VERSION 5.8 ;
BUSBITCHARS "[]" ;
DIVIDERCHAR "/" ;
UNITS
    DATABASE MICRONS 1000 ;
END UNITS

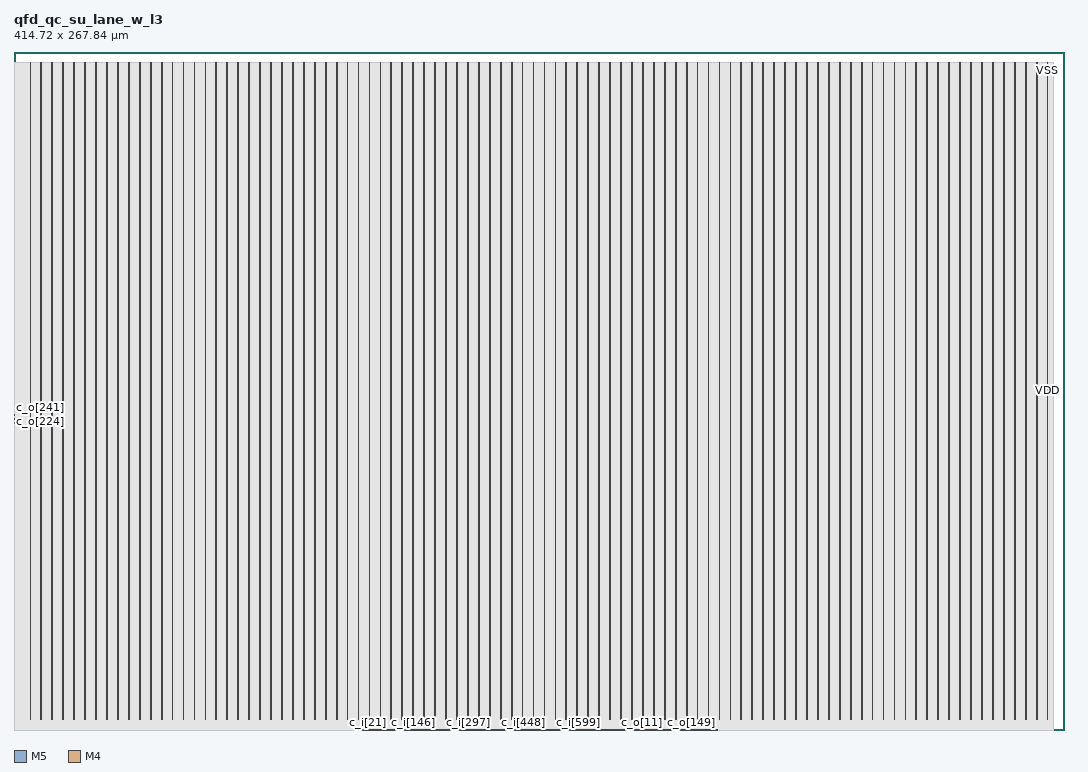
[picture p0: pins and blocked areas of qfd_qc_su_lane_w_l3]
MACRO qfd_qc_su_lane_w_l3
  FOREIGN qfd_qc_su_lane_w_l3 0 0 ;
  CLASS BLOCK ;
  SIZE 414.72 BY 267.84 ;
  PIN c_i[0]
    DIRECTION INPUT ;
    USE SIGNAL ;
    PORT
      LAYER M5 ;
        RECT  136.848 0 136.872 0.084 ;
    END
  END c_i[0]
  PIN c_i[100]
    DIRECTION INPUT ;
    USE SIGNAL ;
    PORT
      LAYER M5 ;
        RECT  151.248 0 151.272 0.084 ;
    END
  END c_i[100]
  PIN c_i[101]
    DIRECTION INPUT ;
    USE SIGNAL ;
    PORT
      LAYER M5 ;
        RECT  151.392 0 151.416 0.084 ;
    END
  END c_i[101]
  PIN c_i[102]
    DIRECTION INPUT ;
    USE SIGNAL ;
    PORT
      LAYER M5 ;
        RECT  151.536 0 151.56 0.084 ;
    END
  END c_i[102]
  PIN c_i[103]
    DIRECTION INPUT ;
    USE SIGNAL ;
    PORT
      LAYER M5 ;
        RECT  151.68 0 151.704 0.084 ;
    END
  END c_i[103]
  PIN c_i[104]
    DIRECTION INPUT ;
    USE SIGNAL ;
    PORT
      LAYER M5 ;
        RECT  151.824 0 151.848 0.084 ;
    END
  END c_i[104]
  PIN c_i[105]
    DIRECTION INPUT ;
    USE SIGNAL ;
    PORT
      LAYER M5 ;
        RECT  151.968 0 151.992 0.084 ;
    END
  END c_i[105]
  PIN c_i[106]
    DIRECTION INPUT ;
    USE SIGNAL ;
    PORT
      LAYER M5 ;
        RECT  152.112 0 152.136 0.084 ;
    END
  END c_i[106]
  PIN c_i[107]
    DIRECTION INPUT ;
    USE SIGNAL ;
    PORT
      LAYER M5 ;
        RECT  152.256 0 152.28 0.084 ;
    END
  END c_i[107]
  PIN c_i[108]
    DIRECTION INPUT ;
    USE SIGNAL ;
    PORT
      LAYER M5 ;
        RECT  152.4 0 152.424 0.084 ;
    END
  END c_i[108]
  PIN c_i[109]
    DIRECTION INPUT ;
    USE SIGNAL ;
    PORT
      LAYER M5 ;
        RECT  152.544 0 152.568 0.084 ;
    END
  END c_i[109]
  PIN c_i[10]
    DIRECTION INPUT ;
    USE SIGNAL ;
    PORT
      LAYER M5 ;
        RECT  138.288 0 138.312 0.084 ;
    END
  END c_i[10]
  PIN c_i[110]
    DIRECTION INPUT ;
    USE SIGNAL ;
    PORT
      LAYER M5 ;
        RECT  152.688 0 152.712 0.084 ;
    END
  END c_i[110]
  PIN c_i[111]
    DIRECTION INPUT ;
    USE SIGNAL ;
    PORT
      LAYER M5 ;
        RECT  152.832 0 152.856 0.084 ;
    END
  END c_i[111]
  PIN c_i[112]
    DIRECTION INPUT ;
    USE SIGNAL ;
    PORT
      LAYER M5 ;
        RECT  152.976 0 153 0.084 ;
    END
  END c_i[112]
  PIN c_i[113]
    DIRECTION INPUT ;
    USE SIGNAL ;
    PORT
      LAYER M5 ;
        RECT  153.12 0 153.144 0.084 ;
    END
  END c_i[113]
  PIN c_i[114]
    DIRECTION INPUT ;
    USE SIGNAL ;
    PORT
      LAYER M5 ;
        RECT  153.264 0 153.288 0.084 ;
    END
  END c_i[114]
  PIN c_i[115]
    DIRECTION INPUT ;
    USE SIGNAL ;
    PORT
      LAYER M5 ;
        RECT  153.408 0 153.432 0.084 ;
    END
  END c_i[115]
  PIN c_i[116]
    DIRECTION INPUT ;
    USE SIGNAL ;
    PORT
      LAYER M5 ;
        RECT  153.552 0 153.576 0.084 ;
    END
  END c_i[116]
  PIN c_i[117]
    DIRECTION INPUT ;
    USE SIGNAL ;
    PORT
      LAYER M5 ;
        RECT  153.696 0 153.72 0.084 ;
    END
  END c_i[117]
  PIN c_i[118]
    DIRECTION INPUT ;
    USE SIGNAL ;
    PORT
      LAYER M5 ;
        RECT  153.84 0 153.864 0.084 ;
    END
  END c_i[118]
  PIN c_i[119]
    DIRECTION INPUT ;
    USE SIGNAL ;
    PORT
      LAYER M5 ;
        RECT  153.984 0 154.008 0.084 ;
    END
  END c_i[119]
  PIN c_i[11]
    DIRECTION INPUT ;
    USE SIGNAL ;
    PORT
      LAYER M5 ;
        RECT  138.432 0 138.456 0.084 ;
    END
  END c_i[11]
  PIN c_i[120]
    DIRECTION INPUT ;
    USE SIGNAL ;
    PORT
      LAYER M5 ;
        RECT  154.128 0 154.152 0.084 ;
    END
  END c_i[120]
  PIN c_i[121]
    DIRECTION INPUT ;
    USE SIGNAL ;
    PORT
      LAYER M5 ;
        RECT  154.272 0 154.296 0.084 ;
    END
  END c_i[121]
  PIN c_i[122]
    DIRECTION INPUT ;
    USE SIGNAL ;
    PORT
      LAYER M5 ;
        RECT  154.416 0 154.44 0.084 ;
    END
  END c_i[122]
  PIN c_i[123]
    DIRECTION INPUT ;
    USE SIGNAL ;
    PORT
      LAYER M5 ;
        RECT  154.56 0 154.584 0.084 ;
    END
  END c_i[123]
  PIN c_i[124]
    DIRECTION INPUT ;
    USE SIGNAL ;
    PORT
      LAYER M5 ;
        RECT  154.704 0 154.728 0.084 ;
    END
  END c_i[124]
  PIN c_i[125]
    DIRECTION INPUT ;
    USE SIGNAL ;
    PORT
      LAYER M5 ;
        RECT  154.848 0 154.872 0.084 ;
    END
  END c_i[125]
  PIN c_i[126]
    DIRECTION INPUT ;
    USE SIGNAL ;
    PORT
      LAYER M5 ;
        RECT  154.992 0 155.016 0.084 ;
    END
  END c_i[126]
  PIN c_i[127]
    DIRECTION INPUT ;
    USE SIGNAL ;
    PORT
      LAYER M5 ;
        RECT  155.136 0 155.16 0.084 ;
    END
  END c_i[127]
  PIN c_i[128]
    DIRECTION INPUT ;
    USE SIGNAL ;
    PORT
      LAYER M5 ;
        RECT  155.28 0 155.304 0.084 ;
    END
  END c_i[128]
  PIN c_i[129]
    DIRECTION INPUT ;
    USE SIGNAL ;
    PORT
      LAYER M5 ;
        RECT  155.424 0 155.448 0.084 ;
    END
  END c_i[129]
  PIN c_i[12]
    DIRECTION INPUT ;
    USE SIGNAL ;
    PORT
      LAYER M5 ;
        RECT  138.576 0 138.6 0.084 ;
    END
  END c_i[12]
  PIN c_i[130]
    DIRECTION INPUT ;
    USE SIGNAL ;
    PORT
      LAYER M5 ;
        RECT  155.568 0 155.592 0.084 ;
    END
  END c_i[130]
  PIN c_i[131]
    DIRECTION INPUT ;
    USE SIGNAL ;
    PORT
      LAYER M5 ;
        RECT  155.712 0 155.736 0.084 ;
    END
  END c_i[131]
  PIN c_i[132]
    DIRECTION INPUT ;
    USE SIGNAL ;
    PORT
      LAYER M5 ;
        RECT  155.856 0 155.88 0.084 ;
    END
  END c_i[132]
  PIN c_i[133]
    DIRECTION INPUT ;
    USE SIGNAL ;
    PORT
      LAYER M5 ;
        RECT  156 0 156.024 0.084 ;
    END
  END c_i[133]
  PIN c_i[134]
    DIRECTION INPUT ;
    USE SIGNAL ;
    PORT
      LAYER M5 ;
        RECT  156.144 0 156.168 0.084 ;
    END
  END c_i[134]
  PIN c_i[135]
    DIRECTION INPUT ;
    USE SIGNAL ;
    PORT
      LAYER M5 ;
        RECT  156.288 0 156.312 0.084 ;
    END
  END c_i[135]
  PIN c_i[136]
    DIRECTION INPUT ;
    USE SIGNAL ;
    PORT
      LAYER M5 ;
        RECT  156.432 0 156.456 0.084 ;
    END
  END c_i[136]
  PIN c_i[137]
    DIRECTION INPUT ;
    USE SIGNAL ;
    PORT
      LAYER M5 ;
        RECT  156.576 0 156.6 0.084 ;
    END
  END c_i[137]
  PIN c_i[138]
    DIRECTION INPUT ;
    USE SIGNAL ;
    PORT
      LAYER M5 ;
        RECT  156.72 0 156.744 0.084 ;
    END
  END c_i[138]
  PIN c_i[139]
    DIRECTION INPUT ;
    USE SIGNAL ;
    PORT
      LAYER M5 ;
        RECT  156.864 0 156.888 0.084 ;
    END
  END c_i[139]
  PIN c_i[13]
    DIRECTION INPUT ;
    USE SIGNAL ;
    PORT
      LAYER M5 ;
        RECT  138.72 0 138.744 0.084 ;
    END
  END c_i[13]
  PIN c_i[140]
    DIRECTION INPUT ;
    USE SIGNAL ;
    PORT
      LAYER M5 ;
        RECT  157.008 0 157.032 0.084 ;
    END
  END c_i[140]
  PIN c_i[141]
    DIRECTION INPUT ;
    USE SIGNAL ;
    PORT
      LAYER M5 ;
        RECT  157.152 0 157.176 0.084 ;
    END
  END c_i[141]
  PIN c_i[142]
    DIRECTION INPUT ;
    USE SIGNAL ;
    PORT
      LAYER M5 ;
        RECT  157.296 0 157.32 0.084 ;
    END
  END c_i[142]
  PIN c_i[143]
    DIRECTION INPUT ;
    USE SIGNAL ;
    PORT
      LAYER M5 ;
        RECT  157.44 0 157.464 0.084 ;
    END
  END c_i[143]
  PIN c_i[144]
    DIRECTION INPUT ;
    USE SIGNAL ;
    PORT
      LAYER M5 ;
        RECT  157.584 0 157.608 0.084 ;
    END
  END c_i[144]
  PIN c_i[145]
    DIRECTION INPUT ;
    USE SIGNAL ;
    PORT
      LAYER M5 ;
        RECT  157.728 0 157.752 0.084 ;
    END
  END c_i[145]
  PIN c_i[146]
    DIRECTION INPUT ;
    USE SIGNAL ;
    PORT
      LAYER M5 ;
        RECT  157.872 0 157.896 0.084 ;
    END
  END c_i[146]
  PIN c_i[147]
    DIRECTION INPUT ;
    USE SIGNAL ;
    PORT
      LAYER M5 ;
        RECT  158.016 0 158.04 0.084 ;
    END
  END c_i[147]
  PIN c_i[148]
    DIRECTION INPUT ;
    USE SIGNAL ;
    PORT
      LAYER M5 ;
        RECT  158.16 0 158.184 0.084 ;
    END
  END c_i[148]
  PIN c_i[149]
    DIRECTION INPUT ;
    USE SIGNAL ;
    PORT
      LAYER M5 ;
        RECT  158.304 0 158.328 0.084 ;
    END
  END c_i[149]
  PIN c_i[14]
    DIRECTION INPUT ;
    USE SIGNAL ;
    PORT
      LAYER M5 ;
        RECT  138.864 0 138.888 0.084 ;
    END
  END c_i[14]
  PIN c_i[150]
    DIRECTION INPUT ;
    USE SIGNAL ;
    PORT
      LAYER M5 ;
        RECT  158.448 0 158.472 0.084 ;
    END
  END c_i[150]
  PIN c_i[151]
    DIRECTION INPUT ;
    USE SIGNAL ;
    PORT
      LAYER M5 ;
        RECT  158.592 0 158.616 0.084 ;
    END
  END c_i[151]
  PIN c_i[152]
    DIRECTION INPUT ;
    USE SIGNAL ;
    PORT
      LAYER M5 ;
        RECT  158.736 0 158.76 0.084 ;
    END
  END c_i[152]
  PIN c_i[153]
    DIRECTION INPUT ;
    USE SIGNAL ;
    PORT
      LAYER M5 ;
        RECT  158.88 0 158.904 0.084 ;
    END
  END c_i[153]
  PIN c_i[154]
    DIRECTION INPUT ;
    USE SIGNAL ;
    PORT
      LAYER M5 ;
        RECT  159.024 0 159.048 0.084 ;
    END
  END c_i[154]
  PIN c_i[155]
    DIRECTION INPUT ;
    USE SIGNAL ;
    PORT
      LAYER M5 ;
        RECT  159.168 0 159.192 0.084 ;
    END
  END c_i[155]
  PIN c_i[156]
    DIRECTION INPUT ;
    USE SIGNAL ;
    PORT
      LAYER M5 ;
        RECT  159.312 0 159.336 0.084 ;
    END
  END c_i[156]
  PIN c_i[157]
    DIRECTION INPUT ;
    USE SIGNAL ;
    PORT
      LAYER M5 ;
        RECT  159.456 0 159.48 0.084 ;
    END
  END c_i[157]
  PIN c_i[158]
    DIRECTION INPUT ;
    USE SIGNAL ;
    PORT
      LAYER M5 ;
        RECT  159.6 0 159.624 0.084 ;
    END
  END c_i[158]
  PIN c_i[159]
    DIRECTION INPUT ;
    USE SIGNAL ;
    PORT
      LAYER M5 ;
        RECT  159.744 0 159.768 0.084 ;
    END
  END c_i[159]
  PIN c_i[15]
    DIRECTION INPUT ;
    USE SIGNAL ;
    PORT
      LAYER M5 ;
        RECT  139.008 0 139.032 0.084 ;
    END
  END c_i[15]
  PIN c_i[160]
    DIRECTION INPUT ;
    USE SIGNAL ;
    PORT
      LAYER M5 ;
        RECT  159.888 0 159.912 0.084 ;
    END
  END c_i[160]
  PIN c_i[161]
    DIRECTION INPUT ;
    USE SIGNAL ;
    PORT
      LAYER M5 ;
        RECT  160.032 0 160.056 0.084 ;
    END
  END c_i[161]
  PIN c_i[162]
    DIRECTION INPUT ;
    USE SIGNAL ;
    PORT
      LAYER M5 ;
        RECT  160.176 0 160.2 0.084 ;
    END
  END c_i[162]
  PIN c_i[163]
    DIRECTION INPUT ;
    USE SIGNAL ;
    PORT
      LAYER M5 ;
        RECT  160.32 0 160.344 0.084 ;
    END
  END c_i[163]
  PIN c_i[164]
    DIRECTION INPUT ;
    USE SIGNAL ;
    PORT
      LAYER M5 ;
        RECT  160.464 0 160.488 0.084 ;
    END
  END c_i[164]
  PIN c_i[165]
    DIRECTION INPUT ;
    USE SIGNAL ;
    PORT
      LAYER M5 ;
        RECT  160.608 0 160.632 0.084 ;
    END
  END c_i[165]
  PIN c_i[166]
    DIRECTION INPUT ;
    USE SIGNAL ;
    PORT
      LAYER M5 ;
        RECT  160.752 0 160.776 0.084 ;
    END
  END c_i[166]
  PIN c_i[167]
    DIRECTION INPUT ;
    USE SIGNAL ;
    PORT
      LAYER M5 ;
        RECT  160.896 0 160.92 0.084 ;
    END
  END c_i[167]
  PIN c_i[168]
    DIRECTION INPUT ;
    USE SIGNAL ;
    PORT
      LAYER M5 ;
        RECT  161.04 0 161.064 0.084 ;
    END
  END c_i[168]
  PIN c_i[169]
    DIRECTION INPUT ;
    USE SIGNAL ;
    PORT
      LAYER M5 ;
        RECT  161.184 0 161.208 0.084 ;
    END
  END c_i[169]
  PIN c_i[16]
    DIRECTION INPUT ;
    USE SIGNAL ;
    PORT
      LAYER M5 ;
        RECT  139.152 0 139.176 0.084 ;
    END
  END c_i[16]
  PIN c_i[170]
    DIRECTION INPUT ;
    USE SIGNAL ;
    PORT
      LAYER M5 ;
        RECT  161.328 0 161.352 0.084 ;
    END
  END c_i[170]
  PIN c_i[171]
    DIRECTION INPUT ;
    USE SIGNAL ;
    PORT
      LAYER M5 ;
        RECT  161.472 0 161.496 0.084 ;
    END
  END c_i[171]
  PIN c_i[172]
    DIRECTION INPUT ;
    USE SIGNAL ;
    PORT
      LAYER M5 ;
        RECT  161.616 0 161.64 0.084 ;
    END
  END c_i[172]
  PIN c_i[173]
    DIRECTION INPUT ;
    USE SIGNAL ;
    PORT
      LAYER M5 ;
        RECT  161.76 0 161.784 0.084 ;
    END
  END c_i[173]
  PIN c_i[174]
    DIRECTION INPUT ;
    USE SIGNAL ;
    PORT
      LAYER M5 ;
        RECT  161.904 0 161.928 0.084 ;
    END
  END c_i[174]
  PIN c_i[175]
    DIRECTION INPUT ;
    USE SIGNAL ;
    PORT
      LAYER M5 ;
        RECT  162.048 0 162.072 0.084 ;
    END
  END c_i[175]
  PIN c_i[176]
    DIRECTION INPUT ;
    USE SIGNAL ;
    PORT
      LAYER M5 ;
        RECT  162.192 0 162.216 0.084 ;
    END
  END c_i[176]
  PIN c_i[177]
    DIRECTION INPUT ;
    USE SIGNAL ;
    PORT
      LAYER M5 ;
        RECT  162.336 0 162.36 0.084 ;
    END
  END c_i[177]
  PIN c_i[178]
    DIRECTION INPUT ;
    USE SIGNAL ;
    PORT
      LAYER M5 ;
        RECT  162.48 0 162.504 0.084 ;
    END
  END c_i[178]
  PIN c_i[179]
    DIRECTION INPUT ;
    USE SIGNAL ;
    PORT
      LAYER M5 ;
        RECT  162.624 0 162.648 0.084 ;
    END
  END c_i[179]
  PIN c_i[17]
    DIRECTION INPUT ;
    USE SIGNAL ;
    PORT
      LAYER M5 ;
        RECT  139.296 0 139.32 0.084 ;
    END
  END c_i[17]
  PIN c_i[180]
    DIRECTION INPUT ;
    USE SIGNAL ;
    PORT
      LAYER M5 ;
        RECT  162.768 0 162.792 0.084 ;
    END
  END c_i[180]
  PIN c_i[181]
    DIRECTION INPUT ;
    USE SIGNAL ;
    PORT
      LAYER M5 ;
        RECT  162.912 0 162.936 0.084 ;
    END
  END c_i[181]
  PIN c_i[182]
    DIRECTION INPUT ;
    USE SIGNAL ;
    PORT
      LAYER M5 ;
        RECT  163.056 0 163.08 0.084 ;
    END
  END c_i[182]
  PIN c_i[183]
    DIRECTION INPUT ;
    USE SIGNAL ;
    PORT
      LAYER M5 ;
        RECT  163.2 0 163.224 0.084 ;
    END
  END c_i[183]
  PIN c_i[184]
    DIRECTION INPUT ;
    USE SIGNAL ;
    PORT
      LAYER M5 ;
        RECT  163.344 0 163.368 0.084 ;
    END
  END c_i[184]
  PIN c_i[185]
    DIRECTION INPUT ;
    USE SIGNAL ;
    PORT
      LAYER M5 ;
        RECT  163.488 0 163.512 0.084 ;
    END
  END c_i[185]
  PIN c_i[186]
    DIRECTION INPUT ;
    USE SIGNAL ;
    PORT
      LAYER M5 ;
        RECT  163.632 0 163.656 0.084 ;
    END
  END c_i[186]
  PIN c_i[187]
    DIRECTION INPUT ;
    USE SIGNAL ;
    PORT
      LAYER M5 ;
        RECT  163.776 0 163.8 0.084 ;
    END
  END c_i[187]
  PIN c_i[188]
    DIRECTION INPUT ;
    USE SIGNAL ;
    PORT
      LAYER M5 ;
        RECT  163.92 0 163.944 0.084 ;
    END
  END c_i[188]
  PIN c_i[189]
    DIRECTION INPUT ;
    USE SIGNAL ;
    PORT
      LAYER M5 ;
        RECT  164.064 0 164.088 0.084 ;
    END
  END c_i[189]
  PIN c_i[18]
    DIRECTION INPUT ;
    USE SIGNAL ;
    PORT
      LAYER M5 ;
        RECT  139.44 0 139.464 0.084 ;
    END
  END c_i[18]
  PIN c_i[190]
    DIRECTION INPUT ;
    USE SIGNAL ;
    PORT
      LAYER M5 ;
        RECT  164.208 0 164.232 0.084 ;
    END
  END c_i[190]
  PIN c_i[191]
    DIRECTION INPUT ;
    USE SIGNAL ;
    PORT
      LAYER M5 ;
        RECT  164.352 0 164.376 0.084 ;
    END
  END c_i[191]
  PIN c_i[192]
    DIRECTION INPUT ;
    USE SIGNAL ;
    PORT
      LAYER M5 ;
        RECT  164.496 0 164.52 0.084 ;
    END
  END c_i[192]
  PIN c_i[193]
    DIRECTION INPUT ;
    USE SIGNAL ;
    PORT
      LAYER M5 ;
        RECT  164.64 0 164.664 0.084 ;
    END
  END c_i[193]
  PIN c_i[194]
    DIRECTION INPUT ;
    USE SIGNAL ;
    PORT
      LAYER M5 ;
        RECT  164.784 0 164.808 0.084 ;
    END
  END c_i[194]
  PIN c_i[195]
    DIRECTION INPUT ;
    USE SIGNAL ;
    PORT
      LAYER M5 ;
        RECT  164.928 0 164.952 0.084 ;
    END
  END c_i[195]
  PIN c_i[196]
    DIRECTION INPUT ;
    USE SIGNAL ;
    PORT
      LAYER M5 ;
        RECT  165.072 0 165.096 0.084 ;
    END
  END c_i[196]
  PIN c_i[197]
    DIRECTION INPUT ;
    USE SIGNAL ;
    PORT
      LAYER M5 ;
        RECT  165.216 0 165.24 0.084 ;
    END
  END c_i[197]
  PIN c_i[198]
    DIRECTION INPUT ;
    USE SIGNAL ;
    PORT
      LAYER M5 ;
        RECT  165.36 0 165.384 0.084 ;
    END
  END c_i[198]
  PIN c_i[199]
    DIRECTION INPUT ;
    USE SIGNAL ;
    PORT
      LAYER M5 ;
        RECT  165.504 0 165.528 0.084 ;
    END
  END c_i[199]
  PIN c_i[19]
    DIRECTION INPUT ;
    USE SIGNAL ;
    PORT
      LAYER M5 ;
        RECT  139.584 0 139.608 0.084 ;
    END
  END c_i[19]
  PIN c_i[1]
    DIRECTION INPUT ;
    USE SIGNAL ;
    PORT
      LAYER M5 ;
        RECT  136.992 0 137.016 0.084 ;
    END
  END c_i[1]
  PIN c_i[200]
    DIRECTION INPUT ;
    USE SIGNAL ;
    PORT
      LAYER M5 ;
        RECT  165.648 0 165.672 0.084 ;
    END
  END c_i[200]
  PIN c_i[201]
    DIRECTION INPUT ;
    USE SIGNAL ;
    PORT
      LAYER M5 ;
        RECT  165.792 0 165.816 0.084 ;
    END
  END c_i[201]
  PIN c_i[202]
    DIRECTION INPUT ;
    USE SIGNAL ;
    PORT
      LAYER M5 ;
        RECT  165.936 0 165.96 0.084 ;
    END
  END c_i[202]
  PIN c_i[203]
    DIRECTION INPUT ;
    USE SIGNAL ;
    PORT
      LAYER M5 ;
        RECT  166.08 0 166.104 0.084 ;
    END
  END c_i[203]
  PIN c_i[204]
    DIRECTION INPUT ;
    USE SIGNAL ;
    PORT
      LAYER M5 ;
        RECT  166.224 0 166.248 0.084 ;
    END
  END c_i[204]
  PIN c_i[205]
    DIRECTION INPUT ;
    USE SIGNAL ;
    PORT
      LAYER M5 ;
        RECT  166.368 0 166.392 0.084 ;
    END
  END c_i[205]
  PIN c_i[206]
    DIRECTION INPUT ;
    USE SIGNAL ;
    PORT
      LAYER M5 ;
        RECT  166.512 0 166.536 0.084 ;
    END
  END c_i[206]
  PIN c_i[207]
    DIRECTION INPUT ;
    USE SIGNAL ;
    PORT
      LAYER M5 ;
        RECT  166.656 0 166.68 0.084 ;
    END
  END c_i[207]
  PIN c_i[208]
    DIRECTION INPUT ;
    USE SIGNAL ;
    PORT
      LAYER M5 ;
        RECT  166.8 0 166.824 0.084 ;
    END
  END c_i[208]
  PIN c_i[209]
    DIRECTION INPUT ;
    USE SIGNAL ;
    PORT
      LAYER M5 ;
        RECT  166.944 0 166.968 0.084 ;
    END
  END c_i[209]
  PIN c_i[20]
    DIRECTION INPUT ;
    USE SIGNAL ;
    PORT
      LAYER M5 ;
        RECT  139.728 0 139.752 0.084 ;
    END
  END c_i[20]
  PIN c_i[210]
    DIRECTION INPUT ;
    USE SIGNAL ;
    PORT
      LAYER M5 ;
        RECT  167.088 0 167.112 0.084 ;
    END
  END c_i[210]
  PIN c_i[211]
    DIRECTION INPUT ;
    USE SIGNAL ;
    PORT
      LAYER M5 ;
        RECT  167.232 0 167.256 0.084 ;
    END
  END c_i[211]
  PIN c_i[212]
    DIRECTION INPUT ;
    USE SIGNAL ;
    PORT
      LAYER M5 ;
        RECT  167.376 0 167.4 0.084 ;
    END
  END c_i[212]
  PIN c_i[213]
    DIRECTION INPUT ;
    USE SIGNAL ;
    PORT
      LAYER M5 ;
        RECT  167.52 0 167.544 0.084 ;
    END
  END c_i[213]
  PIN c_i[214]
    DIRECTION INPUT ;
    USE SIGNAL ;
    PORT
      LAYER M5 ;
        RECT  167.664 0 167.688 0.084 ;
    END
  END c_i[214]
  PIN c_i[215]
    DIRECTION INPUT ;
    USE SIGNAL ;
    PORT
      LAYER M5 ;
        RECT  167.808 0 167.832 0.084 ;
    END
  END c_i[215]
  PIN c_i[216]
    DIRECTION INPUT ;
    USE SIGNAL ;
    PORT
      LAYER M5 ;
        RECT  167.952 0 167.976 0.084 ;
    END
  END c_i[216]
  PIN c_i[217]
    DIRECTION INPUT ;
    USE SIGNAL ;
    PORT
      LAYER M5 ;
        RECT  168.096 0 168.12 0.084 ;
    END
  END c_i[217]
  PIN c_i[218]
    DIRECTION INPUT ;
    USE SIGNAL ;
    PORT
      LAYER M5 ;
        RECT  168.24 0 168.264 0.084 ;
    END
  END c_i[218]
  PIN c_i[219]
    DIRECTION INPUT ;
    USE SIGNAL ;
    PORT
      LAYER M5 ;
        RECT  168.384 0 168.408 0.084 ;
    END
  END c_i[219]
  PIN c_i[21]
    DIRECTION INPUT ;
    USE SIGNAL ;
    PORT
      LAYER M5 ;
        RECT  139.872 0 139.896 0.084 ;
    END
  END c_i[21]
  PIN c_i[220]
    DIRECTION INPUT ;
    USE SIGNAL ;
    PORT
      LAYER M5 ;
        RECT  168.528 0 168.552 0.084 ;
    END
  END c_i[220]
  PIN c_i[221]
    DIRECTION INPUT ;
    USE SIGNAL ;
    PORT
      LAYER M5 ;
        RECT  168.672 0 168.696 0.084 ;
    END
  END c_i[221]
  PIN c_i[222]
    DIRECTION INPUT ;
    USE SIGNAL ;
    PORT
      LAYER M5 ;
        RECT  168.816 0 168.84 0.084 ;
    END
  END c_i[222]
  PIN c_i[223]
    DIRECTION INPUT ;
    USE SIGNAL ;
    PORT
      LAYER M5 ;
        RECT  168.96 0 168.984 0.084 ;
    END
  END c_i[223]
  PIN c_i[224]
    DIRECTION INPUT ;
    USE SIGNAL ;
    PORT
      LAYER M5 ;
        RECT  169.104 0 169.128 0.084 ;
    END
  END c_i[224]
  PIN c_i[225]
    DIRECTION INPUT ;
    USE SIGNAL ;
    PORT
      LAYER M5 ;
        RECT  169.248 0 169.272 0.084 ;
    END
  END c_i[225]
  PIN c_i[226]
    DIRECTION INPUT ;
    USE SIGNAL ;
    PORT
      LAYER M5 ;
        RECT  169.392 0 169.416 0.084 ;
    END
  END c_i[226]
  PIN c_i[227]
    DIRECTION INPUT ;
    USE SIGNAL ;
    PORT
      LAYER M5 ;
        RECT  169.536 0 169.56 0.084 ;
    END
  END c_i[227]
  PIN c_i[228]
    DIRECTION INPUT ;
    USE SIGNAL ;
    PORT
      LAYER M5 ;
        RECT  169.68 0 169.704 0.084 ;
    END
  END c_i[228]
  PIN c_i[229]
    DIRECTION INPUT ;
    USE SIGNAL ;
    PORT
      LAYER M5 ;
        RECT  169.824 0 169.848 0.084 ;
    END
  END c_i[229]
  PIN c_i[22]
    DIRECTION INPUT ;
    USE SIGNAL ;
    PORT
      LAYER M5 ;
        RECT  140.016 0 140.04 0.084 ;
    END
  END c_i[22]
  PIN c_i[230]
    DIRECTION INPUT ;
    USE SIGNAL ;
    PORT
      LAYER M5 ;
        RECT  169.968 0 169.992 0.084 ;
    END
  END c_i[230]
  PIN c_i[231]
    DIRECTION INPUT ;
    USE SIGNAL ;
    PORT
      LAYER M5 ;
        RECT  170.112 0 170.136 0.084 ;
    END
  END c_i[231]
  PIN c_i[232]
    DIRECTION INPUT ;
    USE SIGNAL ;
    PORT
      LAYER M5 ;
        RECT  170.256 0 170.28 0.084 ;
    END
  END c_i[232]
  PIN c_i[233]
    DIRECTION INPUT ;
    USE SIGNAL ;
    PORT
      LAYER M5 ;
        RECT  170.4 0 170.424 0.084 ;
    END
  END c_i[233]
  PIN c_i[234]
    DIRECTION INPUT ;
    USE SIGNAL ;
    PORT
      LAYER M5 ;
        RECT  170.544 0 170.568 0.084 ;
    END
  END c_i[234]
  PIN c_i[235]
    DIRECTION INPUT ;
    USE SIGNAL ;
    PORT
      LAYER M5 ;
        RECT  170.688 0 170.712 0.084 ;
    END
  END c_i[235]
  PIN c_i[236]
    DIRECTION INPUT ;
    USE SIGNAL ;
    PORT
      LAYER M5 ;
        RECT  170.832 0 170.856 0.084 ;
    END
  END c_i[236]
  PIN c_i[237]
    DIRECTION INPUT ;
    USE SIGNAL ;
    PORT
      LAYER M5 ;
        RECT  170.976 0 171 0.084 ;
    END
  END c_i[237]
  PIN c_i[238]
    DIRECTION INPUT ;
    USE SIGNAL ;
    PORT
      LAYER M5 ;
        RECT  171.12 0 171.144 0.084 ;
    END
  END c_i[238]
  PIN c_i[239]
    DIRECTION INPUT ;
    USE SIGNAL ;
    PORT
      LAYER M5 ;
        RECT  171.264 0 171.288 0.084 ;
    END
  END c_i[239]
  PIN c_i[23]
    DIRECTION INPUT ;
    USE SIGNAL ;
    PORT
      LAYER M5 ;
        RECT  140.16 0 140.184 0.084 ;
    END
  END c_i[23]
  PIN c_i[240]
    DIRECTION INPUT ;
    USE SIGNAL ;
    PORT
      LAYER M5 ;
        RECT  171.408 0 171.432 0.084 ;
    END
  END c_i[240]
  PIN c_i[241]
    DIRECTION INPUT ;
    USE SIGNAL ;
    PORT
      LAYER M5 ;
        RECT  171.552 0 171.576 0.084 ;
    END
  END c_i[241]
  PIN c_i[242]
    DIRECTION INPUT ;
    USE SIGNAL ;
    PORT
      LAYER M5 ;
        RECT  171.696 0 171.72 0.084 ;
    END
  END c_i[242]
  PIN c_i[243]
    DIRECTION INPUT ;
    USE SIGNAL ;
    PORT
      LAYER M5 ;
        RECT  171.84 0 171.864 0.084 ;
    END
  END c_i[243]
  PIN c_i[244]
    DIRECTION INPUT ;
    USE SIGNAL ;
    PORT
      LAYER M5 ;
        RECT  171.984 0 172.008 0.084 ;
    END
  END c_i[244]
  PIN c_i[245]
    DIRECTION INPUT ;
    USE SIGNAL ;
    PORT
      LAYER M5 ;
        RECT  172.128 0 172.152 0.084 ;
    END
  END c_i[245]
  PIN c_i[246]
    DIRECTION INPUT ;
    USE SIGNAL ;
    PORT
      LAYER M5 ;
        RECT  172.272 0 172.296 0.084 ;
    END
  END c_i[246]
  PIN c_i[247]
    DIRECTION INPUT ;
    USE SIGNAL ;
    PORT
      LAYER M5 ;
        RECT  172.416 0 172.44 0.084 ;
    END
  END c_i[247]
  PIN c_i[248]
    DIRECTION INPUT ;
    USE SIGNAL ;
    PORT
      LAYER M5 ;
        RECT  172.56 0 172.584 0.084 ;
    END
  END c_i[248]
  PIN c_i[249]
    DIRECTION INPUT ;
    USE SIGNAL ;
    PORT
      LAYER M5 ;
        RECT  172.704 0 172.728 0.084 ;
    END
  END c_i[249]
  PIN c_i[24]
    DIRECTION INPUT ;
    USE SIGNAL ;
    PORT
      LAYER M5 ;
        RECT  140.304 0 140.328 0.084 ;
    END
  END c_i[24]
  PIN c_i[250]
    DIRECTION INPUT ;
    USE SIGNAL ;
    PORT
      LAYER M5 ;
        RECT  172.848 0 172.872 0.084 ;
    END
  END c_i[250]
  PIN c_i[251]
    DIRECTION INPUT ;
    USE SIGNAL ;
    PORT
      LAYER M5 ;
        RECT  172.992 0 173.016 0.084 ;
    END
  END c_i[251]
  PIN c_i[252]
    DIRECTION INPUT ;
    USE SIGNAL ;
    PORT
      LAYER M5 ;
        RECT  173.136 0 173.16 0.084 ;
    END
  END c_i[252]
  PIN c_i[253]
    DIRECTION INPUT ;
    USE SIGNAL ;
    PORT
      LAYER M5 ;
        RECT  173.28 0 173.304 0.084 ;
    END
  END c_i[253]
  PIN c_i[254]
    DIRECTION INPUT ;
    USE SIGNAL ;
    PORT
      LAYER M5 ;
        RECT  173.424 0 173.448 0.084 ;
    END
  END c_i[254]
  PIN c_i[255]
    DIRECTION INPUT ;
    USE SIGNAL ;
    PORT
      LAYER M5 ;
        RECT  173.568 0 173.592 0.084 ;
    END
  END c_i[255]
  PIN c_i[256]
    DIRECTION INPUT ;
    USE SIGNAL ;
    PORT
      LAYER M5 ;
        RECT  173.712 0 173.736 0.084 ;
    END
  END c_i[256]
  PIN c_i[257]
    DIRECTION INPUT ;
    USE SIGNAL ;
    PORT
      LAYER M5 ;
        RECT  173.856 0 173.88 0.084 ;
    END
  END c_i[257]
  PIN c_i[258]
    DIRECTION INPUT ;
    USE SIGNAL ;
    PORT
      LAYER M5 ;
        RECT  174 0 174.024 0.084 ;
    END
  END c_i[258]
  PIN c_i[259]
    DIRECTION INPUT ;
    USE SIGNAL ;
    PORT
      LAYER M5 ;
        RECT  174.144 0 174.168 0.084 ;
    END
  END c_i[259]
  PIN c_i[25]
    DIRECTION INPUT ;
    USE SIGNAL ;
    PORT
      LAYER M5 ;
        RECT  140.448 0 140.472 0.084 ;
    END
  END c_i[25]
  PIN c_i[260]
    DIRECTION INPUT ;
    USE SIGNAL ;
    PORT
      LAYER M5 ;
        RECT  174.288 0 174.312 0.084 ;
    END
  END c_i[260]
  PIN c_i[261]
    DIRECTION INPUT ;
    USE SIGNAL ;
    PORT
      LAYER M5 ;
        RECT  174.432 0 174.456 0.084 ;
    END
  END c_i[261]
  PIN c_i[262]
    DIRECTION INPUT ;
    USE SIGNAL ;
    PORT
      LAYER M5 ;
        RECT  174.576 0 174.6 0.084 ;
    END
  END c_i[262]
  PIN c_i[263]
    DIRECTION INPUT ;
    USE SIGNAL ;
    PORT
      LAYER M5 ;
        RECT  174.72 0 174.744 0.084 ;
    END
  END c_i[263]
  PIN c_i[264]
    DIRECTION INPUT ;
    USE SIGNAL ;
    PORT
      LAYER M5 ;
        RECT  174.864 0 174.888 0.084 ;
    END
  END c_i[264]
  PIN c_i[265]
    DIRECTION INPUT ;
    USE SIGNAL ;
    PORT
      LAYER M5 ;
        RECT  175.008 0 175.032 0.084 ;
    END
  END c_i[265]
  PIN c_i[266]
    DIRECTION INPUT ;
    USE SIGNAL ;
    PORT
      LAYER M5 ;
        RECT  175.152 0 175.176 0.084 ;
    END
  END c_i[266]
  PIN c_i[267]
    DIRECTION INPUT ;
    USE SIGNAL ;
    PORT
      LAYER M5 ;
        RECT  175.296 0 175.32 0.084 ;
    END
  END c_i[267]
  PIN c_i[268]
    DIRECTION INPUT ;
    USE SIGNAL ;
    PORT
      LAYER M5 ;
        RECT  175.44 0 175.464 0.084 ;
    END
  END c_i[268]
  PIN c_i[269]
    DIRECTION INPUT ;
    USE SIGNAL ;
    PORT
      LAYER M5 ;
        RECT  175.584 0 175.608 0.084 ;
    END
  END c_i[269]
  PIN c_i[26]
    DIRECTION INPUT ;
    USE SIGNAL ;
    PORT
      LAYER M5 ;
        RECT  140.592 0 140.616 0.084 ;
    END
  END c_i[26]
  PIN c_i[270]
    DIRECTION INPUT ;
    USE SIGNAL ;
    PORT
      LAYER M5 ;
        RECT  175.728 0 175.752 0.084 ;
    END
  END c_i[270]
  PIN c_i[271]
    DIRECTION INPUT ;
    USE SIGNAL ;
    PORT
      LAYER M5 ;
        RECT  175.872 0 175.896 0.084 ;
    END
  END c_i[271]
  PIN c_i[272]
    DIRECTION INPUT ;
    USE SIGNAL ;
    PORT
      LAYER M5 ;
        RECT  176.016 0 176.04 0.084 ;
    END
  END c_i[272]
  PIN c_i[273]
    DIRECTION INPUT ;
    USE SIGNAL ;
    PORT
      LAYER M5 ;
        RECT  176.16 0 176.184 0.084 ;
    END
  END c_i[273]
  PIN c_i[274]
    DIRECTION INPUT ;
    USE SIGNAL ;
    PORT
      LAYER M5 ;
        RECT  176.304 0 176.328 0.084 ;
    END
  END c_i[274]
  PIN c_i[275]
    DIRECTION INPUT ;
    USE SIGNAL ;
    PORT
      LAYER M5 ;
        RECT  176.448 0 176.472 0.084 ;
    END
  END c_i[275]
  PIN c_i[276]
    DIRECTION INPUT ;
    USE SIGNAL ;
    PORT
      LAYER M5 ;
        RECT  176.592 0 176.616 0.084 ;
    END
  END c_i[276]
  PIN c_i[277]
    DIRECTION INPUT ;
    USE SIGNAL ;
    PORT
      LAYER M5 ;
        RECT  176.736 0 176.76 0.084 ;
    END
  END c_i[277]
  PIN c_i[278]
    DIRECTION INPUT ;
    USE SIGNAL ;
    PORT
      LAYER M5 ;
        RECT  176.88 0 176.904 0.084 ;
    END
  END c_i[278]
  PIN c_i[279]
    DIRECTION INPUT ;
    USE SIGNAL ;
    PORT
      LAYER M5 ;
        RECT  177.024 0 177.048 0.084 ;
    END
  END c_i[279]
  PIN c_i[27]
    DIRECTION INPUT ;
    USE SIGNAL ;
    PORT
      LAYER M5 ;
        RECT  140.736 0 140.76 0.084 ;
    END
  END c_i[27]
  PIN c_i[280]
    DIRECTION INPUT ;
    USE SIGNAL ;
    PORT
      LAYER M5 ;
        RECT  177.168 0 177.192 0.084 ;
    END
  END c_i[280]
  PIN c_i[281]
    DIRECTION INPUT ;
    USE SIGNAL ;
    PORT
      LAYER M5 ;
        RECT  177.312 0 177.336 0.084 ;
    END
  END c_i[281]
  PIN c_i[282]
    DIRECTION INPUT ;
    USE SIGNAL ;
    PORT
      LAYER M5 ;
        RECT  177.456 0 177.48 0.084 ;
    END
  END c_i[282]
  PIN c_i[283]
    DIRECTION INPUT ;
    USE SIGNAL ;
    PORT
      LAYER M5 ;
        RECT  177.6 0 177.624 0.084 ;
    END
  END c_i[283]
  PIN c_i[284]
    DIRECTION INPUT ;
    USE SIGNAL ;
    PORT
      LAYER M5 ;
        RECT  177.744 0 177.768 0.084 ;
    END
  END c_i[284]
  PIN c_i[285]
    DIRECTION INPUT ;
    USE SIGNAL ;
    PORT
      LAYER M5 ;
        RECT  177.888 0 177.912 0.084 ;
    END
  END c_i[285]
  PIN c_i[286]
    DIRECTION INPUT ;
    USE SIGNAL ;
    PORT
      LAYER M5 ;
        RECT  178.032 0 178.056 0.084 ;
    END
  END c_i[286]
  PIN c_i[287]
    DIRECTION INPUT ;
    USE SIGNAL ;
    PORT
      LAYER M5 ;
        RECT  178.176 0 178.2 0.084 ;
    END
  END c_i[287]
  PIN c_i[288]
    DIRECTION INPUT ;
    USE SIGNAL ;
    PORT
      LAYER M5 ;
        RECT  178.32 0 178.344 0.084 ;
    END
  END c_i[288]
  PIN c_i[289]
    DIRECTION INPUT ;
    USE SIGNAL ;
    PORT
      LAYER M5 ;
        RECT  178.464 0 178.488 0.084 ;
    END
  END c_i[289]
  PIN c_i[28]
    DIRECTION INPUT ;
    USE SIGNAL ;
    PORT
      LAYER M5 ;
        RECT  140.88 0 140.904 0.084 ;
    END
  END c_i[28]
  PIN c_i[290]
    DIRECTION INPUT ;
    USE SIGNAL ;
    PORT
      LAYER M5 ;
        RECT  178.608 0 178.632 0.084 ;
    END
  END c_i[290]
  PIN c_i[291]
    DIRECTION INPUT ;
    USE SIGNAL ;
    PORT
      LAYER M5 ;
        RECT  178.752 0 178.776 0.084 ;
    END
  END c_i[291]
  PIN c_i[292]
    DIRECTION INPUT ;
    USE SIGNAL ;
    PORT
      LAYER M5 ;
        RECT  178.896 0 178.92 0.084 ;
    END
  END c_i[292]
  PIN c_i[293]
    DIRECTION INPUT ;
    USE SIGNAL ;
    PORT
      LAYER M5 ;
        RECT  179.04 0 179.064 0.084 ;
    END
  END c_i[293]
  PIN c_i[294]
    DIRECTION INPUT ;
    USE SIGNAL ;
    PORT
      LAYER M5 ;
        RECT  179.184 0 179.208 0.084 ;
    END
  END c_i[294]
  PIN c_i[295]
    DIRECTION INPUT ;
    USE SIGNAL ;
    PORT
      LAYER M5 ;
        RECT  179.328 0 179.352 0.084 ;
    END
  END c_i[295]
  PIN c_i[296]
    DIRECTION INPUT ;
    USE SIGNAL ;
    PORT
      LAYER M5 ;
        RECT  179.472 0 179.496 0.084 ;
    END
  END c_i[296]
  PIN c_i[297]
    DIRECTION INPUT ;
    USE SIGNAL ;
    PORT
      LAYER M5 ;
        RECT  179.616 0 179.64 0.084 ;
    END
  END c_i[297]
  PIN c_i[298]
    DIRECTION INPUT ;
    USE SIGNAL ;
    PORT
      LAYER M5 ;
        RECT  179.76 0 179.784 0.084 ;
    END
  END c_i[298]
  PIN c_i[299]
    DIRECTION INPUT ;
    USE SIGNAL ;
    PORT
      LAYER M5 ;
        RECT  179.904 0 179.928 0.084 ;
    END
  END c_i[299]
  PIN c_i[29]
    DIRECTION INPUT ;
    USE SIGNAL ;
    PORT
      LAYER M5 ;
        RECT  141.024 0 141.048 0.084 ;
    END
  END c_i[29]
  PIN c_i[2]
    DIRECTION INPUT ;
    USE SIGNAL ;
    PORT
      LAYER M5 ;
        RECT  137.136 0 137.16 0.084 ;
    END
  END c_i[2]
  PIN c_i[300]
    DIRECTION INPUT ;
    USE SIGNAL ;
    PORT
      LAYER M5 ;
        RECT  180.048 0 180.072 0.084 ;
    END
  END c_i[300]
  PIN c_i[301]
    DIRECTION INPUT ;
    USE SIGNAL ;
    PORT
      LAYER M5 ;
        RECT  180.192 0 180.216 0.084 ;
    END
  END c_i[301]
  PIN c_i[302]
    DIRECTION INPUT ;
    USE SIGNAL ;
    PORT
      LAYER M5 ;
        RECT  180.336 0 180.36 0.084 ;
    END
  END c_i[302]
  PIN c_i[303]
    DIRECTION INPUT ;
    USE SIGNAL ;
    PORT
      LAYER M5 ;
        RECT  180.48 0 180.504 0.084 ;
    END
  END c_i[303]
  PIN c_i[304]
    DIRECTION INPUT ;
    USE SIGNAL ;
    PORT
      LAYER M5 ;
        RECT  180.624 0 180.648 0.084 ;
    END
  END c_i[304]
  PIN c_i[305]
    DIRECTION INPUT ;
    USE SIGNAL ;
    PORT
      LAYER M5 ;
        RECT  180.768 0 180.792 0.084 ;
    END
  END c_i[305]
  PIN c_i[306]
    DIRECTION INPUT ;
    USE SIGNAL ;
    PORT
      LAYER M5 ;
        RECT  180.912 0 180.936 0.084 ;
    END
  END c_i[306]
  PIN c_i[307]
    DIRECTION INPUT ;
    USE SIGNAL ;
    PORT
      LAYER M5 ;
        RECT  181.056 0 181.08 0.084 ;
    END
  END c_i[307]
  PIN c_i[308]
    DIRECTION INPUT ;
    USE SIGNAL ;
    PORT
      LAYER M5 ;
        RECT  181.2 0 181.224 0.084 ;
    END
  END c_i[308]
  PIN c_i[309]
    DIRECTION INPUT ;
    USE SIGNAL ;
    PORT
      LAYER M5 ;
        RECT  181.344 0 181.368 0.084 ;
    END
  END c_i[309]
  PIN c_i[30]
    DIRECTION INPUT ;
    USE SIGNAL ;
    PORT
      LAYER M5 ;
        RECT  141.168 0 141.192 0.084 ;
    END
  END c_i[30]
  PIN c_i[310]
    DIRECTION INPUT ;
    USE SIGNAL ;
    PORT
      LAYER M5 ;
        RECT  181.488 0 181.512 0.084 ;
    END
  END c_i[310]
  PIN c_i[311]
    DIRECTION INPUT ;
    USE SIGNAL ;
    PORT
      LAYER M5 ;
        RECT  181.632 0 181.656 0.084 ;
    END
  END c_i[311]
  PIN c_i[312]
    DIRECTION INPUT ;
    USE SIGNAL ;
    PORT
      LAYER M5 ;
        RECT  181.776 0 181.8 0.084 ;
    END
  END c_i[312]
  PIN c_i[313]
    DIRECTION INPUT ;
    USE SIGNAL ;
    PORT
      LAYER M5 ;
        RECT  181.92 0 181.944 0.084 ;
    END
  END c_i[313]
  PIN c_i[314]
    DIRECTION INPUT ;
    USE SIGNAL ;
    PORT
      LAYER M5 ;
        RECT  182.064 0 182.088 0.084 ;
    END
  END c_i[314]
  PIN c_i[315]
    DIRECTION INPUT ;
    USE SIGNAL ;
    PORT
      LAYER M5 ;
        RECT  182.208 0 182.232 0.084 ;
    END
  END c_i[315]
  PIN c_i[316]
    DIRECTION INPUT ;
    USE SIGNAL ;
    PORT
      LAYER M5 ;
        RECT  182.352 0 182.376 0.084 ;
    END
  END c_i[316]
  PIN c_i[317]
    DIRECTION INPUT ;
    USE SIGNAL ;
    PORT
      LAYER M5 ;
        RECT  182.496 0 182.52 0.084 ;
    END
  END c_i[317]
  PIN c_i[318]
    DIRECTION INPUT ;
    USE SIGNAL ;
    PORT
      LAYER M5 ;
        RECT  182.64 0 182.664 0.084 ;
    END
  END c_i[318]
  PIN c_i[319]
    DIRECTION INPUT ;
    USE SIGNAL ;
    PORT
      LAYER M5 ;
        RECT  182.784 0 182.808 0.084 ;
    END
  END c_i[319]
  PIN c_i[31]
    DIRECTION INPUT ;
    USE SIGNAL ;
    PORT
      LAYER M5 ;
        RECT  141.312 0 141.336 0.084 ;
    END
  END c_i[31]
  PIN c_i[320]
    DIRECTION INPUT ;
    USE SIGNAL ;
    PORT
      LAYER M5 ;
        RECT  182.928 0 182.952 0.084 ;
    END
  END c_i[320]
  PIN c_i[321]
    DIRECTION INPUT ;
    USE SIGNAL ;
    PORT
      LAYER M5 ;
        RECT  183.072 0 183.096 0.084 ;
    END
  END c_i[321]
  PIN c_i[322]
    DIRECTION INPUT ;
    USE SIGNAL ;
    PORT
      LAYER M5 ;
        RECT  183.216 0 183.24 0.084 ;
    END
  END c_i[322]
  PIN c_i[323]
    DIRECTION INPUT ;
    USE SIGNAL ;
    PORT
      LAYER M5 ;
        RECT  183.36 0 183.384 0.084 ;
    END
  END c_i[323]
  PIN c_i[324]
    DIRECTION INPUT ;
    USE SIGNAL ;
    PORT
      LAYER M5 ;
        RECT  183.504 0 183.528 0.084 ;
    END
  END c_i[324]
  PIN c_i[325]
    DIRECTION INPUT ;
    USE SIGNAL ;
    PORT
      LAYER M5 ;
        RECT  183.648 0 183.672 0.084 ;
    END
  END c_i[325]
  PIN c_i[326]
    DIRECTION INPUT ;
    USE SIGNAL ;
    PORT
      LAYER M5 ;
        RECT  183.792 0 183.816 0.084 ;
    END
  END c_i[326]
  PIN c_i[327]
    DIRECTION INPUT ;
    USE SIGNAL ;
    PORT
      LAYER M5 ;
        RECT  183.936 0 183.96 0.084 ;
    END
  END c_i[327]
  PIN c_i[328]
    DIRECTION INPUT ;
    USE SIGNAL ;
    PORT
      LAYER M5 ;
        RECT  184.08 0 184.104 0.084 ;
    END
  END c_i[328]
  PIN c_i[329]
    DIRECTION INPUT ;
    USE SIGNAL ;
    PORT
      LAYER M5 ;
        RECT  184.224 0 184.248 0.084 ;
    END
  END c_i[329]
  PIN c_i[32]
    DIRECTION INPUT ;
    USE SIGNAL ;
    PORT
      LAYER M5 ;
        RECT  141.456 0 141.48 0.084 ;
    END
  END c_i[32]
  PIN c_i[330]
    DIRECTION INPUT ;
    USE SIGNAL ;
    PORT
      LAYER M5 ;
        RECT  184.368 0 184.392 0.084 ;
    END
  END c_i[330]
  PIN c_i[331]
    DIRECTION INPUT ;
    USE SIGNAL ;
    PORT
      LAYER M5 ;
        RECT  184.512 0 184.536 0.084 ;
    END
  END c_i[331]
  PIN c_i[332]
    DIRECTION INPUT ;
    USE SIGNAL ;
    PORT
      LAYER M5 ;
        RECT  184.656 0 184.68 0.084 ;
    END
  END c_i[332]
  PIN c_i[333]
    DIRECTION INPUT ;
    USE SIGNAL ;
    PORT
      LAYER M5 ;
        RECT  184.8 0 184.824 0.084 ;
    END
  END c_i[333]
  PIN c_i[334]
    DIRECTION INPUT ;
    USE SIGNAL ;
    PORT
      LAYER M5 ;
        RECT  184.944 0 184.968 0.084 ;
    END
  END c_i[334]
  PIN c_i[335]
    DIRECTION INPUT ;
    USE SIGNAL ;
    PORT
      LAYER M5 ;
        RECT  185.088 0 185.112 0.084 ;
    END
  END c_i[335]
  PIN c_i[336]
    DIRECTION INPUT ;
    USE SIGNAL ;
    PORT
      LAYER M5 ;
        RECT  185.232 0 185.256 0.084 ;
    END
  END c_i[336]
  PIN c_i[337]
    DIRECTION INPUT ;
    USE SIGNAL ;
    PORT
      LAYER M5 ;
        RECT  185.376 0 185.4 0.084 ;
    END
  END c_i[337]
  PIN c_i[338]
    DIRECTION INPUT ;
    USE SIGNAL ;
    PORT
      LAYER M5 ;
        RECT  185.52 0 185.544 0.084 ;
    END
  END c_i[338]
  PIN c_i[339]
    DIRECTION INPUT ;
    USE SIGNAL ;
    PORT
      LAYER M5 ;
        RECT  185.664 0 185.688 0.084 ;
    END
  END c_i[339]
  PIN c_i[33]
    DIRECTION INPUT ;
    USE SIGNAL ;
    PORT
      LAYER M5 ;
        RECT  141.6 0 141.624 0.084 ;
    END
  END c_i[33]
  PIN c_i[340]
    DIRECTION INPUT ;
    USE SIGNAL ;
    PORT
      LAYER M5 ;
        RECT  185.808 0 185.832 0.084 ;
    END
  END c_i[340]
  PIN c_i[341]
    DIRECTION INPUT ;
    USE SIGNAL ;
    PORT
      LAYER M5 ;
        RECT  185.952 0 185.976 0.084 ;
    END
  END c_i[341]
  PIN c_i[342]
    DIRECTION INPUT ;
    USE SIGNAL ;
    PORT
      LAYER M5 ;
        RECT  186.096 0 186.12 0.084 ;
    END
  END c_i[342]
  PIN c_i[343]
    DIRECTION INPUT ;
    USE SIGNAL ;
    PORT
      LAYER M5 ;
        RECT  186.24 0 186.264 0.084 ;
    END
  END c_i[343]
  PIN c_i[344]
    DIRECTION INPUT ;
    USE SIGNAL ;
    PORT
      LAYER M5 ;
        RECT  186.384 0 186.408 0.084 ;
    END
  END c_i[344]
  PIN c_i[345]
    DIRECTION INPUT ;
    USE SIGNAL ;
    PORT
      LAYER M5 ;
        RECT  186.528 0 186.552 0.084 ;
    END
  END c_i[345]
  PIN c_i[346]
    DIRECTION INPUT ;
    USE SIGNAL ;
    PORT
      LAYER M5 ;
        RECT  186.672 0 186.696 0.084 ;
    END
  END c_i[346]
  PIN c_i[347]
    DIRECTION INPUT ;
    USE SIGNAL ;
    PORT
      LAYER M5 ;
        RECT  186.816 0 186.84 0.084 ;
    END
  END c_i[347]
  PIN c_i[348]
    DIRECTION INPUT ;
    USE SIGNAL ;
    PORT
      LAYER M5 ;
        RECT  186.96 0 186.984 0.084 ;
    END
  END c_i[348]
  PIN c_i[349]
    DIRECTION INPUT ;
    USE SIGNAL ;
    PORT
      LAYER M5 ;
        RECT  187.104 0 187.128 0.084 ;
    END
  END c_i[349]
  PIN c_i[34]
    DIRECTION INPUT ;
    USE SIGNAL ;
    PORT
      LAYER M5 ;
        RECT  141.744 0 141.768 0.084 ;
    END
  END c_i[34]
  PIN c_i[350]
    DIRECTION INPUT ;
    USE SIGNAL ;
    PORT
      LAYER M5 ;
        RECT  187.248 0 187.272 0.084 ;
    END
  END c_i[350]
  PIN c_i[351]
    DIRECTION INPUT ;
    USE SIGNAL ;
    PORT
      LAYER M5 ;
        RECT  187.392 0 187.416 0.084 ;
    END
  END c_i[351]
  PIN c_i[352]
    DIRECTION INPUT ;
    USE SIGNAL ;
    PORT
      LAYER M5 ;
        RECT  187.536 0 187.56 0.084 ;
    END
  END c_i[352]
  PIN c_i[353]
    DIRECTION INPUT ;
    USE SIGNAL ;
    PORT
      LAYER M5 ;
        RECT  187.68 0 187.704 0.084 ;
    END
  END c_i[353]
  PIN c_i[354]
    DIRECTION INPUT ;
    USE SIGNAL ;
    PORT
      LAYER M5 ;
        RECT  187.824 0 187.848 0.084 ;
    END
  END c_i[354]
  PIN c_i[355]
    DIRECTION INPUT ;
    USE SIGNAL ;
    PORT
      LAYER M5 ;
        RECT  187.968 0 187.992 0.084 ;
    END
  END c_i[355]
  PIN c_i[356]
    DIRECTION INPUT ;
    USE SIGNAL ;
    PORT
      LAYER M5 ;
        RECT  188.112 0 188.136 0.084 ;
    END
  END c_i[356]
  PIN c_i[357]
    DIRECTION INPUT ;
    USE SIGNAL ;
    PORT
      LAYER M5 ;
        RECT  188.256 0 188.28 0.084 ;
    END
  END c_i[357]
  PIN c_i[358]
    DIRECTION INPUT ;
    USE SIGNAL ;
    PORT
      LAYER M5 ;
        RECT  188.4 0 188.424 0.084 ;
    END
  END c_i[358]
  PIN c_i[359]
    DIRECTION INPUT ;
    USE SIGNAL ;
    PORT
      LAYER M5 ;
        RECT  188.544 0 188.568 0.084 ;
    END
  END c_i[359]
  PIN c_i[35]
    DIRECTION INPUT ;
    USE SIGNAL ;
    PORT
      LAYER M5 ;
        RECT  141.888 0 141.912 0.084 ;
    END
  END c_i[35]
  PIN c_i[360]
    DIRECTION INPUT ;
    USE SIGNAL ;
    PORT
      LAYER M5 ;
        RECT  188.688 0 188.712 0.084 ;
    END
  END c_i[360]
  PIN c_i[361]
    DIRECTION INPUT ;
    USE SIGNAL ;
    PORT
      LAYER M5 ;
        RECT  188.832 0 188.856 0.084 ;
    END
  END c_i[361]
  PIN c_i[362]
    DIRECTION INPUT ;
    USE SIGNAL ;
    PORT
      LAYER M5 ;
        RECT  188.976 0 189 0.084 ;
    END
  END c_i[362]
  PIN c_i[363]
    DIRECTION INPUT ;
    USE SIGNAL ;
    PORT
      LAYER M5 ;
        RECT  189.12 0 189.144 0.084 ;
    END
  END c_i[363]
  PIN c_i[364]
    DIRECTION INPUT ;
    USE SIGNAL ;
    PORT
      LAYER M5 ;
        RECT  189.264 0 189.288 0.084 ;
    END
  END c_i[364]
  PIN c_i[365]
    DIRECTION INPUT ;
    USE SIGNAL ;
    PORT
      LAYER M5 ;
        RECT  189.408 0 189.432 0.084 ;
    END
  END c_i[365]
  PIN c_i[366]
    DIRECTION INPUT ;
    USE SIGNAL ;
    PORT
      LAYER M5 ;
        RECT  189.552 0 189.576 0.084 ;
    END
  END c_i[366]
  PIN c_i[367]
    DIRECTION INPUT ;
    USE SIGNAL ;
    PORT
      LAYER M5 ;
        RECT  189.696 0 189.72 0.084 ;
    END
  END c_i[367]
  PIN c_i[368]
    DIRECTION INPUT ;
    USE SIGNAL ;
    PORT
      LAYER M5 ;
        RECT  189.84 0 189.864 0.084 ;
    END
  END c_i[368]
  PIN c_i[369]
    DIRECTION INPUT ;
    USE SIGNAL ;
    PORT
      LAYER M5 ;
        RECT  189.984 0 190.008 0.084 ;
    END
  END c_i[369]
  PIN c_i[36]
    DIRECTION INPUT ;
    USE SIGNAL ;
    PORT
      LAYER M5 ;
        RECT  142.032 0 142.056 0.084 ;
    END
  END c_i[36]
  PIN c_i[370]
    DIRECTION INPUT ;
    USE SIGNAL ;
    PORT
      LAYER M5 ;
        RECT  190.128 0 190.152 0.084 ;
    END
  END c_i[370]
  PIN c_i[371]
    DIRECTION INPUT ;
    USE SIGNAL ;
    PORT
      LAYER M5 ;
        RECT  190.272 0 190.296 0.084 ;
    END
  END c_i[371]
  PIN c_i[372]
    DIRECTION INPUT ;
    USE SIGNAL ;
    PORT
      LAYER M5 ;
        RECT  190.416 0 190.44 0.084 ;
    END
  END c_i[372]
  PIN c_i[373]
    DIRECTION INPUT ;
    USE SIGNAL ;
    PORT
      LAYER M5 ;
        RECT  190.56 0 190.584 0.084 ;
    END
  END c_i[373]
  PIN c_i[374]
    DIRECTION INPUT ;
    USE SIGNAL ;
    PORT
      LAYER M5 ;
        RECT  190.704 0 190.728 0.084 ;
    END
  END c_i[374]
  PIN c_i[375]
    DIRECTION INPUT ;
    USE SIGNAL ;
    PORT
      LAYER M5 ;
        RECT  190.848 0 190.872 0.084 ;
    END
  END c_i[375]
  PIN c_i[376]
    DIRECTION INPUT ;
    USE SIGNAL ;
    PORT
      LAYER M5 ;
        RECT  190.992 0 191.016 0.084 ;
    END
  END c_i[376]
  PIN c_i[377]
    DIRECTION INPUT ;
    USE SIGNAL ;
    PORT
      LAYER M5 ;
        RECT  191.136 0 191.16 0.084 ;
    END
  END c_i[377]
  PIN c_i[378]
    DIRECTION INPUT ;
    USE SIGNAL ;
    PORT
      LAYER M5 ;
        RECT  191.28 0 191.304 0.084 ;
    END
  END c_i[378]
  PIN c_i[379]
    DIRECTION INPUT ;
    USE SIGNAL ;
    PORT
      LAYER M5 ;
        RECT  191.424 0 191.448 0.084 ;
    END
  END c_i[379]
  PIN c_i[37]
    DIRECTION INPUT ;
    USE SIGNAL ;
    PORT
      LAYER M5 ;
        RECT  142.176 0 142.2 0.084 ;
    END
  END c_i[37]
  PIN c_i[380]
    DIRECTION INPUT ;
    USE SIGNAL ;
    PORT
      LAYER M5 ;
        RECT  191.568 0 191.592 0.084 ;
    END
  END c_i[380]
  PIN c_i[381]
    DIRECTION INPUT ;
    USE SIGNAL ;
    PORT
      LAYER M5 ;
        RECT  191.712 0 191.736 0.084 ;
    END
  END c_i[381]
  PIN c_i[382]
    DIRECTION INPUT ;
    USE SIGNAL ;
    PORT
      LAYER M5 ;
        RECT  191.856 0 191.88 0.084 ;
    END
  END c_i[382]
  PIN c_i[383]
    DIRECTION INPUT ;
    USE SIGNAL ;
    PORT
      LAYER M5 ;
        RECT  192 0 192.024 0.084 ;
    END
  END c_i[383]
  PIN c_i[384]
    DIRECTION INPUT ;
    USE SIGNAL ;
    PORT
      LAYER M5 ;
        RECT  192.144 0 192.168 0.084 ;
    END
  END c_i[384]
  PIN c_i[385]
    DIRECTION INPUT ;
    USE SIGNAL ;
    PORT
      LAYER M5 ;
        RECT  192.288 0 192.312 0.084 ;
    END
  END c_i[385]
  PIN c_i[386]
    DIRECTION INPUT ;
    USE SIGNAL ;
    PORT
      LAYER M5 ;
        RECT  192.432 0 192.456 0.084 ;
    END
  END c_i[386]
  PIN c_i[387]
    DIRECTION INPUT ;
    USE SIGNAL ;
    PORT
      LAYER M5 ;
        RECT  192.576 0 192.6 0.084 ;
    END
  END c_i[387]
  PIN c_i[388]
    DIRECTION INPUT ;
    USE SIGNAL ;
    PORT
      LAYER M5 ;
        RECT  192.72 0 192.744 0.084 ;
    END
  END c_i[388]
  PIN c_i[389]
    DIRECTION INPUT ;
    USE SIGNAL ;
    PORT
      LAYER M5 ;
        RECT  192.864 0 192.888 0.084 ;
    END
  END c_i[389]
  PIN c_i[38]
    DIRECTION INPUT ;
    USE SIGNAL ;
    PORT
      LAYER M5 ;
        RECT  142.32 0 142.344 0.084 ;
    END
  END c_i[38]
  PIN c_i[390]
    DIRECTION INPUT ;
    USE SIGNAL ;
    PORT
      LAYER M5 ;
        RECT  193.008 0 193.032 0.084 ;
    END
  END c_i[390]
  PIN c_i[391]
    DIRECTION INPUT ;
    USE SIGNAL ;
    PORT
      LAYER M5 ;
        RECT  193.152 0 193.176 0.084 ;
    END
  END c_i[391]
  PIN c_i[392]
    DIRECTION INPUT ;
    USE SIGNAL ;
    PORT
      LAYER M5 ;
        RECT  193.296 0 193.32 0.084 ;
    END
  END c_i[392]
  PIN c_i[393]
    DIRECTION INPUT ;
    USE SIGNAL ;
    PORT
      LAYER M5 ;
        RECT  193.44 0 193.464 0.084 ;
    END
  END c_i[393]
  PIN c_i[394]
    DIRECTION INPUT ;
    USE SIGNAL ;
    PORT
      LAYER M5 ;
        RECT  193.584 0 193.608 0.084 ;
    END
  END c_i[394]
  PIN c_i[395]
    DIRECTION INPUT ;
    USE SIGNAL ;
    PORT
      LAYER M5 ;
        RECT  193.728 0 193.752 0.084 ;
    END
  END c_i[395]
  PIN c_i[396]
    DIRECTION INPUT ;
    USE SIGNAL ;
    PORT
      LAYER M5 ;
        RECT  193.872 0 193.896 0.084 ;
    END
  END c_i[396]
  PIN c_i[397]
    DIRECTION INPUT ;
    USE SIGNAL ;
    PORT
      LAYER M5 ;
        RECT  194.016 0 194.04 0.084 ;
    END
  END c_i[397]
  PIN c_i[398]
    DIRECTION INPUT ;
    USE SIGNAL ;
    PORT
      LAYER M5 ;
        RECT  194.16 0 194.184 0.084 ;
    END
  END c_i[398]
  PIN c_i[399]
    DIRECTION INPUT ;
    USE SIGNAL ;
    PORT
      LAYER M5 ;
        RECT  194.304 0 194.328 0.084 ;
    END
  END c_i[399]
  PIN c_i[39]
    DIRECTION INPUT ;
    USE SIGNAL ;
    PORT
      LAYER M5 ;
        RECT  142.464 0 142.488 0.084 ;
    END
  END c_i[39]
  PIN c_i[3]
    DIRECTION INPUT ;
    USE SIGNAL ;
    PORT
      LAYER M5 ;
        RECT  137.28 0 137.304 0.084 ;
    END
  END c_i[3]
  PIN c_i[400]
    DIRECTION INPUT ;
    USE SIGNAL ;
    PORT
      LAYER M5 ;
        RECT  194.448 0 194.472 0.084 ;
    END
  END c_i[400]
  PIN c_i[401]
    DIRECTION INPUT ;
    USE SIGNAL ;
    PORT
      LAYER M5 ;
        RECT  194.592 0 194.616 0.084 ;
    END
  END c_i[401]
  PIN c_i[402]
    DIRECTION INPUT ;
    USE SIGNAL ;
    PORT
      LAYER M5 ;
        RECT  194.736 0 194.76 0.084 ;
    END
  END c_i[402]
  PIN c_i[403]
    DIRECTION INPUT ;
    USE SIGNAL ;
    PORT
      LAYER M5 ;
        RECT  194.88 0 194.904 0.084 ;
    END
  END c_i[403]
  PIN c_i[404]
    DIRECTION INPUT ;
    USE SIGNAL ;
    PORT
      LAYER M5 ;
        RECT  195.024 0 195.048 0.084 ;
    END
  END c_i[404]
  PIN c_i[405]
    DIRECTION INPUT ;
    USE SIGNAL ;
    PORT
      LAYER M5 ;
        RECT  195.168 0 195.192 0.084 ;
    END
  END c_i[405]
  PIN c_i[406]
    DIRECTION INPUT ;
    USE SIGNAL ;
    PORT
      LAYER M5 ;
        RECT  195.312 0 195.336 0.084 ;
    END
  END c_i[406]
  PIN c_i[407]
    DIRECTION INPUT ;
    USE SIGNAL ;
    PORT
      LAYER M5 ;
        RECT  195.456 0 195.48 0.084 ;
    END
  END c_i[407]
  PIN c_i[408]
    DIRECTION INPUT ;
    USE SIGNAL ;
    PORT
      LAYER M5 ;
        RECT  195.6 0 195.624 0.084 ;
    END
  END c_i[408]
  PIN c_i[409]
    DIRECTION INPUT ;
    USE SIGNAL ;
    PORT
      LAYER M5 ;
        RECT  195.744 0 195.768 0.084 ;
    END
  END c_i[409]
  PIN c_i[40]
    DIRECTION INPUT ;
    USE SIGNAL ;
    PORT
      LAYER M5 ;
        RECT  142.608 0 142.632 0.084 ;
    END
  END c_i[40]
  PIN c_i[410]
    DIRECTION INPUT ;
    USE SIGNAL ;
    PORT
      LAYER M5 ;
        RECT  195.888 0 195.912 0.084 ;
    END
  END c_i[410]
  PIN c_i[411]
    DIRECTION INPUT ;
    USE SIGNAL ;
    PORT
      LAYER M5 ;
        RECT  196.032 0 196.056 0.084 ;
    END
  END c_i[411]
  PIN c_i[412]
    DIRECTION INPUT ;
    USE SIGNAL ;
    PORT
      LAYER M5 ;
        RECT  196.176 0 196.2 0.084 ;
    END
  END c_i[412]
  PIN c_i[413]
    DIRECTION INPUT ;
    USE SIGNAL ;
    PORT
      LAYER M5 ;
        RECT  196.32 0 196.344 0.084 ;
    END
  END c_i[413]
  PIN c_i[414]
    DIRECTION INPUT ;
    USE SIGNAL ;
    PORT
      LAYER M5 ;
        RECT  196.464 0 196.488 0.084 ;
    END
  END c_i[414]
  PIN c_i[415]
    DIRECTION INPUT ;
    USE SIGNAL ;
    PORT
      LAYER M5 ;
        RECT  196.608 0 196.632 0.084 ;
    END
  END c_i[415]
  PIN c_i[416]
    DIRECTION INPUT ;
    USE SIGNAL ;
    PORT
      LAYER M5 ;
        RECT  196.752 0 196.776 0.084 ;
    END
  END c_i[416]
  PIN c_i[417]
    DIRECTION INPUT ;
    USE SIGNAL ;
    PORT
      LAYER M5 ;
        RECT  196.896 0 196.92 0.084 ;
    END
  END c_i[417]
  PIN c_i[418]
    DIRECTION INPUT ;
    USE SIGNAL ;
    PORT
      LAYER M5 ;
        RECT  197.04 0 197.064 0.084 ;
    END
  END c_i[418]
  PIN c_i[419]
    DIRECTION INPUT ;
    USE SIGNAL ;
    PORT
      LAYER M5 ;
        RECT  197.184 0 197.208 0.084 ;
    END
  END c_i[419]
  PIN c_i[41]
    DIRECTION INPUT ;
    USE SIGNAL ;
    PORT
      LAYER M5 ;
        RECT  142.752 0 142.776 0.084 ;
    END
  END c_i[41]
  PIN c_i[420]
    DIRECTION INPUT ;
    USE SIGNAL ;
    PORT
      LAYER M5 ;
        RECT  197.328 0 197.352 0.084 ;
    END
  END c_i[420]
  PIN c_i[421]
    DIRECTION INPUT ;
    USE SIGNAL ;
    PORT
      LAYER M5 ;
        RECT  197.472 0 197.496 0.084 ;
    END
  END c_i[421]
  PIN c_i[422]
    DIRECTION INPUT ;
    USE SIGNAL ;
    PORT
      LAYER M5 ;
        RECT  197.616 0 197.64 0.084 ;
    END
  END c_i[422]
  PIN c_i[423]
    DIRECTION INPUT ;
    USE SIGNAL ;
    PORT
      LAYER M5 ;
        RECT  197.76 0 197.784 0.084 ;
    END
  END c_i[423]
  PIN c_i[424]
    DIRECTION INPUT ;
    USE SIGNAL ;
    PORT
      LAYER M5 ;
        RECT  197.904 0 197.928 0.084 ;
    END
  END c_i[424]
  PIN c_i[425]
    DIRECTION INPUT ;
    USE SIGNAL ;
    PORT
      LAYER M5 ;
        RECT  198.048 0 198.072 0.084 ;
    END
  END c_i[425]
  PIN c_i[426]
    DIRECTION INPUT ;
    USE SIGNAL ;
    PORT
      LAYER M5 ;
        RECT  198.192 0 198.216 0.084 ;
    END
  END c_i[426]
  PIN c_i[427]
    DIRECTION INPUT ;
    USE SIGNAL ;
    PORT
      LAYER M5 ;
        RECT  198.336 0 198.36 0.084 ;
    END
  END c_i[427]
  PIN c_i[428]
    DIRECTION INPUT ;
    USE SIGNAL ;
    PORT
      LAYER M5 ;
        RECT  198.48 0 198.504 0.084 ;
    END
  END c_i[428]
  PIN c_i[429]
    DIRECTION INPUT ;
    USE SIGNAL ;
    PORT
      LAYER M5 ;
        RECT  198.624 0 198.648 0.084 ;
    END
  END c_i[429]
  PIN c_i[42]
    DIRECTION INPUT ;
    USE SIGNAL ;
    PORT
      LAYER M5 ;
        RECT  142.896 0 142.92 0.084 ;
    END
  END c_i[42]
  PIN c_i[430]
    DIRECTION INPUT ;
    USE SIGNAL ;
    PORT
      LAYER M5 ;
        RECT  198.768 0 198.792 0.084 ;
    END
  END c_i[430]
  PIN c_i[431]
    DIRECTION INPUT ;
    USE SIGNAL ;
    PORT
      LAYER M5 ;
        RECT  198.912 0 198.936 0.084 ;
    END
  END c_i[431]
  PIN c_i[432]
    DIRECTION INPUT ;
    USE SIGNAL ;
    PORT
      LAYER M5 ;
        RECT  199.056 0 199.08 0.084 ;
    END
  END c_i[432]
  PIN c_i[433]
    DIRECTION INPUT ;
    USE SIGNAL ;
    PORT
      LAYER M5 ;
        RECT  199.2 0 199.224 0.084 ;
    END
  END c_i[433]
  PIN c_i[434]
    DIRECTION INPUT ;
    USE SIGNAL ;
    PORT
      LAYER M5 ;
        RECT  199.344 0 199.368 0.084 ;
    END
  END c_i[434]
  PIN c_i[435]
    DIRECTION INPUT ;
    USE SIGNAL ;
    PORT
      LAYER M5 ;
        RECT  199.488 0 199.512 0.084 ;
    END
  END c_i[435]
  PIN c_i[436]
    DIRECTION INPUT ;
    USE SIGNAL ;
    PORT
      LAYER M5 ;
        RECT  199.632 0 199.656 0.084 ;
    END
  END c_i[436]
  PIN c_i[437]
    DIRECTION INPUT ;
    USE SIGNAL ;
    PORT
      LAYER M5 ;
        RECT  199.776 0 199.8 0.084 ;
    END
  END c_i[437]
  PIN c_i[438]
    DIRECTION INPUT ;
    USE SIGNAL ;
    PORT
      LAYER M5 ;
        RECT  199.92 0 199.944 0.084 ;
    END
  END c_i[438]
  PIN c_i[439]
    DIRECTION INPUT ;
    USE SIGNAL ;
    PORT
      LAYER M5 ;
        RECT  200.064 0 200.088 0.084 ;
    END
  END c_i[439]
  PIN c_i[43]
    DIRECTION INPUT ;
    USE SIGNAL ;
    PORT
      LAYER M5 ;
        RECT  143.04 0 143.064 0.084 ;
    END
  END c_i[43]
  PIN c_i[440]
    DIRECTION INPUT ;
    USE SIGNAL ;
    PORT
      LAYER M5 ;
        RECT  200.208 0 200.232 0.084 ;
    END
  END c_i[440]
  PIN c_i[441]
    DIRECTION INPUT ;
    USE SIGNAL ;
    PORT
      LAYER M5 ;
        RECT  200.352 0 200.376 0.084 ;
    END
  END c_i[441]
  PIN c_i[442]
    DIRECTION INPUT ;
    USE SIGNAL ;
    PORT
      LAYER M5 ;
        RECT  200.496 0 200.52 0.084 ;
    END
  END c_i[442]
  PIN c_i[443]
    DIRECTION INPUT ;
    USE SIGNAL ;
    PORT
      LAYER M5 ;
        RECT  200.64 0 200.664 0.084 ;
    END
  END c_i[443]
  PIN c_i[444]
    DIRECTION INPUT ;
    USE SIGNAL ;
    PORT
      LAYER M5 ;
        RECT  200.784 0 200.808 0.084 ;
    END
  END c_i[444]
  PIN c_i[445]
    DIRECTION INPUT ;
    USE SIGNAL ;
    PORT
      LAYER M5 ;
        RECT  200.928 0 200.952 0.084 ;
    END
  END c_i[445]
  PIN c_i[446]
    DIRECTION INPUT ;
    USE SIGNAL ;
    PORT
      LAYER M5 ;
        RECT  201.072 0 201.096 0.084 ;
    END
  END c_i[446]
  PIN c_i[447]
    DIRECTION INPUT ;
    USE SIGNAL ;
    PORT
      LAYER M5 ;
        RECT  201.216 0 201.24 0.084 ;
    END
  END c_i[447]
  PIN c_i[448]
    DIRECTION INPUT ;
    USE SIGNAL ;
    PORT
      LAYER M5 ;
        RECT  201.36 0 201.384 0.084 ;
    END
  END c_i[448]
  PIN c_i[449]
    DIRECTION INPUT ;
    USE SIGNAL ;
    PORT
      LAYER M5 ;
        RECT  201.504 0 201.528 0.084 ;
    END
  END c_i[449]
  PIN c_i[44]
    DIRECTION INPUT ;
    USE SIGNAL ;
    PORT
      LAYER M5 ;
        RECT  143.184 0 143.208 0.084 ;
    END
  END c_i[44]
  PIN c_i[450]
    DIRECTION INPUT ;
    USE SIGNAL ;
    PORT
      LAYER M5 ;
        RECT  201.648 0 201.672 0.084 ;
    END
  END c_i[450]
  PIN c_i[451]
    DIRECTION INPUT ;
    USE SIGNAL ;
    PORT
      LAYER M5 ;
        RECT  201.792 0 201.816 0.084 ;
    END
  END c_i[451]
  PIN c_i[452]
    DIRECTION INPUT ;
    USE SIGNAL ;
    PORT
      LAYER M5 ;
        RECT  201.936 0 201.96 0.084 ;
    END
  END c_i[452]
  PIN c_i[453]
    DIRECTION INPUT ;
    USE SIGNAL ;
    PORT
      LAYER M5 ;
        RECT  202.08 0 202.104 0.084 ;
    END
  END c_i[453]
  PIN c_i[454]
    DIRECTION INPUT ;
    USE SIGNAL ;
    PORT
      LAYER M5 ;
        RECT  202.224 0 202.248 0.084 ;
    END
  END c_i[454]
  PIN c_i[455]
    DIRECTION INPUT ;
    USE SIGNAL ;
    PORT
      LAYER M5 ;
        RECT  202.368 0 202.392 0.084 ;
    END
  END c_i[455]
  PIN c_i[456]
    DIRECTION INPUT ;
    USE SIGNAL ;
    PORT
      LAYER M5 ;
        RECT  202.512 0 202.536 0.084 ;
    END
  END c_i[456]
  PIN c_i[457]
    DIRECTION INPUT ;
    USE SIGNAL ;
    PORT
      LAYER M5 ;
        RECT  202.656 0 202.68 0.084 ;
    END
  END c_i[457]
  PIN c_i[458]
    DIRECTION INPUT ;
    USE SIGNAL ;
    PORT
      LAYER M5 ;
        RECT  202.8 0 202.824 0.084 ;
    END
  END c_i[458]
  PIN c_i[459]
    DIRECTION INPUT ;
    USE SIGNAL ;
    PORT
      LAYER M5 ;
        RECT  202.944 0 202.968 0.084 ;
    END
  END c_i[459]
  PIN c_i[45]
    DIRECTION INPUT ;
    USE SIGNAL ;
    PORT
      LAYER M5 ;
        RECT  143.328 0 143.352 0.084 ;
    END
  END c_i[45]
  PIN c_i[460]
    DIRECTION INPUT ;
    USE SIGNAL ;
    PORT
      LAYER M5 ;
        RECT  203.088 0 203.112 0.084 ;
    END
  END c_i[460]
  PIN c_i[461]
    DIRECTION INPUT ;
    USE SIGNAL ;
    PORT
      LAYER M5 ;
        RECT  203.232 0 203.256 0.084 ;
    END
  END c_i[461]
  PIN c_i[462]
    DIRECTION INPUT ;
    USE SIGNAL ;
    PORT
      LAYER M5 ;
        RECT  203.376 0 203.4 0.084 ;
    END
  END c_i[462]
  PIN c_i[463]
    DIRECTION INPUT ;
    USE SIGNAL ;
    PORT
      LAYER M5 ;
        RECT  203.52 0 203.544 0.084 ;
    END
  END c_i[463]
  PIN c_i[464]
    DIRECTION INPUT ;
    USE SIGNAL ;
    PORT
      LAYER M5 ;
        RECT  203.664 0 203.688 0.084 ;
    END
  END c_i[464]
  PIN c_i[465]
    DIRECTION INPUT ;
    USE SIGNAL ;
    PORT
      LAYER M5 ;
        RECT  203.808 0 203.832 0.084 ;
    END
  END c_i[465]
  PIN c_i[466]
    DIRECTION INPUT ;
    USE SIGNAL ;
    PORT
      LAYER M5 ;
        RECT  203.952 0 203.976 0.084 ;
    END
  END c_i[466]
  PIN c_i[467]
    DIRECTION INPUT ;
    USE SIGNAL ;
    PORT
      LAYER M5 ;
        RECT  204.096 0 204.12 0.084 ;
    END
  END c_i[467]
  PIN c_i[468]
    DIRECTION INPUT ;
    USE SIGNAL ;
    PORT
      LAYER M5 ;
        RECT  204.24 0 204.264 0.084 ;
    END
  END c_i[468]
  PIN c_i[469]
    DIRECTION INPUT ;
    USE SIGNAL ;
    PORT
      LAYER M5 ;
        RECT  204.384 0 204.408 0.084 ;
    END
  END c_i[469]
  PIN c_i[46]
    DIRECTION INPUT ;
    USE SIGNAL ;
    PORT
      LAYER M5 ;
        RECT  143.472 0 143.496 0.084 ;
    END
  END c_i[46]
  PIN c_i[470]
    DIRECTION INPUT ;
    USE SIGNAL ;
    PORT
      LAYER M5 ;
        RECT  204.528 0 204.552 0.084 ;
    END
  END c_i[470]
  PIN c_i[471]
    DIRECTION INPUT ;
    USE SIGNAL ;
    PORT
      LAYER M5 ;
        RECT  204.672 0 204.696 0.084 ;
    END
  END c_i[471]
  PIN c_i[472]
    DIRECTION INPUT ;
    USE SIGNAL ;
    PORT
      LAYER M5 ;
        RECT  204.816 0 204.84 0.084 ;
    END
  END c_i[472]
  PIN c_i[473]
    DIRECTION INPUT ;
    USE SIGNAL ;
    PORT
      LAYER M5 ;
        RECT  204.96 0 204.984 0.084 ;
    END
  END c_i[473]
  PIN c_i[474]
    DIRECTION INPUT ;
    USE SIGNAL ;
    PORT
      LAYER M5 ;
        RECT  205.104 0 205.128 0.084 ;
    END
  END c_i[474]
  PIN c_i[475]
    DIRECTION INPUT ;
    USE SIGNAL ;
    PORT
      LAYER M5 ;
        RECT  205.248 0 205.272 0.084 ;
    END
  END c_i[475]
  PIN c_i[476]
    DIRECTION INPUT ;
    USE SIGNAL ;
    PORT
      LAYER M5 ;
        RECT  205.392 0 205.416 0.084 ;
    END
  END c_i[476]
  PIN c_i[477]
    DIRECTION INPUT ;
    USE SIGNAL ;
    PORT
      LAYER M5 ;
        RECT  205.536 0 205.56 0.084 ;
    END
  END c_i[477]
  PIN c_i[478]
    DIRECTION INPUT ;
    USE SIGNAL ;
    PORT
      LAYER M5 ;
        RECT  205.68 0 205.704 0.084 ;
    END
  END c_i[478]
  PIN c_i[479]
    DIRECTION INPUT ;
    USE SIGNAL ;
    PORT
      LAYER M5 ;
        RECT  205.824 0 205.848 0.084 ;
    END
  END c_i[479]
  PIN c_i[47]
    DIRECTION INPUT ;
    USE SIGNAL ;
    PORT
      LAYER M5 ;
        RECT  143.616 0 143.64 0.084 ;
    END
  END c_i[47]
  PIN c_i[480]
    DIRECTION INPUT ;
    USE SIGNAL ;
    PORT
      LAYER M5 ;
        RECT  205.968 0 205.992 0.084 ;
    END
  END c_i[480]
  PIN c_i[481]
    DIRECTION INPUT ;
    USE SIGNAL ;
    PORT
      LAYER M5 ;
        RECT  206.112 0 206.136 0.084 ;
    END
  END c_i[481]
  PIN c_i[482]
    DIRECTION INPUT ;
    USE SIGNAL ;
    PORT
      LAYER M5 ;
        RECT  206.256 0 206.28 0.084 ;
    END
  END c_i[482]
  PIN c_i[483]
    DIRECTION INPUT ;
    USE SIGNAL ;
    PORT
      LAYER M5 ;
        RECT  206.4 0 206.424 0.084 ;
    END
  END c_i[483]
  PIN c_i[484]
    DIRECTION INPUT ;
    USE SIGNAL ;
    PORT
      LAYER M5 ;
        RECT  206.544 0 206.568 0.084 ;
    END
  END c_i[484]
  PIN c_i[485]
    DIRECTION INPUT ;
    USE SIGNAL ;
    PORT
      LAYER M5 ;
        RECT  206.688 0 206.712 0.084 ;
    END
  END c_i[485]
  PIN c_i[486]
    DIRECTION INPUT ;
    USE SIGNAL ;
    PORT
      LAYER M5 ;
        RECT  206.832 0 206.856 0.084 ;
    END
  END c_i[486]
  PIN c_i[487]
    DIRECTION INPUT ;
    USE SIGNAL ;
    PORT
      LAYER M5 ;
        RECT  206.976 0 207 0.084 ;
    END
  END c_i[487]
  PIN c_i[488]
    DIRECTION INPUT ;
    USE SIGNAL ;
    PORT
      LAYER M5 ;
        RECT  207.12 0 207.144 0.084 ;
    END
  END c_i[488]
  PIN c_i[489]
    DIRECTION INPUT ;
    USE SIGNAL ;
    PORT
      LAYER M5 ;
        RECT  207.264 0 207.288 0.084 ;
    END
  END c_i[489]
  PIN c_i[48]
    DIRECTION INPUT ;
    USE SIGNAL ;
    PORT
      LAYER M5 ;
        RECT  143.76 0 143.784 0.084 ;
    END
  END c_i[48]
  PIN c_i[490]
    DIRECTION INPUT ;
    USE SIGNAL ;
    PORT
      LAYER M5 ;
        RECT  207.408 0 207.432 0.084 ;
    END
  END c_i[490]
  PIN c_i[491]
    DIRECTION INPUT ;
    USE SIGNAL ;
    PORT
      LAYER M5 ;
        RECT  207.552 0 207.576 0.084 ;
    END
  END c_i[491]
  PIN c_i[492]
    DIRECTION INPUT ;
    USE SIGNAL ;
    PORT
      LAYER M5 ;
        RECT  207.696 0 207.72 0.084 ;
    END
  END c_i[492]
  PIN c_i[493]
    DIRECTION INPUT ;
    USE SIGNAL ;
    PORT
      LAYER M5 ;
        RECT  207.84 0 207.864 0.084 ;
    END
  END c_i[493]
  PIN c_i[494]
    DIRECTION INPUT ;
    USE SIGNAL ;
    PORT
      LAYER M5 ;
        RECT  207.984 0 208.008 0.084 ;
    END
  END c_i[494]
  PIN c_i[495]
    DIRECTION INPUT ;
    USE SIGNAL ;
    PORT
      LAYER M5 ;
        RECT  208.128 0 208.152 0.084 ;
    END
  END c_i[495]
  PIN c_i[496]
    DIRECTION INPUT ;
    USE SIGNAL ;
    PORT
      LAYER M5 ;
        RECT  208.272 0 208.296 0.084 ;
    END
  END c_i[496]
  PIN c_i[497]
    DIRECTION INPUT ;
    USE SIGNAL ;
    PORT
      LAYER M5 ;
        RECT  208.416 0 208.44 0.084 ;
    END
  END c_i[497]
  PIN c_i[498]
    DIRECTION INPUT ;
    USE SIGNAL ;
    PORT
      LAYER M5 ;
        RECT  208.56 0 208.584 0.084 ;
    END
  END c_i[498]
  PIN c_i[499]
    DIRECTION INPUT ;
    USE SIGNAL ;
    PORT
      LAYER M5 ;
        RECT  208.704 0 208.728 0.084 ;
    END
  END c_i[499]
  PIN c_i[49]
    DIRECTION INPUT ;
    USE SIGNAL ;
    PORT
      LAYER M5 ;
        RECT  143.904 0 143.928 0.084 ;
    END
  END c_i[49]
  PIN c_i[4]
    DIRECTION INPUT ;
    USE SIGNAL ;
    PORT
      LAYER M5 ;
        RECT  137.424 0 137.448 0.084 ;
    END
  END c_i[4]
  PIN c_i[500]
    DIRECTION INPUT ;
    USE SIGNAL ;
    PORT
      LAYER M5 ;
        RECT  208.848 0 208.872 0.084 ;
    END
  END c_i[500]
  PIN c_i[501]
    DIRECTION INPUT ;
    USE SIGNAL ;
    PORT
      LAYER M5 ;
        RECT  208.992 0 209.016 0.084 ;
    END
  END c_i[501]
  PIN c_i[502]
    DIRECTION INPUT ;
    USE SIGNAL ;
    PORT
      LAYER M5 ;
        RECT  209.136 0 209.16 0.084 ;
    END
  END c_i[502]
  PIN c_i[503]
    DIRECTION INPUT ;
    USE SIGNAL ;
    PORT
      LAYER M5 ;
        RECT  209.28 0 209.304 0.084 ;
    END
  END c_i[503]
  PIN c_i[504]
    DIRECTION INPUT ;
    USE SIGNAL ;
    PORT
      LAYER M5 ;
        RECT  209.424 0 209.448 0.084 ;
    END
  END c_i[504]
  PIN c_i[505]
    DIRECTION INPUT ;
    USE SIGNAL ;
    PORT
      LAYER M5 ;
        RECT  209.568 0 209.592 0.084 ;
    END
  END c_i[505]
  PIN c_i[506]
    DIRECTION INPUT ;
    USE SIGNAL ;
    PORT
      LAYER M5 ;
        RECT  209.712 0 209.736 0.084 ;
    END
  END c_i[506]
  PIN c_i[507]
    DIRECTION INPUT ;
    USE SIGNAL ;
    PORT
      LAYER M5 ;
        RECT  209.856 0 209.88 0.084 ;
    END
  END c_i[507]
  PIN c_i[508]
    DIRECTION INPUT ;
    USE SIGNAL ;
    PORT
      LAYER M5 ;
        RECT  210 0 210.024 0.084 ;
    END
  END c_i[508]
  PIN c_i[509]
    DIRECTION INPUT ;
    USE SIGNAL ;
    PORT
      LAYER M5 ;
        RECT  210.144 0 210.168 0.084 ;
    END
  END c_i[509]
  PIN c_i[50]
    DIRECTION INPUT ;
    USE SIGNAL ;
    PORT
      LAYER M5 ;
        RECT  144.048 0 144.072 0.084 ;
    END
  END c_i[50]
  PIN c_i[510]
    DIRECTION INPUT ;
    USE SIGNAL ;
    PORT
      LAYER M5 ;
        RECT  210.288 0 210.312 0.084 ;
    END
  END c_i[510]
  PIN c_i[511]
    DIRECTION INPUT ;
    USE SIGNAL ;
    PORT
      LAYER M5 ;
        RECT  210.432 0 210.456 0.084 ;
    END
  END c_i[511]
  PIN c_i[512]
    DIRECTION INPUT ;
    USE SIGNAL ;
    PORT
      LAYER M5 ;
        RECT  210.576 0 210.6 0.084 ;
    END
  END c_i[512]
  PIN c_i[513]
    DIRECTION INPUT ;
    USE SIGNAL ;
    PORT
      LAYER M5 ;
        RECT  210.72 0 210.744 0.084 ;
    END
  END c_i[513]
  PIN c_i[514]
    DIRECTION INPUT ;
    USE SIGNAL ;
    PORT
      LAYER M5 ;
        RECT  210.864 0 210.888 0.084 ;
    END
  END c_i[514]
  PIN c_i[515]
    DIRECTION INPUT ;
    USE SIGNAL ;
    PORT
      LAYER M5 ;
        RECT  211.008 0 211.032 0.084 ;
    END
  END c_i[515]
  PIN c_i[516]
    DIRECTION INPUT ;
    USE SIGNAL ;
    PORT
      LAYER M5 ;
        RECT  211.152 0 211.176 0.084 ;
    END
  END c_i[516]
  PIN c_i[517]
    DIRECTION INPUT ;
    USE SIGNAL ;
    PORT
      LAYER M5 ;
        RECT  211.296 0 211.32 0.084 ;
    END
  END c_i[517]
  PIN c_i[518]
    DIRECTION INPUT ;
    USE SIGNAL ;
    PORT
      LAYER M5 ;
        RECT  211.44 0 211.464 0.084 ;
    END
  END c_i[518]
  PIN c_i[519]
    DIRECTION INPUT ;
    USE SIGNAL ;
    PORT
      LAYER M5 ;
        RECT  211.584 0 211.608 0.084 ;
    END
  END c_i[519]
  PIN c_i[51]
    DIRECTION INPUT ;
    USE SIGNAL ;
    PORT
      LAYER M5 ;
        RECT  144.192 0 144.216 0.084 ;
    END
  END c_i[51]
  PIN c_i[520]
    DIRECTION INPUT ;
    USE SIGNAL ;
    PORT
      LAYER M5 ;
        RECT  211.728 0 211.752 0.084 ;
    END
  END c_i[520]
  PIN c_i[521]
    DIRECTION INPUT ;
    USE SIGNAL ;
    PORT
      LAYER M5 ;
        RECT  211.872 0 211.896 0.084 ;
    END
  END c_i[521]
  PIN c_i[522]
    DIRECTION INPUT ;
    USE SIGNAL ;
    PORT
      LAYER M5 ;
        RECT  212.016 0 212.04 0.084 ;
    END
  END c_i[522]
  PIN c_i[523]
    DIRECTION INPUT ;
    USE SIGNAL ;
    PORT
      LAYER M5 ;
        RECT  212.16 0 212.184 0.084 ;
    END
  END c_i[523]
  PIN c_i[524]
    DIRECTION INPUT ;
    USE SIGNAL ;
    PORT
      LAYER M5 ;
        RECT  212.304 0 212.328 0.084 ;
    END
  END c_i[524]
  PIN c_i[525]
    DIRECTION INPUT ;
    USE SIGNAL ;
    PORT
      LAYER M5 ;
        RECT  212.448 0 212.472 0.084 ;
    END
  END c_i[525]
  PIN c_i[526]
    DIRECTION INPUT ;
    USE SIGNAL ;
    PORT
      LAYER M5 ;
        RECT  212.592 0 212.616 0.084 ;
    END
  END c_i[526]
  PIN c_i[527]
    DIRECTION INPUT ;
    USE SIGNAL ;
    PORT
      LAYER M5 ;
        RECT  212.736 0 212.76 0.084 ;
    END
  END c_i[527]
  PIN c_i[528]
    DIRECTION INPUT ;
    USE SIGNAL ;
    PORT
      LAYER M5 ;
        RECT  212.88 0 212.904 0.084 ;
    END
  END c_i[528]
  PIN c_i[529]
    DIRECTION INPUT ;
    USE SIGNAL ;
    PORT
      LAYER M5 ;
        RECT  213.024 0 213.048 0.084 ;
    END
  END c_i[529]
  PIN c_i[52]
    DIRECTION INPUT ;
    USE SIGNAL ;
    PORT
      LAYER M5 ;
        RECT  144.336 0 144.36 0.084 ;
    END
  END c_i[52]
  PIN c_i[530]
    DIRECTION INPUT ;
    USE SIGNAL ;
    PORT
      LAYER M5 ;
        RECT  213.168 0 213.192 0.084 ;
    END
  END c_i[530]
  PIN c_i[531]
    DIRECTION INPUT ;
    USE SIGNAL ;
    PORT
      LAYER M5 ;
        RECT  213.312 0 213.336 0.084 ;
    END
  END c_i[531]
  PIN c_i[532]
    DIRECTION INPUT ;
    USE SIGNAL ;
    PORT
      LAYER M5 ;
        RECT  213.456 0 213.48 0.084 ;
    END
  END c_i[532]
  PIN c_i[533]
    DIRECTION INPUT ;
    USE SIGNAL ;
    PORT
      LAYER M5 ;
        RECT  213.6 0 213.624 0.084 ;
    END
  END c_i[533]
  PIN c_i[534]
    DIRECTION INPUT ;
    USE SIGNAL ;
    PORT
      LAYER M5 ;
        RECT  213.744 0 213.768 0.084 ;
    END
  END c_i[534]
  PIN c_i[535]
    DIRECTION INPUT ;
    USE SIGNAL ;
    PORT
      LAYER M5 ;
        RECT  213.888 0 213.912 0.084 ;
    END
  END c_i[535]
  PIN c_i[536]
    DIRECTION INPUT ;
    USE SIGNAL ;
    PORT
      LAYER M5 ;
        RECT  214.032 0 214.056 0.084 ;
    END
  END c_i[536]
  PIN c_i[537]
    DIRECTION INPUT ;
    USE SIGNAL ;
    PORT
      LAYER M5 ;
        RECT  214.176 0 214.2 0.084 ;
    END
  END c_i[537]
  PIN c_i[538]
    DIRECTION INPUT ;
    USE SIGNAL ;
    PORT
      LAYER M5 ;
        RECT  214.32 0 214.344 0.084 ;
    END
  END c_i[538]
  PIN c_i[539]
    DIRECTION INPUT ;
    USE SIGNAL ;
    PORT
      LAYER M5 ;
        RECT  214.464 0 214.488 0.084 ;
    END
  END c_i[539]
  PIN c_i[53]
    DIRECTION INPUT ;
    USE SIGNAL ;
    PORT
      LAYER M5 ;
        RECT  144.48 0 144.504 0.084 ;
    END
  END c_i[53]
  PIN c_i[540]
    DIRECTION INPUT ;
    USE SIGNAL ;
    PORT
      LAYER M5 ;
        RECT  214.608 0 214.632 0.084 ;
    END
  END c_i[540]
  PIN c_i[541]
    DIRECTION INPUT ;
    USE SIGNAL ;
    PORT
      LAYER M5 ;
        RECT  214.752 0 214.776 0.084 ;
    END
  END c_i[541]
  PIN c_i[542]
    DIRECTION INPUT ;
    USE SIGNAL ;
    PORT
      LAYER M5 ;
        RECT  214.896 0 214.92 0.084 ;
    END
  END c_i[542]
  PIN c_i[543]
    DIRECTION INPUT ;
    USE SIGNAL ;
    PORT
      LAYER M5 ;
        RECT  215.04 0 215.064 0.084 ;
    END
  END c_i[543]
  PIN c_i[544]
    DIRECTION INPUT ;
    USE SIGNAL ;
    PORT
      LAYER M5 ;
        RECT  215.184 0 215.208 0.084 ;
    END
  END c_i[544]
  PIN c_i[545]
    DIRECTION INPUT ;
    USE SIGNAL ;
    PORT
      LAYER M5 ;
        RECT  215.328 0 215.352 0.084 ;
    END
  END c_i[545]
  PIN c_i[546]
    DIRECTION INPUT ;
    USE SIGNAL ;
    PORT
      LAYER M5 ;
        RECT  215.472 0 215.496 0.084 ;
    END
  END c_i[546]
  PIN c_i[547]
    DIRECTION INPUT ;
    USE SIGNAL ;
    PORT
      LAYER M5 ;
        RECT  215.616 0 215.64 0.084 ;
    END
  END c_i[547]
  PIN c_i[548]
    DIRECTION INPUT ;
    USE SIGNAL ;
    PORT
      LAYER M5 ;
        RECT  215.76 0 215.784 0.084 ;
    END
  END c_i[548]
  PIN c_i[549]
    DIRECTION INPUT ;
    USE SIGNAL ;
    PORT
      LAYER M5 ;
        RECT  215.904 0 215.928 0.084 ;
    END
  END c_i[549]
  PIN c_i[54]
    DIRECTION INPUT ;
    USE SIGNAL ;
    PORT
      LAYER M5 ;
        RECT  144.624 0 144.648 0.084 ;
    END
  END c_i[54]
  PIN c_i[550]
    DIRECTION INPUT ;
    USE SIGNAL ;
    PORT
      LAYER M5 ;
        RECT  216.048 0 216.072 0.084 ;
    END
  END c_i[550]
  PIN c_i[551]
    DIRECTION INPUT ;
    USE SIGNAL ;
    PORT
      LAYER M5 ;
        RECT  216.192 0 216.216 0.084 ;
    END
  END c_i[551]
  PIN c_i[552]
    DIRECTION INPUT ;
    USE SIGNAL ;
    PORT
      LAYER M5 ;
        RECT  216.336 0 216.36 0.084 ;
    END
  END c_i[552]
  PIN c_i[553]
    DIRECTION INPUT ;
    USE SIGNAL ;
    PORT
      LAYER M5 ;
        RECT  216.48 0 216.504 0.084 ;
    END
  END c_i[553]
  PIN c_i[554]
    DIRECTION INPUT ;
    USE SIGNAL ;
    PORT
      LAYER M5 ;
        RECT  216.624 0 216.648 0.084 ;
    END
  END c_i[554]
  PIN c_i[555]
    DIRECTION INPUT ;
    USE SIGNAL ;
    PORT
      LAYER M5 ;
        RECT  216.768 0 216.792 0.084 ;
    END
  END c_i[555]
  PIN c_i[556]
    DIRECTION INPUT ;
    USE SIGNAL ;
    PORT
      LAYER M5 ;
        RECT  216.912 0 216.936 0.084 ;
    END
  END c_i[556]
  PIN c_i[557]
    DIRECTION INPUT ;
    USE SIGNAL ;
    PORT
      LAYER M5 ;
        RECT  217.056 0 217.08 0.084 ;
    END
  END c_i[557]
  PIN c_i[558]
    DIRECTION INPUT ;
    USE SIGNAL ;
    PORT
      LAYER M5 ;
        RECT  217.2 0 217.224 0.084 ;
    END
  END c_i[558]
  PIN c_i[559]
    DIRECTION INPUT ;
    USE SIGNAL ;
    PORT
      LAYER M5 ;
        RECT  217.344 0 217.368 0.084 ;
    END
  END c_i[559]
  PIN c_i[55]
    DIRECTION INPUT ;
    USE SIGNAL ;
    PORT
      LAYER M5 ;
        RECT  144.768 0 144.792 0.084 ;
    END
  END c_i[55]
  PIN c_i[560]
    DIRECTION INPUT ;
    USE SIGNAL ;
    PORT
      LAYER M5 ;
        RECT  217.488 0 217.512 0.084 ;
    END
  END c_i[560]
  PIN c_i[561]
    DIRECTION INPUT ;
    USE SIGNAL ;
    PORT
      LAYER M5 ;
        RECT  217.632 0 217.656 0.084 ;
    END
  END c_i[561]
  PIN c_i[562]
    DIRECTION INPUT ;
    USE SIGNAL ;
    PORT
      LAYER M5 ;
        RECT  217.776 0 217.8 0.084 ;
    END
  END c_i[562]
  PIN c_i[563]
    DIRECTION INPUT ;
    USE SIGNAL ;
    PORT
      LAYER M5 ;
        RECT  217.92 0 217.944 0.084 ;
    END
  END c_i[563]
  PIN c_i[564]
    DIRECTION INPUT ;
    USE SIGNAL ;
    PORT
      LAYER M5 ;
        RECT  218.064 0 218.088 0.084 ;
    END
  END c_i[564]
  PIN c_i[565]
    DIRECTION INPUT ;
    USE SIGNAL ;
    PORT
      LAYER M5 ;
        RECT  218.208 0 218.232 0.084 ;
    END
  END c_i[565]
  PIN c_i[566]
    DIRECTION INPUT ;
    USE SIGNAL ;
    PORT
      LAYER M5 ;
        RECT  218.352 0 218.376 0.084 ;
    END
  END c_i[566]
  PIN c_i[567]
    DIRECTION INPUT ;
    USE SIGNAL ;
    PORT
      LAYER M5 ;
        RECT  218.496 0 218.52 0.084 ;
    END
  END c_i[567]
  PIN c_i[568]
    DIRECTION INPUT ;
    USE SIGNAL ;
    PORT
      LAYER M5 ;
        RECT  218.64 0 218.664 0.084 ;
    END
  END c_i[568]
  PIN c_i[569]
    DIRECTION INPUT ;
    USE SIGNAL ;
    PORT
      LAYER M5 ;
        RECT  218.784 0 218.808 0.084 ;
    END
  END c_i[569]
  PIN c_i[56]
    DIRECTION INPUT ;
    USE SIGNAL ;
    PORT
      LAYER M5 ;
        RECT  144.912 0 144.936 0.084 ;
    END
  END c_i[56]
  PIN c_i[570]
    DIRECTION INPUT ;
    USE SIGNAL ;
    PORT
      LAYER M5 ;
        RECT  218.928 0 218.952 0.084 ;
    END
  END c_i[570]
  PIN c_i[571]
    DIRECTION INPUT ;
    USE SIGNAL ;
    PORT
      LAYER M5 ;
        RECT  219.072 0 219.096 0.084 ;
    END
  END c_i[571]
  PIN c_i[572]
    DIRECTION INPUT ;
    USE SIGNAL ;
    PORT
      LAYER M5 ;
        RECT  219.216 0 219.24 0.084 ;
    END
  END c_i[572]
  PIN c_i[573]
    DIRECTION INPUT ;
    USE SIGNAL ;
    PORT
      LAYER M5 ;
        RECT  219.36 0 219.384 0.084 ;
    END
  END c_i[573]
  PIN c_i[574]
    DIRECTION INPUT ;
    USE SIGNAL ;
    PORT
      LAYER M5 ;
        RECT  219.504 0 219.528 0.084 ;
    END
  END c_i[574]
  PIN c_i[575]
    DIRECTION INPUT ;
    USE SIGNAL ;
    PORT
      LAYER M5 ;
        RECT  219.648 0 219.672 0.084 ;
    END
  END c_i[575]
  PIN c_i[576]
    DIRECTION INPUT ;
    USE SIGNAL ;
    PORT
      LAYER M5 ;
        RECT  219.792 0 219.816 0.084 ;
    END
  END c_i[576]
  PIN c_i[577]
    DIRECTION INPUT ;
    USE SIGNAL ;
    PORT
      LAYER M5 ;
        RECT  219.936 0 219.96 0.084 ;
    END
  END c_i[577]
  PIN c_i[578]
    DIRECTION INPUT ;
    USE SIGNAL ;
    PORT
      LAYER M5 ;
        RECT  220.08 0 220.104 0.084 ;
    END
  END c_i[578]
  PIN c_i[579]
    DIRECTION INPUT ;
    USE SIGNAL ;
    PORT
      LAYER M5 ;
        RECT  220.224 0 220.248 0.084 ;
    END
  END c_i[579]
  PIN c_i[57]
    DIRECTION INPUT ;
    USE SIGNAL ;
    PORT
      LAYER M5 ;
        RECT  145.056 0 145.08 0.084 ;
    END
  END c_i[57]
  PIN c_i[580]
    DIRECTION INPUT ;
    USE SIGNAL ;
    PORT
      LAYER M5 ;
        RECT  220.368 0 220.392 0.084 ;
    END
  END c_i[580]
  PIN c_i[581]
    DIRECTION INPUT ;
    USE SIGNAL ;
    PORT
      LAYER M5 ;
        RECT  220.512 0 220.536 0.084 ;
    END
  END c_i[581]
  PIN c_i[582]
    DIRECTION INPUT ;
    USE SIGNAL ;
    PORT
      LAYER M5 ;
        RECT  220.656 0 220.68 0.084 ;
    END
  END c_i[582]
  PIN c_i[583]
    DIRECTION INPUT ;
    USE SIGNAL ;
    PORT
      LAYER M5 ;
        RECT  220.8 0 220.824 0.084 ;
    END
  END c_i[583]
  PIN c_i[584]
    DIRECTION INPUT ;
    USE SIGNAL ;
    PORT
      LAYER M5 ;
        RECT  220.944 0 220.968 0.084 ;
    END
  END c_i[584]
  PIN c_i[585]
    DIRECTION INPUT ;
    USE SIGNAL ;
    PORT
      LAYER M5 ;
        RECT  221.088 0 221.112 0.084 ;
    END
  END c_i[585]
  PIN c_i[586]
    DIRECTION INPUT ;
    USE SIGNAL ;
    PORT
      LAYER M5 ;
        RECT  221.232 0 221.256 0.084 ;
    END
  END c_i[586]
  PIN c_i[587]
    DIRECTION INPUT ;
    USE SIGNAL ;
    PORT
      LAYER M5 ;
        RECT  221.376 0 221.4 0.084 ;
    END
  END c_i[587]
  PIN c_i[588]
    DIRECTION INPUT ;
    USE SIGNAL ;
    PORT
      LAYER M5 ;
        RECT  221.52 0 221.544 0.084 ;
    END
  END c_i[588]
  PIN c_i[589]
    DIRECTION INPUT ;
    USE SIGNAL ;
    PORT
      LAYER M5 ;
        RECT  221.664 0 221.688 0.084 ;
    END
  END c_i[589]
  PIN c_i[58]
    DIRECTION INPUT ;
    USE SIGNAL ;
    PORT
      LAYER M5 ;
        RECT  145.2 0 145.224 0.084 ;
    END
  END c_i[58]
  PIN c_i[590]
    DIRECTION INPUT ;
    USE SIGNAL ;
    PORT
      LAYER M5 ;
        RECT  221.808 0 221.832 0.084 ;
    END
  END c_i[590]
  PIN c_i[591]
    DIRECTION INPUT ;
    USE SIGNAL ;
    PORT
      LAYER M5 ;
        RECT  221.952 0 221.976 0.084 ;
    END
  END c_i[591]
  PIN c_i[592]
    DIRECTION INPUT ;
    USE SIGNAL ;
    PORT
      LAYER M5 ;
        RECT  222.096 0 222.12 0.084 ;
    END
  END c_i[592]
  PIN c_i[593]
    DIRECTION INPUT ;
    USE SIGNAL ;
    PORT
      LAYER M5 ;
        RECT  222.24 0 222.264 0.084 ;
    END
  END c_i[593]
  PIN c_i[594]
    DIRECTION INPUT ;
    USE SIGNAL ;
    PORT
      LAYER M5 ;
        RECT  222.384 0 222.408 0.084 ;
    END
  END c_i[594]
  PIN c_i[595]
    DIRECTION INPUT ;
    USE SIGNAL ;
    PORT
      LAYER M5 ;
        RECT  222.528 0 222.552 0.084 ;
    END
  END c_i[595]
  PIN c_i[596]
    DIRECTION INPUT ;
    USE SIGNAL ;
    PORT
      LAYER M5 ;
        RECT  222.672 0 222.696 0.084 ;
    END
  END c_i[596]
  PIN c_i[597]
    DIRECTION INPUT ;
    USE SIGNAL ;
    PORT
      LAYER M5 ;
        RECT  222.816 0 222.84 0.084 ;
    END
  END c_i[597]
  PIN c_i[598]
    DIRECTION INPUT ;
    USE SIGNAL ;
    PORT
      LAYER M5 ;
        RECT  222.96 0 222.984 0.084 ;
    END
  END c_i[598]
  PIN c_i[599]
    DIRECTION INPUT ;
    USE SIGNAL ;
    PORT
      LAYER M5 ;
        RECT  223.104 0 223.128 0.084 ;
    END
  END c_i[599]
  PIN c_i[59]
    DIRECTION INPUT ;
    USE SIGNAL ;
    PORT
      LAYER M5 ;
        RECT  145.344 0 145.368 0.084 ;
    END
  END c_i[59]
  PIN c_i[5]
    DIRECTION INPUT ;
    USE SIGNAL ;
    PORT
      LAYER M5 ;
        RECT  137.568 0 137.592 0.084 ;
    END
  END c_i[5]
  PIN c_i[600]
    DIRECTION INPUT ;
    USE SIGNAL ;
    PORT
      LAYER M5 ;
        RECT  223.248 0 223.272 0.084 ;
    END
  END c_i[600]
  PIN c_i[601]
    DIRECTION INPUT ;
    USE SIGNAL ;
    PORT
      LAYER M5 ;
        RECT  223.392 0 223.416 0.084 ;
    END
  END c_i[601]
  PIN c_i[602]
    DIRECTION INPUT ;
    USE SIGNAL ;
    PORT
      LAYER M5 ;
        RECT  223.536 0 223.56 0.084 ;
    END
  END c_i[602]
  PIN c_i[603]
    DIRECTION INPUT ;
    USE SIGNAL ;
    PORT
      LAYER M5 ;
        RECT  223.68 0 223.704 0.084 ;
    END
  END c_i[603]
  PIN c_i[604]
    DIRECTION INPUT ;
    USE SIGNAL ;
    PORT
      LAYER M5 ;
        RECT  223.824 0 223.848 0.084 ;
    END
  END c_i[604]
  PIN c_i[605]
    DIRECTION INPUT ;
    USE SIGNAL ;
    PORT
      LAYER M5 ;
        RECT  223.968 0 223.992 0.084 ;
    END
  END c_i[605]
  PIN c_i[606]
    DIRECTION INPUT ;
    USE SIGNAL ;
    PORT
      LAYER M5 ;
        RECT  224.112 0 224.136 0.084 ;
    END
  END c_i[606]
  PIN c_i[607]
    DIRECTION INPUT ;
    USE SIGNAL ;
    PORT
      LAYER M5 ;
        RECT  224.256 0 224.28 0.084 ;
    END
  END c_i[607]
  PIN c_i[608]
    DIRECTION INPUT ;
    USE SIGNAL ;
    PORT
      LAYER M5 ;
        RECT  224.4 0 224.424 0.084 ;
    END
  END c_i[608]
  PIN c_i[609]
    DIRECTION INPUT ;
    USE SIGNAL ;
    PORT
      LAYER M5 ;
        RECT  224.544 0 224.568 0.084 ;
    END
  END c_i[609]
  PIN c_i[60]
    DIRECTION INPUT ;
    USE SIGNAL ;
    PORT
      LAYER M5 ;
        RECT  145.488 0 145.512 0.084 ;
    END
  END c_i[60]
  PIN c_i[610]
    DIRECTION INPUT ;
    USE SIGNAL ;
    PORT
      LAYER M5 ;
        RECT  224.688 0 224.712 0.084 ;
    END
  END c_i[610]
  PIN c_i[611]
    DIRECTION INPUT ;
    USE SIGNAL ;
    PORT
      LAYER M5 ;
        RECT  224.832 0 224.856 0.084 ;
    END
  END c_i[611]
  PIN c_i[612]
    DIRECTION INPUT ;
    USE SIGNAL ;
    PORT
      LAYER M5 ;
        RECT  224.976 0 225 0.084 ;
    END
  END c_i[612]
  PIN c_i[613]
    DIRECTION INPUT ;
    USE SIGNAL ;
    PORT
      LAYER M5 ;
        RECT  225.12 0 225.144 0.084 ;
    END
  END c_i[613]
  PIN c_i[614]
    DIRECTION INPUT ;
    USE SIGNAL ;
    PORT
      LAYER M5 ;
        RECT  225.264 0 225.288 0.084 ;
    END
  END c_i[614]
  PIN c_i[615]
    DIRECTION INPUT ;
    USE SIGNAL ;
    PORT
      LAYER M5 ;
        RECT  225.408 0 225.432 0.084 ;
    END
  END c_i[615]
  PIN c_i[616]
    DIRECTION INPUT ;
    USE SIGNAL ;
    PORT
      LAYER M5 ;
        RECT  225.552 0 225.576 0.084 ;
    END
  END c_i[616]
  PIN c_i[617]
    DIRECTION INPUT ;
    USE SIGNAL ;
    PORT
      LAYER M5 ;
        RECT  225.696 0 225.72 0.084 ;
    END
  END c_i[617]
  PIN c_i[618]
    DIRECTION INPUT ;
    USE SIGNAL ;
    PORT
      LAYER M5 ;
        RECT  225.84 0 225.864 0.084 ;
    END
  END c_i[618]
  PIN c_i[619]
    DIRECTION INPUT ;
    USE SIGNAL ;
    PORT
      LAYER M5 ;
        RECT  225.984 0 226.008 0.084 ;
    END
  END c_i[619]
  PIN c_i[61]
    DIRECTION INPUT ;
    USE SIGNAL ;
    PORT
      LAYER M5 ;
        RECT  145.632 0 145.656 0.084 ;
    END
  END c_i[61]
  PIN c_i[620]
    DIRECTION INPUT ;
    USE SIGNAL ;
    PORT
      LAYER M5 ;
        RECT  226.128 0 226.152 0.084 ;
    END
  END c_i[620]
  PIN c_i[621]
    DIRECTION INPUT ;
    USE SIGNAL ;
    PORT
      LAYER M5 ;
        RECT  226.272 0 226.296 0.084 ;
    END
  END c_i[621]
  PIN c_i[622]
    DIRECTION INPUT ;
    USE SIGNAL ;
    PORT
      LAYER M5 ;
        RECT  226.416 0 226.44 0.084 ;
    END
  END c_i[622]
  PIN c_i[623]
    DIRECTION INPUT ;
    USE SIGNAL ;
    PORT
      LAYER M5 ;
        RECT  226.56 0 226.584 0.084 ;
    END
  END c_i[623]
  PIN c_i[624]
    DIRECTION INPUT ;
    USE SIGNAL ;
    PORT
      LAYER M5 ;
        RECT  226.704 0 226.728 0.084 ;
    END
  END c_i[624]
  PIN c_i[625]
    DIRECTION INPUT ;
    USE SIGNAL ;
    PORT
      LAYER M5 ;
        RECT  226.848 0 226.872 0.084 ;
    END
  END c_i[625]
  PIN c_i[626]
    DIRECTION INPUT ;
    USE SIGNAL ;
    PORT
      LAYER M5 ;
        RECT  226.992 0 227.016 0.084 ;
    END
  END c_i[626]
  PIN c_i[627]
    DIRECTION INPUT ;
    USE SIGNAL ;
    PORT
      LAYER M5 ;
        RECT  227.136 0 227.16 0.084 ;
    END
  END c_i[627]
  PIN c_i[628]
    DIRECTION INPUT ;
    USE SIGNAL ;
    PORT
      LAYER M5 ;
        RECT  227.28 0 227.304 0.084 ;
    END
  END c_i[628]
  PIN c_i[629]
    DIRECTION INPUT ;
    USE SIGNAL ;
    PORT
      LAYER M5 ;
        RECT  227.424 0 227.448 0.084 ;
    END
  END c_i[629]
  PIN c_i[62]
    DIRECTION INPUT ;
    USE SIGNAL ;
    PORT
      LAYER M5 ;
        RECT  145.776 0 145.8 0.084 ;
    END
  END c_i[62]
  PIN c_i[630]
    DIRECTION INPUT ;
    USE SIGNAL ;
    PORT
      LAYER M5 ;
        RECT  227.568 0 227.592 0.084 ;
    END
  END c_i[630]
  PIN c_i[631]
    DIRECTION INPUT ;
    USE SIGNAL ;
    PORT
      LAYER M5 ;
        RECT  227.712 0 227.736 0.084 ;
    END
  END c_i[631]
  PIN c_i[632]
    DIRECTION INPUT ;
    USE SIGNAL ;
    PORT
      LAYER M5 ;
        RECT  227.856 0 227.88 0.084 ;
    END
  END c_i[632]
  PIN c_i[633]
    DIRECTION INPUT ;
    USE SIGNAL ;
    PORT
      LAYER M5 ;
        RECT  228 0 228.024 0.084 ;
    END
  END c_i[633]
  PIN c_i[634]
    DIRECTION INPUT ;
    USE SIGNAL ;
    PORT
      LAYER M5 ;
        RECT  228.144 0 228.168 0.084 ;
    END
  END c_i[634]
  PIN c_i[635]
    DIRECTION INPUT ;
    USE SIGNAL ;
    PORT
      LAYER M5 ;
        RECT  228.288 0 228.312 0.084 ;
    END
  END c_i[635]
  PIN c_i[636]
    DIRECTION INPUT ;
    USE SIGNAL ;
    PORT
      LAYER M5 ;
        RECT  228.432 0 228.456 0.084 ;
    END
  END c_i[636]
  PIN c_i[637]
    DIRECTION INPUT ;
    USE SIGNAL ;
    PORT
      LAYER M5 ;
        RECT  228.576 0 228.6 0.084 ;
    END
  END c_i[637]
  PIN c_i[638]
    DIRECTION INPUT ;
    USE SIGNAL ;
    PORT
      LAYER M5 ;
        RECT  228.72 0 228.744 0.084 ;
    END
  END c_i[638]
  PIN c_i[639]
    DIRECTION INPUT ;
    USE SIGNAL ;
    PORT
      LAYER M5 ;
        RECT  228.864 0 228.888 0.084 ;
    END
  END c_i[639]
  PIN c_i[63]
    DIRECTION INPUT ;
    USE SIGNAL ;
    PORT
      LAYER M5 ;
        RECT  145.92 0 145.944 0.084 ;
    END
  END c_i[63]
  PIN c_i[640]
    DIRECTION INPUT ;
    USE SIGNAL ;
    PORT
      LAYER M5 ;
        RECT  229.008 0 229.032 0.084 ;
    END
  END c_i[640]
  PIN c_i[641]
    DIRECTION INPUT ;
    USE SIGNAL ;
    PORT
      LAYER M5 ;
        RECT  229.152 0 229.176 0.084 ;
    END
  END c_i[641]
  PIN c_i[642]
    DIRECTION INPUT ;
    USE SIGNAL ;
    PORT
      LAYER M5 ;
        RECT  229.296 0 229.32 0.084 ;
    END
  END c_i[642]
  PIN c_i[643]
    DIRECTION INPUT ;
    USE SIGNAL ;
    PORT
      LAYER M5 ;
        RECT  229.44 0 229.464 0.084 ;
    END
  END c_i[643]
  PIN c_i[644]
    DIRECTION INPUT ;
    USE SIGNAL ;
    PORT
      LAYER M5 ;
        RECT  229.584 0 229.608 0.084 ;
    END
  END c_i[644]
  PIN c_i[645]
    DIRECTION INPUT ;
    USE SIGNAL ;
    PORT
      LAYER M5 ;
        RECT  229.728 0 229.752 0.084 ;
    END
  END c_i[645]
  PIN c_i[646]
    DIRECTION INPUT ;
    USE SIGNAL ;
    PORT
      LAYER M5 ;
        RECT  229.872 0 229.896 0.084 ;
    END
  END c_i[646]
  PIN c_i[647]
    DIRECTION INPUT ;
    USE SIGNAL ;
    PORT
      LAYER M5 ;
        RECT  230.016 0 230.04 0.084 ;
    END
  END c_i[647]
  PIN c_i[648]
    DIRECTION INPUT ;
    USE SIGNAL ;
    PORT
      LAYER M5 ;
        RECT  230.16 0 230.184 0.084 ;
    END
  END c_i[648]
  PIN c_i[649]
    DIRECTION INPUT ;
    USE SIGNAL ;
    PORT
      LAYER M5 ;
        RECT  230.304 0 230.328 0.084 ;
    END
  END c_i[649]
  PIN c_i[64]
    DIRECTION INPUT ;
    USE SIGNAL ;
    PORT
      LAYER M5 ;
        RECT  146.064 0 146.088 0.084 ;
    END
  END c_i[64]
  PIN c_i[650]
    DIRECTION INPUT ;
    USE SIGNAL ;
    PORT
      LAYER M5 ;
        RECT  230.448 0 230.472 0.084 ;
    END
  END c_i[650]
  PIN c_i[651]
    DIRECTION INPUT ;
    USE SIGNAL ;
    PORT
      LAYER M5 ;
        RECT  230.592 0 230.616 0.084 ;
    END
  END c_i[651]
  PIN c_i[652]
    DIRECTION INPUT ;
    USE SIGNAL ;
    PORT
      LAYER M5 ;
        RECT  230.736 0 230.76 0.084 ;
    END
  END c_i[652]
  PIN c_i[653]
    DIRECTION INPUT ;
    USE SIGNAL ;
    PORT
      LAYER M5 ;
        RECT  230.88 0 230.904 0.084 ;
    END
  END c_i[653]
  PIN c_i[654]
    DIRECTION INPUT ;
    USE SIGNAL ;
    PORT
      LAYER M5 ;
        RECT  231.024 0 231.048 0.084 ;
    END
  END c_i[654]
  PIN c_i[655]
    DIRECTION INPUT ;
    USE SIGNAL ;
    PORT
      LAYER M5 ;
        RECT  231.168 0 231.192 0.084 ;
    END
  END c_i[655]
  PIN c_i[656]
    DIRECTION INPUT ;
    USE SIGNAL ;
    PORT
      LAYER M5 ;
        RECT  231.312 0 231.336 0.084 ;
    END
  END c_i[656]
  PIN c_i[657]
    DIRECTION INPUT ;
    USE SIGNAL ;
    PORT
      LAYER M5 ;
        RECT  231.456 0 231.48 0.084 ;
    END
  END c_i[657]
  PIN c_i[658]
    DIRECTION INPUT ;
    USE SIGNAL ;
    PORT
      LAYER M5 ;
        RECT  231.6 0 231.624 0.084 ;
    END
  END c_i[658]
  PIN c_i[659]
    DIRECTION INPUT ;
    USE SIGNAL ;
    PORT
      LAYER M5 ;
        RECT  231.744 0 231.768 0.084 ;
    END
  END c_i[659]
  PIN c_i[65]
    DIRECTION INPUT ;
    USE SIGNAL ;
    PORT
      LAYER M5 ;
        RECT  146.208 0 146.232 0.084 ;
    END
  END c_i[65]
  PIN c_i[660]
    DIRECTION INPUT ;
    USE SIGNAL ;
    PORT
      LAYER M5 ;
        RECT  231.888 0 231.912 0.084 ;
    END
  END c_i[660]
  PIN c_i[661]
    DIRECTION INPUT ;
    USE SIGNAL ;
    PORT
      LAYER M5 ;
        RECT  232.032 0 232.056 0.084 ;
    END
  END c_i[661]
  PIN c_i[662]
    DIRECTION INPUT ;
    USE SIGNAL ;
    PORT
      LAYER M5 ;
        RECT  232.176 0 232.2 0.084 ;
    END
  END c_i[662]
  PIN c_i[663]
    DIRECTION INPUT ;
    USE SIGNAL ;
    PORT
      LAYER M5 ;
        RECT  232.32 0 232.344 0.084 ;
    END
  END c_i[663]
  PIN c_i[664]
    DIRECTION INPUT ;
    USE SIGNAL ;
    PORT
      LAYER M5 ;
        RECT  232.464 0 232.488 0.084 ;
    END
  END c_i[664]
  PIN c_i[665]
    DIRECTION INPUT ;
    USE SIGNAL ;
    PORT
      LAYER M5 ;
        RECT  232.608 0 232.632 0.084 ;
    END
  END c_i[665]
  PIN c_i[666]
    DIRECTION INPUT ;
    USE SIGNAL ;
    PORT
      LAYER M5 ;
        RECT  232.752 0 232.776 0.084 ;
    END
  END c_i[666]
  PIN c_i[667]
    DIRECTION INPUT ;
    USE SIGNAL ;
    PORT
      LAYER M5 ;
        RECT  232.896 0 232.92 0.084 ;
    END
  END c_i[667]
  PIN c_i[668]
    DIRECTION INPUT ;
    USE SIGNAL ;
    PORT
      LAYER M5 ;
        RECT  233.04 0 233.064 0.084 ;
    END
  END c_i[668]
  PIN c_i[669]
    DIRECTION INPUT ;
    USE SIGNAL ;
    PORT
      LAYER M5 ;
        RECT  233.184 0 233.208 0.084 ;
    END
  END c_i[669]
  PIN c_i[66]
    DIRECTION INPUT ;
    USE SIGNAL ;
    PORT
      LAYER M5 ;
        RECT  146.352 0 146.376 0.084 ;
    END
  END c_i[66]
  PIN c_i[670]
    DIRECTION INPUT ;
    USE SIGNAL ;
    PORT
      LAYER M5 ;
        RECT  233.328 0 233.352 0.084 ;
    END
  END c_i[670]
  PIN c_i[671]
    DIRECTION INPUT ;
    USE SIGNAL ;
    PORT
      LAYER M5 ;
        RECT  233.472 0 233.496 0.084 ;
    END
  END c_i[671]
  PIN c_i[672]
    DIRECTION INPUT ;
    USE SIGNAL ;
    PORT
      LAYER M5 ;
        RECT  233.616 0 233.64 0.084 ;
    END
  END c_i[672]
  PIN c_i[673]
    DIRECTION INPUT ;
    USE SIGNAL ;
    PORT
      LAYER M5 ;
        RECT  233.76 0 233.784 0.084 ;
    END
  END c_i[673]
  PIN c_i[674]
    DIRECTION INPUT ;
    USE SIGNAL ;
    PORT
      LAYER M5 ;
        RECT  233.904 0 233.928 0.084 ;
    END
  END c_i[674]
  PIN c_i[675]
    DIRECTION INPUT ;
    USE SIGNAL ;
    PORT
      LAYER M5 ;
        RECT  234.048 0 234.072 0.084 ;
    END
  END c_i[675]
  PIN c_i[676]
    DIRECTION INPUT ;
    USE SIGNAL ;
    PORT
      LAYER M5 ;
        RECT  234.192 0 234.216 0.084 ;
    END
  END c_i[676]
  PIN c_i[677]
    DIRECTION INPUT ;
    USE SIGNAL ;
    PORT
      LAYER M5 ;
        RECT  234.336 0 234.36 0.084 ;
    END
  END c_i[677]
  PIN c_i[678]
    DIRECTION INPUT ;
    USE SIGNAL ;
    PORT
      LAYER M5 ;
        RECT  234.48 0 234.504 0.084 ;
    END
  END c_i[678]
  PIN c_i[679]
    DIRECTION INPUT ;
    USE SIGNAL ;
    PORT
      LAYER M5 ;
        RECT  234.624 0 234.648 0.084 ;
    END
  END c_i[679]
  PIN c_i[67]
    DIRECTION INPUT ;
    USE SIGNAL ;
    PORT
      LAYER M5 ;
        RECT  146.496 0 146.52 0.084 ;
    END
  END c_i[67]
  PIN c_i[680]
    DIRECTION INPUT ;
    USE SIGNAL ;
    PORT
      LAYER M5 ;
        RECT  234.768 0 234.792 0.084 ;
    END
  END c_i[680]
  PIN c_i[681]
    DIRECTION INPUT ;
    USE SIGNAL ;
    PORT
      LAYER M5 ;
        RECT  234.912 0 234.936 0.084 ;
    END
  END c_i[681]
  PIN c_i[682]
    DIRECTION INPUT ;
    USE SIGNAL ;
    PORT
      LAYER M5 ;
        RECT  235.056 0 235.08 0.084 ;
    END
  END c_i[682]
  PIN c_i[683]
    DIRECTION INPUT ;
    USE SIGNAL ;
    PORT
      LAYER M5 ;
        RECT  235.2 0 235.224 0.084 ;
    END
  END c_i[683]
  PIN c_i[684]
    DIRECTION INPUT ;
    USE SIGNAL ;
    PORT
      LAYER M5 ;
        RECT  235.344 0 235.368 0.084 ;
    END
  END c_i[684]
  PIN c_i[685]
    DIRECTION INPUT ;
    USE SIGNAL ;
    PORT
      LAYER M5 ;
        RECT  235.488 0 235.512 0.084 ;
    END
  END c_i[685]
  PIN c_i[686]
    DIRECTION INPUT ;
    USE SIGNAL ;
    PORT
      LAYER M5 ;
        RECT  235.632 0 235.656 0.084 ;
    END
  END c_i[686]
  PIN c_i[687]
    DIRECTION INPUT ;
    USE SIGNAL ;
    PORT
      LAYER M5 ;
        RECT  235.776 0 235.8 0.084 ;
    END
  END c_i[687]
  PIN c_i[688]
    DIRECTION INPUT ;
    USE SIGNAL ;
    PORT
      LAYER M5 ;
        RECT  235.92 0 235.944 0.084 ;
    END
  END c_i[688]
  PIN c_i[689]
    DIRECTION INPUT ;
    USE SIGNAL ;
    PORT
      LAYER M5 ;
        RECT  236.064 0 236.088 0.084 ;
    END
  END c_i[689]
  PIN c_i[68]
    DIRECTION INPUT ;
    USE SIGNAL ;
    PORT
      LAYER M5 ;
        RECT  146.64 0 146.664 0.084 ;
    END
  END c_i[68]
  PIN c_i[690]
    DIRECTION INPUT ;
    USE SIGNAL ;
    PORT
      LAYER M5 ;
        RECT  236.208 0 236.232 0.084 ;
    END
  END c_i[690]
  PIN c_i[691]
    DIRECTION INPUT ;
    USE SIGNAL ;
    PORT
      LAYER M5 ;
        RECT  236.352 0 236.376 0.084 ;
    END
  END c_i[691]
  PIN c_i[692]
    DIRECTION INPUT ;
    USE SIGNAL ;
    PORT
      LAYER M5 ;
        RECT  236.496 0 236.52 0.084 ;
    END
  END c_i[692]
  PIN c_i[693]
    DIRECTION INPUT ;
    USE SIGNAL ;
    PORT
      LAYER M5 ;
        RECT  236.64 0 236.664 0.084 ;
    END
  END c_i[693]
  PIN c_i[694]
    DIRECTION INPUT ;
    USE SIGNAL ;
    PORT
      LAYER M5 ;
        RECT  236.784 0 236.808 0.084 ;
    END
  END c_i[694]
  PIN c_i[695]
    DIRECTION INPUT ;
    USE SIGNAL ;
    PORT
      LAYER M5 ;
        RECT  236.928 0 236.952 0.084 ;
    END
  END c_i[695]
  PIN c_i[696]
    DIRECTION INPUT ;
    USE SIGNAL ;
    PORT
      LAYER M5 ;
        RECT  237.072 0 237.096 0.084 ;
    END
  END c_i[696]
  PIN c_i[697]
    DIRECTION INPUT ;
    USE SIGNAL ;
    PORT
      LAYER M5 ;
        RECT  237.216 0 237.24 0.084 ;
    END
  END c_i[697]
  PIN c_i[698]
    DIRECTION INPUT ;
    USE SIGNAL ;
    PORT
      LAYER M5 ;
        RECT  237.36 0 237.384 0.084 ;
    END
  END c_i[698]
  PIN c_i[699]
    DIRECTION INPUT ;
    USE SIGNAL ;
    PORT
      LAYER M5 ;
        RECT  237.504 0 237.528 0.084 ;
    END
  END c_i[699]
  PIN c_i[69]
    DIRECTION INPUT ;
    USE SIGNAL ;
    PORT
      LAYER M5 ;
        RECT  146.784 0 146.808 0.084 ;
    END
  END c_i[69]
  PIN c_i[6]
    DIRECTION INPUT ;
    USE SIGNAL ;
    PORT
      LAYER M5 ;
        RECT  137.712 0 137.736 0.084 ;
    END
  END c_i[6]
  PIN c_i[700]
    DIRECTION INPUT ;
    USE SIGNAL ;
    PORT
      LAYER M5 ;
        RECT  237.648 0 237.672 0.084 ;
    END
  END c_i[700]
  PIN c_i[701]
    DIRECTION INPUT ;
    USE SIGNAL ;
    PORT
      LAYER M5 ;
        RECT  237.792 0 237.816 0.084 ;
    END
  END c_i[701]
  PIN c_i[702]
    DIRECTION INPUT ;
    USE SIGNAL ;
    PORT
      LAYER M5 ;
        RECT  237.936 0 237.96 0.084 ;
    END
  END c_i[702]
  PIN c_i[703]
    DIRECTION INPUT ;
    USE SIGNAL ;
    PORT
      LAYER M5 ;
        RECT  238.08 0 238.104 0.084 ;
    END
  END c_i[703]
  PIN c_i[704]
    DIRECTION INPUT ;
    USE SIGNAL ;
    PORT
      LAYER M5 ;
        RECT  238.224 0 238.248 0.084 ;
    END
  END c_i[704]
  PIN c_i[705]
    DIRECTION INPUT ;
    USE SIGNAL ;
    PORT
      LAYER M5 ;
        RECT  238.368 0 238.392 0.084 ;
    END
  END c_i[705]
  PIN c_i[706]
    DIRECTION INPUT ;
    USE SIGNAL ;
    PORT
      LAYER M5 ;
        RECT  238.512 0 238.536 0.084 ;
    END
  END c_i[706]
  PIN c_i[707]
    DIRECTION INPUT ;
    USE SIGNAL ;
    PORT
      LAYER M5 ;
        RECT  238.656 0 238.68 0.084 ;
    END
  END c_i[707]
  PIN c_i[708]
    DIRECTION INPUT ;
    USE SIGNAL ;
    PORT
      LAYER M5 ;
        RECT  238.8 0 238.824 0.084 ;
    END
  END c_i[708]
  PIN c_i[709]
    DIRECTION INPUT ;
    USE SIGNAL ;
    PORT
      LAYER M5 ;
        RECT  238.944 0 238.968 0.084 ;
    END
  END c_i[709]
  PIN c_i[70]
    DIRECTION INPUT ;
    USE SIGNAL ;
    PORT
      LAYER M5 ;
        RECT  146.928 0 146.952 0.084 ;
    END
  END c_i[70]
  PIN c_i[710]
    DIRECTION INPUT ;
    USE SIGNAL ;
    PORT
      LAYER M5 ;
        RECT  239.088 0 239.112 0.084 ;
    END
  END c_i[710]
  PIN c_i[711]
    DIRECTION INPUT ;
    USE SIGNAL ;
    PORT
      LAYER M5 ;
        RECT  239.232 0 239.256 0.084 ;
    END
  END c_i[711]
  PIN c_i[712]
    DIRECTION INPUT ;
    USE SIGNAL ;
    PORT
      LAYER M5 ;
        RECT  239.376 0 239.4 0.084 ;
    END
  END c_i[712]
  PIN c_i[713]
    DIRECTION INPUT ;
    USE SIGNAL ;
    PORT
      LAYER M5 ;
        RECT  239.52 0 239.544 0.084 ;
    END
  END c_i[713]
  PIN c_i[714]
    DIRECTION INPUT ;
    USE SIGNAL ;
    PORT
      LAYER M5 ;
        RECT  239.664 0 239.688 0.084 ;
    END
  END c_i[714]
  PIN c_i[715]
    DIRECTION INPUT ;
    USE SIGNAL ;
    PORT
      LAYER M5 ;
        RECT  239.808 0 239.832 0.084 ;
    END
  END c_i[715]
  PIN c_i[716]
    DIRECTION INPUT ;
    USE SIGNAL ;
    PORT
      LAYER M5 ;
        RECT  239.952 0 239.976 0.084 ;
    END
  END c_i[716]
  PIN c_i[717]
    DIRECTION INPUT ;
    USE SIGNAL ;
    PORT
      LAYER M5 ;
        RECT  240.096 0 240.12 0.084 ;
    END
  END c_i[717]
  PIN c_i[718]
    DIRECTION INPUT ;
    USE SIGNAL ;
    PORT
      LAYER M5 ;
        RECT  240.24 0 240.264 0.084 ;
    END
  END c_i[718]
  PIN c_i[719]
    DIRECTION INPUT ;
    USE SIGNAL ;
    PORT
      LAYER M5 ;
        RECT  240.384 0 240.408 0.084 ;
    END
  END c_i[719]
  PIN c_i[71]
    DIRECTION INPUT ;
    USE SIGNAL ;
    PORT
      LAYER M5 ;
        RECT  147.072 0 147.096 0.084 ;
    END
  END c_i[71]
  PIN c_i[720]
    DIRECTION INPUT ;
    USE SIGNAL ;
    PORT
      LAYER M5 ;
        RECT  240.528 0 240.552 0.084 ;
    END
  END c_i[720]
  PIN c_i[721]
    DIRECTION INPUT ;
    USE SIGNAL ;
    PORT
      LAYER M5 ;
        RECT  240.672 0 240.696 0.084 ;
    END
  END c_i[721]
  PIN c_i[722]
    DIRECTION INPUT ;
    USE SIGNAL ;
    PORT
      LAYER M5 ;
        RECT  240.816 0 240.84 0.084 ;
    END
  END c_i[722]
  PIN c_i[723]
    DIRECTION INPUT ;
    USE SIGNAL ;
    PORT
      LAYER M5 ;
        RECT  240.96 0 240.984 0.084 ;
    END
  END c_i[723]
  PIN c_i[724]
    DIRECTION INPUT ;
    USE SIGNAL ;
    PORT
      LAYER M5 ;
        RECT  241.104 0 241.128 0.084 ;
    END
  END c_i[724]
  PIN c_i[725]
    DIRECTION INPUT ;
    USE SIGNAL ;
    PORT
      LAYER M5 ;
        RECT  241.248 0 241.272 0.084 ;
    END
  END c_i[725]
  PIN c_i[726]
    DIRECTION INPUT ;
    USE SIGNAL ;
    PORT
      LAYER M5 ;
        RECT  241.392 0 241.416 0.084 ;
    END
  END c_i[726]
  PIN c_i[727]
    DIRECTION INPUT ;
    USE SIGNAL ;
    PORT
      LAYER M5 ;
        RECT  241.536 0 241.56 0.084 ;
    END
  END c_i[727]
  PIN c_i[728]
    DIRECTION INPUT ;
    USE SIGNAL ;
    PORT
      LAYER M5 ;
        RECT  241.68 0 241.704 0.084 ;
    END
  END c_i[728]
  PIN c_i[729]
    DIRECTION INPUT ;
    USE SIGNAL ;
    PORT
      LAYER M5 ;
        RECT  241.824 0 241.848 0.084 ;
    END
  END c_i[729]
  PIN c_i[72]
    DIRECTION INPUT ;
    USE SIGNAL ;
    PORT
      LAYER M5 ;
        RECT  147.216 0 147.24 0.084 ;
    END
  END c_i[72]
  PIN c_i[730]
    DIRECTION INPUT ;
    USE SIGNAL ;
    PORT
      LAYER M5 ;
        RECT  241.968 0 241.992 0.084 ;
    END
  END c_i[730]
  PIN c_i[731]
    DIRECTION INPUT ;
    USE SIGNAL ;
    PORT
      LAYER M5 ;
        RECT  242.112 0 242.136 0.084 ;
    END
  END c_i[731]
  PIN c_i[732]
    DIRECTION INPUT ;
    USE SIGNAL ;
    PORT
      LAYER M5 ;
        RECT  242.256 0 242.28 0.084 ;
    END
  END c_i[732]
  PIN c_i[733]
    DIRECTION INPUT ;
    USE SIGNAL ;
    PORT
      LAYER M5 ;
        RECT  242.4 0 242.424 0.084 ;
    END
  END c_i[733]
  PIN c_i[734]
    DIRECTION INPUT ;
    USE SIGNAL ;
    PORT
      LAYER M5 ;
        RECT  242.544 0 242.568 0.084 ;
    END
  END c_i[734]
  PIN c_i[735]
    DIRECTION INPUT ;
    USE SIGNAL ;
    PORT
      LAYER M5 ;
        RECT  242.688 0 242.712 0.084 ;
    END
  END c_i[735]
  PIN c_i[736]
    DIRECTION INPUT ;
    USE SIGNAL ;
    PORT
      LAYER M5 ;
        RECT  242.832 0 242.856 0.084 ;
    END
  END c_i[736]
  PIN c_i[737]
    DIRECTION INPUT ;
    USE SIGNAL ;
    PORT
      LAYER M5 ;
        RECT  242.976 0 243 0.084 ;
    END
  END c_i[737]
  PIN c_i[738]
    DIRECTION INPUT ;
    USE SIGNAL ;
    PORT
      LAYER M5 ;
        RECT  243.12 0 243.144 0.084 ;
    END
  END c_i[738]
  PIN c_i[739]
    DIRECTION INPUT ;
    USE SIGNAL ;
    PORT
      LAYER M5 ;
        RECT  243.264 0 243.288 0.084 ;
    END
  END c_i[739]
  PIN c_i[73]
    DIRECTION INPUT ;
    USE SIGNAL ;
    PORT
      LAYER M5 ;
        RECT  147.36 0 147.384 0.084 ;
    END
  END c_i[73]
  PIN c_i[740]
    DIRECTION INPUT ;
    USE SIGNAL ;
    PORT
      LAYER M5 ;
        RECT  243.408 0 243.432 0.084 ;
    END
  END c_i[740]
  PIN c_i[741]
    DIRECTION INPUT ;
    USE SIGNAL ;
    PORT
      LAYER M5 ;
        RECT  243.552 0 243.576 0.084 ;
    END
  END c_i[741]
  PIN c_i[742]
    DIRECTION INPUT ;
    USE SIGNAL ;
    PORT
      LAYER M5 ;
        RECT  243.696 0 243.72 0.084 ;
    END
  END c_i[742]
  PIN c_i[743]
    DIRECTION INPUT ;
    USE SIGNAL ;
    PORT
      LAYER M5 ;
        RECT  243.84 0 243.864 0.084 ;
    END
  END c_i[743]
  PIN c_i[744]
    DIRECTION INPUT ;
    USE SIGNAL ;
    PORT
      LAYER M5 ;
        RECT  243.984 0 244.008 0.084 ;
    END
  END c_i[744]
  PIN c_i[745]
    DIRECTION INPUT ;
    USE SIGNAL ;
    PORT
      LAYER M5 ;
        RECT  244.128 0 244.152 0.084 ;
    END
  END c_i[745]
  PIN c_i[746]
    DIRECTION INPUT ;
    USE SIGNAL ;
    PORT
      LAYER M5 ;
        RECT  244.272 0 244.296 0.084 ;
    END
  END c_i[746]
  PIN c_i[747]
    DIRECTION INPUT ;
    USE SIGNAL ;
    PORT
      LAYER M5 ;
        RECT  244.416 0 244.44 0.084 ;
    END
  END c_i[747]
  PIN c_i[748]
    DIRECTION INPUT ;
    USE SIGNAL ;
    PORT
      LAYER M5 ;
        RECT  244.56 0 244.584 0.084 ;
    END
  END c_i[748]
  PIN c_i[749]
    DIRECTION INPUT ;
    USE SIGNAL ;
    PORT
      LAYER M5 ;
        RECT  244.704 0 244.728 0.084 ;
    END
  END c_i[749]
  PIN c_i[74]
    DIRECTION INPUT ;
    USE SIGNAL ;
    PORT
      LAYER M5 ;
        RECT  147.504 0 147.528 0.084 ;
    END
  END c_i[74]
  PIN c_i[750]
    DIRECTION INPUT ;
    USE SIGNAL ;
    PORT
      LAYER M5 ;
        RECT  244.848 0 244.872 0.084 ;
    END
  END c_i[750]
  PIN c_i[751]
    DIRECTION INPUT ;
    USE SIGNAL ;
    PORT
      LAYER M5 ;
        RECT  244.992 0 245.016 0.084 ;
    END
  END c_i[751]
  PIN c_i[752]
    DIRECTION INPUT ;
    USE SIGNAL ;
    PORT
      LAYER M5 ;
        RECT  245.136 0 245.16 0.084 ;
    END
  END c_i[752]
  PIN c_i[753]
    DIRECTION INPUT ;
    USE SIGNAL ;
    PORT
      LAYER M5 ;
        RECT  245.28 0 245.304 0.084 ;
    END
  END c_i[753]
  PIN c_i[754]
    DIRECTION INPUT ;
    USE SIGNAL ;
    PORT
      LAYER M5 ;
        RECT  245.424 0 245.448 0.084 ;
    END
  END c_i[754]
  PIN c_i[755]
    DIRECTION INPUT ;
    USE SIGNAL ;
    PORT
      LAYER M5 ;
        RECT  245.568 0 245.592 0.084 ;
    END
  END c_i[755]
  PIN c_i[756]
    DIRECTION INPUT ;
    USE SIGNAL ;
    PORT
      LAYER M5 ;
        RECT  245.712 0 245.736 0.084 ;
    END
  END c_i[756]
  PIN c_i[757]
    DIRECTION INPUT ;
    USE SIGNAL ;
    PORT
      LAYER M5 ;
        RECT  245.856 0 245.88 0.084 ;
    END
  END c_i[757]
  PIN c_i[758]
    DIRECTION INPUT ;
    USE SIGNAL ;
    PORT
      LAYER M5 ;
        RECT  246 0 246.024 0.084 ;
    END
  END c_i[758]
  PIN c_i[759]
    DIRECTION INPUT ;
    USE SIGNAL ;
    PORT
      LAYER M5 ;
        RECT  246.144 0 246.168 0.084 ;
    END
  END c_i[759]
  PIN c_i[75]
    DIRECTION INPUT ;
    USE SIGNAL ;
    PORT
      LAYER M5 ;
        RECT  147.648 0 147.672 0.084 ;
    END
  END c_i[75]
  PIN c_i[76]
    DIRECTION INPUT ;
    USE SIGNAL ;
    PORT
      LAYER M5 ;
        RECT  147.792 0 147.816 0.084 ;
    END
  END c_i[76]
  PIN c_i[77]
    DIRECTION INPUT ;
    USE SIGNAL ;
    PORT
      LAYER M5 ;
        RECT  147.936 0 147.96 0.084 ;
    END
  END c_i[77]
  PIN c_i[78]
    DIRECTION INPUT ;
    USE SIGNAL ;
    PORT
      LAYER M5 ;
        RECT  148.08 0 148.104 0.084 ;
    END
  END c_i[78]
  PIN c_i[79]
    DIRECTION INPUT ;
    USE SIGNAL ;
    PORT
      LAYER M5 ;
        RECT  148.224 0 148.248 0.084 ;
    END
  END c_i[79]
  PIN c_i[7]
    DIRECTION INPUT ;
    USE SIGNAL ;
    PORT
      LAYER M5 ;
        RECT  137.856 0 137.88 0.084 ;
    END
  END c_i[7]
  PIN c_i[80]
    DIRECTION INPUT ;
    USE SIGNAL ;
    PORT
      LAYER M5 ;
        RECT  148.368 0 148.392 0.084 ;
    END
  END c_i[80]
  PIN c_i[81]
    DIRECTION INPUT ;
    USE SIGNAL ;
    PORT
      LAYER M5 ;
        RECT  148.512 0 148.536 0.084 ;
    END
  END c_i[81]
  PIN c_i[82]
    DIRECTION INPUT ;
    USE SIGNAL ;
    PORT
      LAYER M5 ;
        RECT  148.656 0 148.68 0.084 ;
    END
  END c_i[82]
  PIN c_i[83]
    DIRECTION INPUT ;
    USE SIGNAL ;
    PORT
      LAYER M5 ;
        RECT  148.8 0 148.824 0.084 ;
    END
  END c_i[83]
  PIN c_i[84]
    DIRECTION INPUT ;
    USE SIGNAL ;
    PORT
      LAYER M5 ;
        RECT  148.944 0 148.968 0.084 ;
    END
  END c_i[84]
  PIN c_i[85]
    DIRECTION INPUT ;
    USE SIGNAL ;
    PORT
      LAYER M5 ;
        RECT  149.088 0 149.112 0.084 ;
    END
  END c_i[85]
  PIN c_i[86]
    DIRECTION INPUT ;
    USE SIGNAL ;
    PORT
      LAYER M5 ;
        RECT  149.232 0 149.256 0.084 ;
    END
  END c_i[86]
  PIN c_i[87]
    DIRECTION INPUT ;
    USE SIGNAL ;
    PORT
      LAYER M5 ;
        RECT  149.376 0 149.4 0.084 ;
    END
  END c_i[87]
  PIN c_i[88]
    DIRECTION INPUT ;
    USE SIGNAL ;
    PORT
      LAYER M5 ;
        RECT  149.52 0 149.544 0.084 ;
    END
  END c_i[88]
  PIN c_i[89]
    DIRECTION INPUT ;
    USE SIGNAL ;
    PORT
      LAYER M5 ;
        RECT  149.664 0 149.688 0.084 ;
    END
  END c_i[89]
  PIN c_i[8]
    DIRECTION INPUT ;
    USE SIGNAL ;
    PORT
      LAYER M5 ;
        RECT  138 0 138.024 0.084 ;
    END
  END c_i[8]
  PIN c_i[90]
    DIRECTION INPUT ;
    USE SIGNAL ;
    PORT
      LAYER M5 ;
        RECT  149.808 0 149.832 0.084 ;
    END
  END c_i[90]
  PIN c_i[91]
    DIRECTION INPUT ;
    USE SIGNAL ;
    PORT
      LAYER M5 ;
        RECT  149.952 0 149.976 0.084 ;
    END
  END c_i[91]
  PIN c_i[92]
    DIRECTION INPUT ;
    USE SIGNAL ;
    PORT
      LAYER M5 ;
        RECT  150.096 0 150.12 0.084 ;
    END
  END c_i[92]
  PIN c_i[93]
    DIRECTION INPUT ;
    USE SIGNAL ;
    PORT
      LAYER M5 ;
        RECT  150.24 0 150.264 0.084 ;
    END
  END c_i[93]
  PIN c_i[94]
    DIRECTION INPUT ;
    USE SIGNAL ;
    PORT
      LAYER M5 ;
        RECT  150.384 0 150.408 0.084 ;
    END
  END c_i[94]
  PIN c_i[95]
    DIRECTION INPUT ;
    USE SIGNAL ;
    PORT
      LAYER M5 ;
        RECT  150.528 0 150.552 0.084 ;
    END
  END c_i[95]
  PIN c_i[96]
    DIRECTION INPUT ;
    USE SIGNAL ;
    PORT
      LAYER M5 ;
        RECT  150.672 0 150.696 0.084 ;
    END
  END c_i[96]
  PIN c_i[97]
    DIRECTION INPUT ;
    USE SIGNAL ;
    PORT
      LAYER M5 ;
        RECT  150.816 0 150.84 0.084 ;
    END
  END c_i[97]
  PIN c_i[98]
    DIRECTION INPUT ;
    USE SIGNAL ;
    PORT
      LAYER M5 ;
        RECT  150.96 0 150.984 0.084 ;
    END
  END c_i[98]
  PIN c_i[99]
    DIRECTION INPUT ;
    USE SIGNAL ;
    PORT
      LAYER M5 ;
        RECT  151.104 0 151.128 0.084 ;
    END
  END c_i[99]
  PIN c_i[9]
    DIRECTION INPUT ;
    USE SIGNAL ;
    PORT
      LAYER M5 ;
        RECT  138.144 0 138.168 0.084 ;
    END
  END c_i[9]
  PIN c_o[0]
    DIRECTION OUTPUT ;
    USE SIGNAL ;
    PORT
      LAYER M5 ;
        RECT  246.288 0 246.312 0.084 ;
    END
  END c_o[0]
  PIN c_o[100]
    DIRECTION OUTPUT ;
    USE SIGNAL ;
    PORT
      LAYER M5 ;
        RECT  260.688 0 260.712 0.084 ;
    END
  END c_o[100]
  PIN c_o[101]
    DIRECTION OUTPUT ;
    USE SIGNAL ;
    PORT
      LAYER M5 ;
        RECT  260.832 0 260.856 0.084 ;
    END
  END c_o[101]
  PIN c_o[102]
    DIRECTION OUTPUT ;
    USE SIGNAL ;
    PORT
      LAYER M5 ;
        RECT  260.976 0 261 0.084 ;
    END
  END c_o[102]
  PIN c_o[103]
    DIRECTION OUTPUT ;
    USE SIGNAL ;
    PORT
      LAYER M5 ;
        RECT  261.12 0 261.144 0.084 ;
    END
  END c_o[103]
  PIN c_o[104]
    DIRECTION OUTPUT ;
    USE SIGNAL ;
    PORT
      LAYER M5 ;
        RECT  261.264 0 261.288 0.084 ;
    END
  END c_o[104]
  PIN c_o[105]
    DIRECTION OUTPUT ;
    USE SIGNAL ;
    PORT
      LAYER M5 ;
        RECT  261.408 0 261.432 0.084 ;
    END
  END c_o[105]
  PIN c_o[106]
    DIRECTION OUTPUT ;
    USE SIGNAL ;
    PORT
      LAYER M5 ;
        RECT  261.552 0 261.576 0.084 ;
    END
  END c_o[106]
  PIN c_o[107]
    DIRECTION OUTPUT ;
    USE SIGNAL ;
    PORT
      LAYER M5 ;
        RECT  261.696 0 261.72 0.084 ;
    END
  END c_o[107]
  PIN c_o[108]
    DIRECTION OUTPUT ;
    USE SIGNAL ;
    PORT
      LAYER M5 ;
        RECT  261.84 0 261.864 0.084 ;
    END
  END c_o[108]
  PIN c_o[109]
    DIRECTION OUTPUT ;
    USE SIGNAL ;
    PORT
      LAYER M5 ;
        RECT  261.984 0 262.008 0.084 ;
    END
  END c_o[109]
  PIN c_o[10]
    DIRECTION OUTPUT ;
    USE SIGNAL ;
    PORT
      LAYER M5 ;
        RECT  247.728 0 247.752 0.084 ;
    END
  END c_o[10]
  PIN c_o[110]
    DIRECTION OUTPUT ;
    USE SIGNAL ;
    PORT
      LAYER M5 ;
        RECT  262.128 0 262.152 0.084 ;
    END
  END c_o[110]
  PIN c_o[111]
    DIRECTION OUTPUT ;
    USE SIGNAL ;
    PORT
      LAYER M5 ;
        RECT  262.272 0 262.296 0.084 ;
    END
  END c_o[111]
  PIN c_o[112]
    DIRECTION OUTPUT ;
    USE SIGNAL ;
    PORT
      LAYER M5 ;
        RECT  262.416 0 262.44 0.084 ;
    END
  END c_o[112]
  PIN c_o[113]
    DIRECTION OUTPUT ;
    USE SIGNAL ;
    PORT
      LAYER M5 ;
        RECT  262.56 0 262.584 0.084 ;
    END
  END c_o[113]
  PIN c_o[114]
    DIRECTION OUTPUT ;
    USE SIGNAL ;
    PORT
      LAYER M5 ;
        RECT  262.704 0 262.728 0.084 ;
    END
  END c_o[114]
  PIN c_o[115]
    DIRECTION OUTPUT ;
    USE SIGNAL ;
    PORT
      LAYER M5 ;
        RECT  262.848 0 262.872 0.084 ;
    END
  END c_o[115]
  PIN c_o[116]
    DIRECTION OUTPUT ;
    USE SIGNAL ;
    PORT
      LAYER M5 ;
        RECT  262.992 0 263.016 0.084 ;
    END
  END c_o[116]
  PIN c_o[117]
    DIRECTION OUTPUT ;
    USE SIGNAL ;
    PORT
      LAYER M5 ;
        RECT  263.136 0 263.16 0.084 ;
    END
  END c_o[117]
  PIN c_o[118]
    DIRECTION OUTPUT ;
    USE SIGNAL ;
    PORT
      LAYER M5 ;
        RECT  263.28 0 263.304 0.084 ;
    END
  END c_o[118]
  PIN c_o[119]
    DIRECTION OUTPUT ;
    USE SIGNAL ;
    PORT
      LAYER M5 ;
        RECT  263.424 0 263.448 0.084 ;
    END
  END c_o[119]
  PIN c_o[11]
    DIRECTION OUTPUT ;
    USE SIGNAL ;
    PORT
      LAYER M5 ;
        RECT  247.872 0 247.896 0.084 ;
    END
  END c_o[11]
  PIN c_o[120]
    DIRECTION OUTPUT ;
    USE SIGNAL ;
    PORT
      LAYER M5 ;
        RECT  263.568 0 263.592 0.084 ;
    END
  END c_o[120]
  PIN c_o[121]
    DIRECTION OUTPUT ;
    USE SIGNAL ;
    PORT
      LAYER M5 ;
        RECT  263.712 0 263.736 0.084 ;
    END
  END c_o[121]
  PIN c_o[122]
    DIRECTION OUTPUT ;
    USE SIGNAL ;
    PORT
      LAYER M5 ;
        RECT  263.856 0 263.88 0.084 ;
    END
  END c_o[122]
  PIN c_o[123]
    DIRECTION OUTPUT ;
    USE SIGNAL ;
    PORT
      LAYER M5 ;
        RECT  264 0 264.024 0.084 ;
    END
  END c_o[123]
  PIN c_o[124]
    DIRECTION OUTPUT ;
    USE SIGNAL ;
    PORT
      LAYER M5 ;
        RECT  264.144 0 264.168 0.084 ;
    END
  END c_o[124]
  PIN c_o[125]
    DIRECTION OUTPUT ;
    USE SIGNAL ;
    PORT
      LAYER M5 ;
        RECT  264.288 0 264.312 0.084 ;
    END
  END c_o[125]
  PIN c_o[126]
    DIRECTION OUTPUT ;
    USE SIGNAL ;
    PORT
      LAYER M5 ;
        RECT  264.432 0 264.456 0.084 ;
    END
  END c_o[126]
  PIN c_o[127]
    DIRECTION OUTPUT ;
    USE SIGNAL ;
    PORT
      LAYER M5 ;
        RECT  264.576 0 264.6 0.084 ;
    END
  END c_o[127]
  PIN c_o[128]
    DIRECTION OUTPUT ;
    USE SIGNAL ;
    PORT
      LAYER M5 ;
        RECT  264.72 0 264.744 0.084 ;
    END
  END c_o[128]
  PIN c_o[129]
    DIRECTION OUTPUT ;
    USE SIGNAL ;
    PORT
      LAYER M5 ;
        RECT  264.864 0 264.888 0.084 ;
    END
  END c_o[129]
  PIN c_o[12]
    DIRECTION OUTPUT ;
    USE SIGNAL ;
    PORT
      LAYER M5 ;
        RECT  248.016 0 248.04 0.084 ;
    END
  END c_o[12]
  PIN c_o[130]
    DIRECTION OUTPUT ;
    USE SIGNAL ;
    PORT
      LAYER M5 ;
        RECT  265.008 0 265.032 0.084 ;
    END
  END c_o[130]
  PIN c_o[131]
    DIRECTION OUTPUT ;
    USE SIGNAL ;
    PORT
      LAYER M5 ;
        RECT  265.152 0 265.176 0.084 ;
    END
  END c_o[131]
  PIN c_o[132]
    DIRECTION OUTPUT ;
    USE SIGNAL ;
    PORT
      LAYER M5 ;
        RECT  265.296 0 265.32 0.084 ;
    END
  END c_o[132]
  PIN c_o[133]
    DIRECTION OUTPUT ;
    USE SIGNAL ;
    PORT
      LAYER M5 ;
        RECT  265.44 0 265.464 0.084 ;
    END
  END c_o[133]
  PIN c_o[134]
    DIRECTION OUTPUT ;
    USE SIGNAL ;
    PORT
      LAYER M5 ;
        RECT  265.584 0 265.608 0.084 ;
    END
  END c_o[134]
  PIN c_o[135]
    DIRECTION OUTPUT ;
    USE SIGNAL ;
    PORT
      LAYER M5 ;
        RECT  265.728 0 265.752 0.084 ;
    END
  END c_o[135]
  PIN c_o[136]
    DIRECTION OUTPUT ;
    USE SIGNAL ;
    PORT
      LAYER M5 ;
        RECT  265.872 0 265.896 0.084 ;
    END
  END c_o[136]
  PIN c_o[137]
    DIRECTION OUTPUT ;
    USE SIGNAL ;
    PORT
      LAYER M5 ;
        RECT  266.016 0 266.04 0.084 ;
    END
  END c_o[137]
  PIN c_o[138]
    DIRECTION OUTPUT ;
    USE SIGNAL ;
    PORT
      LAYER M5 ;
        RECT  266.16 0 266.184 0.084 ;
    END
  END c_o[138]
  PIN c_o[139]
    DIRECTION OUTPUT ;
    USE SIGNAL ;
    PORT
      LAYER M5 ;
        RECT  266.304 0 266.328 0.084 ;
    END
  END c_o[139]
  PIN c_o[13]
    DIRECTION OUTPUT ;
    USE SIGNAL ;
    PORT
      LAYER M5 ;
        RECT  248.16 0 248.184 0.084 ;
    END
  END c_o[13]
  PIN c_o[140]
    DIRECTION OUTPUT ;
    USE SIGNAL ;
    PORT
      LAYER M5 ;
        RECT  266.448 0 266.472 0.084 ;
    END
  END c_o[140]
  PIN c_o[141]
    DIRECTION OUTPUT ;
    USE SIGNAL ;
    PORT
      LAYER M5 ;
        RECT  266.592 0 266.616 0.084 ;
    END
  END c_o[141]
  PIN c_o[142]
    DIRECTION OUTPUT ;
    USE SIGNAL ;
    PORT
      LAYER M5 ;
        RECT  266.736 0 266.76 0.084 ;
    END
  END c_o[142]
  PIN c_o[143]
    DIRECTION OUTPUT ;
    USE SIGNAL ;
    PORT
      LAYER M5 ;
        RECT  266.88 0 266.904 0.084 ;
    END
  END c_o[143]
  PIN c_o[144]
    DIRECTION OUTPUT ;
    USE SIGNAL ;
    PORT
      LAYER M5 ;
        RECT  267.024 0 267.048 0.084 ;
    END
  END c_o[144]
  PIN c_o[145]
    DIRECTION OUTPUT ;
    USE SIGNAL ;
    PORT
      LAYER M5 ;
        RECT  267.168 0 267.192 0.084 ;
    END
  END c_o[145]
  PIN c_o[146]
    DIRECTION OUTPUT ;
    USE SIGNAL ;
    PORT
      LAYER M5 ;
        RECT  267.312 0 267.336 0.084 ;
    END
  END c_o[146]
  PIN c_o[147]
    DIRECTION OUTPUT ;
    USE SIGNAL ;
    PORT
      LAYER M5 ;
        RECT  267.456 0 267.48 0.084 ;
    END
  END c_o[147]
  PIN c_o[148]
    DIRECTION OUTPUT ;
    USE SIGNAL ;
    PORT
      LAYER M5 ;
        RECT  267.6 0 267.624 0.084 ;
    END
  END c_o[148]
  PIN c_o[149]
    DIRECTION OUTPUT ;
    USE SIGNAL ;
    PORT
      LAYER M5 ;
        RECT  267.744 0 267.768 0.084 ;
    END
  END c_o[149]
  PIN c_o[14]
    DIRECTION OUTPUT ;
    USE SIGNAL ;
    PORT
      LAYER M5 ;
        RECT  248.304 0 248.328 0.084 ;
    END
  END c_o[14]
  PIN c_o[150]
    DIRECTION OUTPUT ;
    USE SIGNAL ;
    PORT
      LAYER M5 ;
        RECT  267.888 0 267.912 0.084 ;
    END
  END c_o[150]
  PIN c_o[151]
    DIRECTION OUTPUT ;
    USE SIGNAL ;
    PORT
      LAYER M5 ;
        RECT  268.032 0 268.056 0.084 ;
    END
  END c_o[151]
  PIN c_o[152]
    DIRECTION OUTPUT ;
    USE SIGNAL ;
    PORT
      LAYER M5 ;
        RECT  268.176 0 268.2 0.084 ;
    END
  END c_o[152]
  PIN c_o[153]
    DIRECTION OUTPUT ;
    USE SIGNAL ;
    PORT
      LAYER M5 ;
        RECT  268.32 0 268.344 0.084 ;
    END
  END c_o[153]
  PIN c_o[154]
    DIRECTION OUTPUT ;
    USE SIGNAL ;
    PORT
      LAYER M5 ;
        RECT  268.464 0 268.488 0.084 ;
    END
  END c_o[154]
  PIN c_o[155]
    DIRECTION OUTPUT ;
    USE SIGNAL ;
    PORT
      LAYER M5 ;
        RECT  268.608 0 268.632 0.084 ;
    END
  END c_o[155]
  PIN c_o[156]
    DIRECTION OUTPUT ;
    USE SIGNAL ;
    PORT
      LAYER M5 ;
        RECT  268.752 0 268.776 0.084 ;
    END
  END c_o[156]
  PIN c_o[157]
    DIRECTION OUTPUT ;
    USE SIGNAL ;
    PORT
      LAYER M5 ;
        RECT  268.896 0 268.92 0.084 ;
    END
  END c_o[157]
  PIN c_o[158]
    DIRECTION OUTPUT ;
    USE SIGNAL ;
    PORT
      LAYER M5 ;
        RECT  269.04 0 269.064 0.084 ;
    END
  END c_o[158]
  PIN c_o[159]
    DIRECTION OUTPUT ;
    USE SIGNAL ;
    PORT
      LAYER M5 ;
        RECT  269.184 0 269.208 0.084 ;
    END
  END c_o[159]
  PIN c_o[15]
    DIRECTION OUTPUT ;
    USE SIGNAL ;
    PORT
      LAYER M5 ;
        RECT  248.448 0 248.472 0.084 ;
    END
  END c_o[15]
  PIN c_o[160]
    DIRECTION OUTPUT ;
    USE SIGNAL ;
    PORT
      LAYER M5 ;
        RECT  269.328 0 269.352 0.084 ;
    END
  END c_o[160]
  PIN c_o[161]
    DIRECTION OUTPUT ;
    USE SIGNAL ;
    PORT
      LAYER M5 ;
        RECT  269.472 0 269.496 0.084 ;
    END
  END c_o[161]
  PIN c_o[162]
    DIRECTION OUTPUT ;
    USE SIGNAL ;
    PORT
      LAYER M5 ;
        RECT  269.616 0 269.64 0.084 ;
    END
  END c_o[162]
  PIN c_o[163]
    DIRECTION OUTPUT ;
    USE SIGNAL ;
    PORT
      LAYER M5 ;
        RECT  269.76 0 269.784 0.084 ;
    END
  END c_o[163]
  PIN c_o[164]
    DIRECTION OUTPUT ;
    USE SIGNAL ;
    PORT
      LAYER M5 ;
        RECT  269.904 0 269.928 0.084 ;
    END
  END c_o[164]
  PIN c_o[165]
    DIRECTION OUTPUT ;
    USE SIGNAL ;
    PORT
      LAYER M5 ;
        RECT  270.048 0 270.072 0.084 ;
    END
  END c_o[165]
  PIN c_o[166]
    DIRECTION OUTPUT ;
    USE SIGNAL ;
    PORT
      LAYER M5 ;
        RECT  270.192 0 270.216 0.084 ;
    END
  END c_o[166]
  PIN c_o[167]
    DIRECTION OUTPUT ;
    USE SIGNAL ;
    PORT
      LAYER M5 ;
        RECT  270.336 0 270.36 0.084 ;
    END
  END c_o[167]
  PIN c_o[168]
    DIRECTION OUTPUT ;
    USE SIGNAL ;
    PORT
      LAYER M5 ;
        RECT  270.48 0 270.504 0.084 ;
    END
  END c_o[168]
  PIN c_o[169]
    DIRECTION OUTPUT ;
    USE SIGNAL ;
    PORT
      LAYER M5 ;
        RECT  270.624 0 270.648 0.084 ;
    END
  END c_o[169]
  PIN c_o[16]
    DIRECTION OUTPUT ;
    USE SIGNAL ;
    PORT
      LAYER M5 ;
        RECT  248.592 0 248.616 0.084 ;
    END
  END c_o[16]
  PIN c_o[170]
    DIRECTION OUTPUT ;
    USE SIGNAL ;
    PORT
      LAYER M5 ;
        RECT  270.768 0 270.792 0.084 ;
    END
  END c_o[170]
  PIN c_o[171]
    DIRECTION OUTPUT ;
    USE SIGNAL ;
    PORT
      LAYER M5 ;
        RECT  270.912 0 270.936 0.084 ;
    END
  END c_o[171]
  PIN c_o[172]
    DIRECTION OUTPUT ;
    USE SIGNAL ;
    PORT
      LAYER M5 ;
        RECT  271.056 0 271.08 0.084 ;
    END
  END c_o[172]
  PIN c_o[173]
    DIRECTION OUTPUT ;
    USE SIGNAL ;
    PORT
      LAYER M5 ;
        RECT  271.2 0 271.224 0.084 ;
    END
  END c_o[173]
  PIN c_o[174]
    DIRECTION OUTPUT ;
    USE SIGNAL ;
    PORT
      LAYER M5 ;
        RECT  271.344 0 271.368 0.084 ;
    END
  END c_o[174]
  PIN c_o[175]
    DIRECTION OUTPUT ;
    USE SIGNAL ;
    PORT
      LAYER M5 ;
        RECT  271.488 0 271.512 0.084 ;
    END
  END c_o[175]
  PIN c_o[176]
    DIRECTION OUTPUT ;
    USE SIGNAL ;
    PORT
      LAYER M5 ;
        RECT  271.632 0 271.656 0.084 ;
    END
  END c_o[176]
  PIN c_o[177]
    DIRECTION OUTPUT ;
    USE SIGNAL ;
    PORT
      LAYER M5 ;
        RECT  271.776 0 271.8 0.084 ;
    END
  END c_o[177]
  PIN c_o[178]
    DIRECTION OUTPUT ;
    USE SIGNAL ;
    PORT
      LAYER M5 ;
        RECT  271.92 0 271.944 0.084 ;
    END
  END c_o[178]
  PIN c_o[179]
    DIRECTION OUTPUT ;
    USE SIGNAL ;
    PORT
      LAYER M5 ;
        RECT  272.064 0 272.088 0.084 ;
    END
  END c_o[179]
  PIN c_o[17]
    DIRECTION OUTPUT ;
    USE SIGNAL ;
    PORT
      LAYER M5 ;
        RECT  248.736 0 248.76 0.084 ;
    END
  END c_o[17]
  PIN c_o[180]
    DIRECTION OUTPUT ;
    USE SIGNAL ;
    PORT
      LAYER M5 ;
        RECT  272.208 0 272.232 0.084 ;
    END
  END c_o[180]
  PIN c_o[181]
    DIRECTION OUTPUT ;
    USE SIGNAL ;
    PORT
      LAYER M5 ;
        RECT  272.352 0 272.376 0.084 ;
    END
  END c_o[181]
  PIN c_o[182]
    DIRECTION OUTPUT ;
    USE SIGNAL ;
    PORT
      LAYER M5 ;
        RECT  272.496 0 272.52 0.084 ;
    END
  END c_o[182]
  PIN c_o[183]
    DIRECTION OUTPUT ;
    USE SIGNAL ;
    PORT
      LAYER M5 ;
        RECT  272.64 0 272.664 0.084 ;
    END
  END c_o[183]
  PIN c_o[184]
    DIRECTION OUTPUT ;
    USE SIGNAL ;
    PORT
      LAYER M5 ;
        RECT  272.784 0 272.808 0.084 ;
    END
  END c_o[184]
  PIN c_o[185]
    DIRECTION OUTPUT ;
    USE SIGNAL ;
    PORT
      LAYER M5 ;
        RECT  272.928 0 272.952 0.084 ;
    END
  END c_o[185]
  PIN c_o[186]
    DIRECTION OUTPUT ;
    USE SIGNAL ;
    PORT
      LAYER M5 ;
        RECT  273.072 0 273.096 0.084 ;
    END
  END c_o[186]
  PIN c_o[187]
    DIRECTION OUTPUT ;
    USE SIGNAL ;
    PORT
      LAYER M5 ;
        RECT  273.216 0 273.24 0.084 ;
    END
  END c_o[187]
  PIN c_o[188]
    DIRECTION OUTPUT ;
    USE SIGNAL ;
    PORT
      LAYER M5 ;
        RECT  273.36 0 273.384 0.084 ;
    END
  END c_o[188]
  PIN c_o[189]
    DIRECTION OUTPUT ;
    USE SIGNAL ;
    PORT
      LAYER M5 ;
        RECT  273.504 0 273.528 0.084 ;
    END
  END c_o[189]
  PIN c_o[18]
    DIRECTION OUTPUT ;
    USE SIGNAL ;
    PORT
      LAYER M5 ;
        RECT  248.88 0 248.904 0.084 ;
    END
  END c_o[18]
  PIN c_o[190]
    DIRECTION OUTPUT ;
    USE SIGNAL ;
    PORT
      LAYER M5 ;
        RECT  273.648 0 273.672 0.084 ;
    END
  END c_o[190]
  PIN c_o[191]
    DIRECTION OUTPUT ;
    USE SIGNAL ;
    PORT
      LAYER M5 ;
        RECT  273.792 0 273.816 0.084 ;
    END
  END c_o[191]
  PIN c_o[192]
    DIRECTION OUTPUT ;
    USE SIGNAL ;
    PORT
      LAYER M5 ;
        RECT  273.936 0 273.96 0.084 ;
    END
  END c_o[192]
  PIN c_o[193]
    DIRECTION OUTPUT ;
    USE SIGNAL ;
    PORT
      LAYER M5 ;
        RECT  274.08 0 274.104 0.084 ;
    END
  END c_o[193]
  PIN c_o[194]
    DIRECTION OUTPUT ;
    USE SIGNAL ;
    PORT
      LAYER M5 ;
        RECT  274.224 0 274.248 0.084 ;
    END
  END c_o[194]
  PIN c_o[195]
    DIRECTION OUTPUT ;
    USE SIGNAL ;
    PORT
      LAYER M5 ;
        RECT  274.368 0 274.392 0.084 ;
    END
  END c_o[195]
  PIN c_o[196]
    DIRECTION OUTPUT ;
    USE SIGNAL ;
    PORT
      LAYER M5 ;
        RECT  274.512 0 274.536 0.084 ;
    END
  END c_o[196]
  PIN c_o[197]
    DIRECTION OUTPUT ;
    USE SIGNAL ;
    PORT
      LAYER M5 ;
        RECT  274.656 0 274.68 0.084 ;
    END
  END c_o[197]
  PIN c_o[198]
    DIRECTION OUTPUT ;
    USE SIGNAL ;
    PORT
      LAYER M5 ;
        RECT  274.8 0 274.824 0.084 ;
    END
  END c_o[198]
  PIN c_o[199]
    DIRECTION OUTPUT ;
    USE SIGNAL ;
    PORT
      LAYER M5 ;
        RECT  274.944 0 274.968 0.084 ;
    END
  END c_o[199]
  PIN c_o[19]
    DIRECTION OUTPUT ;
    USE SIGNAL ;
    PORT
      LAYER M5 ;
        RECT  249.024 0 249.048 0.084 ;
    END
  END c_o[19]
  PIN c_o[1]
    DIRECTION OUTPUT ;
    USE SIGNAL ;
    PORT
      LAYER M5 ;
        RECT  246.432 0 246.456 0.084 ;
    END
  END c_o[1]
  PIN c_o[200]
    DIRECTION OUTPUT ;
    USE SIGNAL ;
    PORT
      LAYER M5 ;
        RECT  275.088 0 275.112 0.084 ;
    END
  END c_o[200]
  PIN c_o[201]
    DIRECTION OUTPUT ;
    USE SIGNAL ;
    PORT
      LAYER M5 ;
        RECT  275.232 0 275.256 0.084 ;
    END
  END c_o[201]
  PIN c_o[202]
    DIRECTION OUTPUT ;
    USE SIGNAL ;
    PORT
      LAYER M5 ;
        RECT  275.376 0 275.4 0.084 ;
    END
  END c_o[202]
  PIN c_o[203]
    DIRECTION OUTPUT ;
    USE SIGNAL ;
    PORT
      LAYER M5 ;
        RECT  275.52 0 275.544 0.084 ;
    END
  END c_o[203]
  PIN c_o[204]
    DIRECTION OUTPUT ;
    USE SIGNAL ;
    PORT
      LAYER M5 ;
        RECT  275.664 0 275.688 0.084 ;
    END
  END c_o[204]
  PIN c_o[205]
    DIRECTION OUTPUT ;
    USE SIGNAL ;
    PORT
      LAYER M5 ;
        RECT  275.808 0 275.832 0.084 ;
    END
  END c_o[205]
  PIN c_o[206]
    DIRECTION OUTPUT ;
    USE SIGNAL ;
    PORT
      LAYER M5 ;
        RECT  275.952 0 275.976 0.084 ;
    END
  END c_o[206]
  PIN c_o[207]
    DIRECTION OUTPUT ;
    USE SIGNAL ;
    PORT
      LAYER M5 ;
        RECT  276.096 0 276.12 0.084 ;
    END
  END c_o[207]
  PIN c_o[208]
    DIRECTION OUTPUT ;
    USE SIGNAL ;
    PORT
      LAYER M5 ;
        RECT  276.24 0 276.264 0.084 ;
    END
  END c_o[208]
  PIN c_o[209]
    DIRECTION OUTPUT ;
    USE SIGNAL ;
    PORT
      LAYER M5 ;
        RECT  276.384 0 276.408 0.084 ;
    END
  END c_o[209]
  PIN c_o[20]
    DIRECTION OUTPUT ;
    USE SIGNAL ;
    PORT
      LAYER M5 ;
        RECT  249.168 0 249.192 0.084 ;
    END
  END c_o[20]
  PIN c_o[210]
    DIRECTION OUTPUT ;
    USE SIGNAL ;
    PORT
      LAYER M5 ;
        RECT  276.528 0 276.552 0.084 ;
    END
  END c_o[210]
  PIN c_o[211]
    DIRECTION OUTPUT ;
    USE SIGNAL ;
    PORT
      LAYER M5 ;
        RECT  276.672 0 276.696 0.084 ;
    END
  END c_o[211]
  PIN c_o[212]
    DIRECTION OUTPUT ;
    USE SIGNAL ;
    PORT
      LAYER M5 ;
        RECT  276.816 0 276.84 0.084 ;
    END
  END c_o[212]
  PIN c_o[213]
    DIRECTION OUTPUT ;
    USE SIGNAL ;
    PORT
      LAYER M5 ;
        RECT  276.96 0 276.984 0.084 ;
    END
  END c_o[213]
  PIN c_o[214]
    DIRECTION OUTPUT ;
    USE SIGNAL ;
    PORT
      LAYER M5 ;
        RECT  277.104 0 277.128 0.084 ;
    END
  END c_o[214]
  PIN c_o[215]
    DIRECTION OUTPUT ;
    USE SIGNAL ;
    PORT
      LAYER M5 ;
        RECT  277.248 0 277.272 0.084 ;
    END
  END c_o[215]
  PIN c_o[216]
    DIRECTION OUTPUT ;
    USE SIGNAL ;
    PORT
      LAYER M5 ;
        RECT  277.392 0 277.416 0.084 ;
    END
  END c_o[216]
  PIN c_o[217]
    DIRECTION OUTPUT ;
    USE SIGNAL ;
    PORT
      LAYER M5 ;
        RECT  277.536 0 277.56 0.084 ;
    END
  END c_o[217]
  PIN c_o[218]
    DIRECTION OUTPUT ;
    USE SIGNAL ;
    PORT
      LAYER M5 ;
        RECT  277.68 0 277.704 0.084 ;
    END
  END c_o[218]
  PIN c_o[219]
    DIRECTION OUTPUT ;
    USE SIGNAL ;
    PORT
      LAYER M4 ;
        RECT  0 120.96 0.084 120.984 ;
    END
  END c_o[219]
  PIN c_o[21]
    DIRECTION OUTPUT ;
    USE SIGNAL ;
    PORT
      LAYER M5 ;
        RECT  249.312 0 249.336 0.084 ;
    END
  END c_o[21]
  PIN c_o[220]
    DIRECTION OUTPUT ;
    USE SIGNAL ;
    PORT
      LAYER M4 ;
        RECT  0 121.104 0.084 121.128 ;
    END
  END c_o[220]
  PIN c_o[221]
    DIRECTION OUTPUT ;
    USE SIGNAL ;
    PORT
      LAYER M4 ;
        RECT  0 121.248 0.084 121.272 ;
    END
  END c_o[221]
  PIN c_o[222]
    DIRECTION OUTPUT ;
    USE SIGNAL ;
    PORT
      LAYER M4 ;
        RECT  0 121.392 0.084 121.416 ;
    END
  END c_o[222]
  PIN c_o[223]
    DIRECTION OUTPUT ;
    USE SIGNAL ;
    PORT
      LAYER M4 ;
        RECT  0 121.536 0.084 121.56 ;
    END
  END c_o[223]
  PIN c_o[224]
    DIRECTION OUTPUT ;
    USE SIGNAL ;
    PORT
      LAYER M4 ;
        RECT  0 121.68 0.084 121.704 ;
    END
  END c_o[224]
  PIN c_o[225]
    DIRECTION OUTPUT ;
    USE SIGNAL ;
    PORT
      LAYER M4 ;
        RECT  0 121.824 0.084 121.848 ;
    END
  END c_o[225]
  PIN c_o[226]
    DIRECTION OUTPUT ;
    USE SIGNAL ;
    PORT
      LAYER M4 ;
        RECT  0 121.968 0.084 121.992 ;
    END
  END c_o[226]
  PIN c_o[227]
    DIRECTION OUTPUT ;
    USE SIGNAL ;
    PORT
      LAYER M4 ;
        RECT  0 122.112 0.084 122.136 ;
    END
  END c_o[227]
  PIN c_o[228]
    DIRECTION OUTPUT ;
    USE SIGNAL ;
    PORT
      LAYER M4 ;
        RECT  0 122.256 0.084 122.28 ;
    END
  END c_o[228]
  PIN c_o[229]
    DIRECTION OUTPUT ;
    USE SIGNAL ;
    PORT
      LAYER M4 ;
        RECT  0 122.4 0.084 122.424 ;
    END
  END c_o[229]
  PIN c_o[22]
    DIRECTION OUTPUT ;
    USE SIGNAL ;
    PORT
      LAYER M5 ;
        RECT  249.456 0 249.48 0.084 ;
    END
  END c_o[22]
  PIN c_o[230]
    DIRECTION OUTPUT ;
    USE SIGNAL ;
    PORT
      LAYER M4 ;
        RECT  0 122.544 0.084 122.568 ;
    END
  END c_o[230]
  PIN c_o[231]
    DIRECTION OUTPUT ;
    USE SIGNAL ;
    PORT
      LAYER M4 ;
        RECT  0 122.688 0.084 122.712 ;
    END
  END c_o[231]
  PIN c_o[232]
    DIRECTION OUTPUT ;
    USE SIGNAL ;
    PORT
      LAYER M4 ;
        RECT  0 122.832 0.084 122.856 ;
    END
  END c_o[232]
  PIN c_o[233]
    DIRECTION OUTPUT ;
    USE SIGNAL ;
    PORT
      LAYER M4 ;
        RECT  0 122.976 0.084 123 ;
    END
  END c_o[233]
  PIN c_o[234]
    DIRECTION OUTPUT ;
    USE SIGNAL ;
    PORT
      LAYER M4 ;
        RECT  0 123.12 0.084 123.144 ;
    END
  END c_o[234]
  PIN c_o[235]
    DIRECTION OUTPUT ;
    USE SIGNAL ;
    PORT
      LAYER M4 ;
        RECT  0 123.264 0.084 123.288 ;
    END
  END c_o[235]
  PIN c_o[236]
    DIRECTION OUTPUT ;
    USE SIGNAL ;
    PORT
      LAYER M4 ;
        RECT  0 123.408 0.084 123.432 ;
    END
  END c_o[236]
  PIN c_o[237]
    DIRECTION OUTPUT ;
    USE SIGNAL ;
    PORT
      LAYER M4 ;
        RECT  0 123.552 0.084 123.576 ;
    END
  END c_o[237]
  PIN c_o[238]
    DIRECTION OUTPUT ;
    USE SIGNAL ;
    PORT
      LAYER M4 ;
        RECT  0 123.696 0.084 123.72 ;
    END
  END c_o[238]
  PIN c_o[239]
    DIRECTION OUTPUT ;
    USE SIGNAL ;
    PORT
      LAYER M4 ;
        RECT  0 123.84 0.084 123.864 ;
    END
  END c_o[239]
  PIN c_o[23]
    DIRECTION OUTPUT ;
    USE SIGNAL ;
    PORT
      LAYER M5 ;
        RECT  249.6 0 249.624 0.084 ;
    END
  END c_o[23]
  PIN c_o[240]
    DIRECTION OUTPUT ;
    USE SIGNAL ;
    PORT
      LAYER M4 ;
        RECT  0 123.984 0.084 124.008 ;
    END
  END c_o[240]
  PIN c_o[241]
    DIRECTION OUTPUT ;
    USE SIGNAL ;
    PORT
      LAYER M4 ;
        RECT  0 124.128 0.084 124.152 ;
    END
  END c_o[241]
  PIN c_o[242]
    DIRECTION OUTPUT ;
    USE SIGNAL ;
    PORT
      LAYER M4 ;
        RECT  0 124.272 0.084 124.296 ;
    END
  END c_o[242]
  PIN c_o[243]
    DIRECTION OUTPUT ;
    USE SIGNAL ;
    PORT
      LAYER M4 ;
        RECT  0 124.416 0.084 124.44 ;
    END
  END c_o[243]
  PIN c_o[244]
    DIRECTION OUTPUT ;
    USE SIGNAL ;
    PORT
      LAYER M4 ;
        RECT  0 124.56 0.084 124.584 ;
    END
  END c_o[244]
  PIN c_o[245]
    DIRECTION OUTPUT ;
    USE SIGNAL ;
    PORT
      LAYER M4 ;
        RECT  0 124.704 0.084 124.728 ;
    END
  END c_o[245]
  PIN c_o[246]
    DIRECTION OUTPUT ;
    USE SIGNAL ;
    PORT
      LAYER M4 ;
        RECT  0 124.848 0.084 124.872 ;
    END
  END c_o[246]
  PIN c_o[247]
    DIRECTION OUTPUT ;
    USE SIGNAL ;
    PORT
      LAYER M4 ;
        RECT  0 124.992 0.084 125.016 ;
    END
  END c_o[247]
  PIN c_o[24]
    DIRECTION OUTPUT ;
    USE SIGNAL ;
    PORT
      LAYER M5 ;
        RECT  249.744 0 249.768 0.084 ;
    END
  END c_o[24]
  PIN c_o[25]
    DIRECTION OUTPUT ;
    USE SIGNAL ;
    PORT
      LAYER M5 ;
        RECT  249.888 0 249.912 0.084 ;
    END
  END c_o[25]
  PIN c_o[26]
    DIRECTION OUTPUT ;
    USE SIGNAL ;
    PORT
      LAYER M5 ;
        RECT  250.032 0 250.056 0.084 ;
    END
  END c_o[26]
  PIN c_o[27]
    DIRECTION OUTPUT ;
    USE SIGNAL ;
    PORT
      LAYER M5 ;
        RECT  250.176 0 250.2 0.084 ;
    END
  END c_o[27]
  PIN c_o[28]
    DIRECTION OUTPUT ;
    USE SIGNAL ;
    PORT
      LAYER M5 ;
        RECT  250.32 0 250.344 0.084 ;
    END
  END c_o[28]
  PIN c_o[29]
    DIRECTION OUTPUT ;
    USE SIGNAL ;
    PORT
      LAYER M5 ;
        RECT  250.464 0 250.488 0.084 ;
    END
  END c_o[29]
  PIN c_o[2]
    DIRECTION OUTPUT ;
    USE SIGNAL ;
    PORT
      LAYER M5 ;
        RECT  246.576 0 246.6 0.084 ;
    END
  END c_o[2]
  PIN c_o[30]
    DIRECTION OUTPUT ;
    USE SIGNAL ;
    PORT
      LAYER M5 ;
        RECT  250.608 0 250.632 0.084 ;
    END
  END c_o[30]
  PIN c_o[31]
    DIRECTION OUTPUT ;
    USE SIGNAL ;
    PORT
      LAYER M5 ;
        RECT  250.752 0 250.776 0.084 ;
    END
  END c_o[31]
  PIN c_o[32]
    DIRECTION OUTPUT ;
    USE SIGNAL ;
    PORT
      LAYER M5 ;
        RECT  250.896 0 250.92 0.084 ;
    END
  END c_o[32]
  PIN c_o[33]
    DIRECTION OUTPUT ;
    USE SIGNAL ;
    PORT
      LAYER M5 ;
        RECT  251.04 0 251.064 0.084 ;
    END
  END c_o[33]
  PIN c_o[34]
    DIRECTION OUTPUT ;
    USE SIGNAL ;
    PORT
      LAYER M5 ;
        RECT  251.184 0 251.208 0.084 ;
    END
  END c_o[34]
  PIN c_o[35]
    DIRECTION OUTPUT ;
    USE SIGNAL ;
    PORT
      LAYER M5 ;
        RECT  251.328 0 251.352 0.084 ;
    END
  END c_o[35]
  PIN c_o[36]
    DIRECTION OUTPUT ;
    USE SIGNAL ;
    PORT
      LAYER M5 ;
        RECT  251.472 0 251.496 0.084 ;
    END
  END c_o[36]
  PIN c_o[37]
    DIRECTION OUTPUT ;
    USE SIGNAL ;
    PORT
      LAYER M5 ;
        RECT  251.616 0 251.64 0.084 ;
    END
  END c_o[37]
  PIN c_o[38]
    DIRECTION OUTPUT ;
    USE SIGNAL ;
    PORT
      LAYER M5 ;
        RECT  251.76 0 251.784 0.084 ;
    END
  END c_o[38]
  PIN c_o[39]
    DIRECTION OUTPUT ;
    USE SIGNAL ;
    PORT
      LAYER M5 ;
        RECT  251.904 0 251.928 0.084 ;
    END
  END c_o[39]
  PIN c_o[3]
    DIRECTION OUTPUT ;
    USE SIGNAL ;
    PORT
      LAYER M5 ;
        RECT  246.72 0 246.744 0.084 ;
    END
  END c_o[3]
  PIN c_o[40]
    DIRECTION OUTPUT ;
    USE SIGNAL ;
    PORT
      LAYER M5 ;
        RECT  252.048 0 252.072 0.084 ;
    END
  END c_o[40]
  PIN c_o[41]
    DIRECTION OUTPUT ;
    USE SIGNAL ;
    PORT
      LAYER M5 ;
        RECT  252.192 0 252.216 0.084 ;
    END
  END c_o[41]
  PIN c_o[42]
    DIRECTION OUTPUT ;
    USE SIGNAL ;
    PORT
      LAYER M5 ;
        RECT  252.336 0 252.36 0.084 ;
    END
  END c_o[42]
  PIN c_o[43]
    DIRECTION OUTPUT ;
    USE SIGNAL ;
    PORT
      LAYER M5 ;
        RECT  252.48 0 252.504 0.084 ;
    END
  END c_o[43]
  PIN c_o[44]
    DIRECTION OUTPUT ;
    USE SIGNAL ;
    PORT
      LAYER M5 ;
        RECT  252.624 0 252.648 0.084 ;
    END
  END c_o[44]
  PIN c_o[45]
    DIRECTION OUTPUT ;
    USE SIGNAL ;
    PORT
      LAYER M5 ;
        RECT  252.768 0 252.792 0.084 ;
    END
  END c_o[45]
  PIN c_o[46]
    DIRECTION OUTPUT ;
    USE SIGNAL ;
    PORT
      LAYER M5 ;
        RECT  252.912 0 252.936 0.084 ;
    END
  END c_o[46]
  PIN c_o[47]
    DIRECTION OUTPUT ;
    USE SIGNAL ;
    PORT
      LAYER M5 ;
        RECT  253.056 0 253.08 0.084 ;
    END
  END c_o[47]
  PIN c_o[48]
    DIRECTION OUTPUT ;
    USE SIGNAL ;
    PORT
      LAYER M5 ;
        RECT  253.2 0 253.224 0.084 ;
    END
  END c_o[48]
  PIN c_o[49]
    DIRECTION OUTPUT ;
    USE SIGNAL ;
    PORT
      LAYER M5 ;
        RECT  253.344 0 253.368 0.084 ;
    END
  END c_o[49]
  PIN c_o[4]
    DIRECTION OUTPUT ;
    USE SIGNAL ;
    PORT
      LAYER M5 ;
        RECT  246.864 0 246.888 0.084 ;
    END
  END c_o[4]
  PIN c_o[50]
    DIRECTION OUTPUT ;
    USE SIGNAL ;
    PORT
      LAYER M5 ;
        RECT  253.488 0 253.512 0.084 ;
    END
  END c_o[50]
  PIN c_o[51]
    DIRECTION OUTPUT ;
    USE SIGNAL ;
    PORT
      LAYER M5 ;
        RECT  253.632 0 253.656 0.084 ;
    END
  END c_o[51]
  PIN c_o[52]
    DIRECTION OUTPUT ;
    USE SIGNAL ;
    PORT
      LAYER M5 ;
        RECT  253.776 0 253.8 0.084 ;
    END
  END c_o[52]
  PIN c_o[53]
    DIRECTION OUTPUT ;
    USE SIGNAL ;
    PORT
      LAYER M5 ;
        RECT  253.92 0 253.944 0.084 ;
    END
  END c_o[53]
  PIN c_o[54]
    DIRECTION OUTPUT ;
    USE SIGNAL ;
    PORT
      LAYER M5 ;
        RECT  254.064 0 254.088 0.084 ;
    END
  END c_o[54]
  PIN c_o[55]
    DIRECTION OUTPUT ;
    USE SIGNAL ;
    PORT
      LAYER M5 ;
        RECT  254.208 0 254.232 0.084 ;
    END
  END c_o[55]
  PIN c_o[56]
    DIRECTION OUTPUT ;
    USE SIGNAL ;
    PORT
      LAYER M5 ;
        RECT  254.352 0 254.376 0.084 ;
    END
  END c_o[56]
  PIN c_o[57]
    DIRECTION OUTPUT ;
    USE SIGNAL ;
    PORT
      LAYER M5 ;
        RECT  254.496 0 254.52 0.084 ;
    END
  END c_o[57]
  PIN c_o[58]
    DIRECTION OUTPUT ;
    USE SIGNAL ;
    PORT
      LAYER M5 ;
        RECT  254.64 0 254.664 0.084 ;
    END
  END c_o[58]
  PIN c_o[59]
    DIRECTION OUTPUT ;
    USE SIGNAL ;
    PORT
      LAYER M5 ;
        RECT  254.784 0 254.808 0.084 ;
    END
  END c_o[59]
  PIN c_o[5]
    DIRECTION OUTPUT ;
    USE SIGNAL ;
    PORT
      LAYER M5 ;
        RECT  247.008 0 247.032 0.084 ;
    END
  END c_o[5]
  PIN c_o[60]
    DIRECTION OUTPUT ;
    USE SIGNAL ;
    PORT
      LAYER M5 ;
        RECT  254.928 0 254.952 0.084 ;
    END
  END c_o[60]
  PIN c_o[61]
    DIRECTION OUTPUT ;
    USE SIGNAL ;
    PORT
      LAYER M5 ;
        RECT  255.072 0 255.096 0.084 ;
    END
  END c_o[61]
  PIN c_o[62]
    DIRECTION OUTPUT ;
    USE SIGNAL ;
    PORT
      LAYER M5 ;
        RECT  255.216 0 255.24 0.084 ;
    END
  END c_o[62]
  PIN c_o[63]
    DIRECTION OUTPUT ;
    USE SIGNAL ;
    PORT
      LAYER M5 ;
        RECT  255.36 0 255.384 0.084 ;
    END
  END c_o[63]
  PIN c_o[64]
    DIRECTION OUTPUT ;
    USE SIGNAL ;
    PORT
      LAYER M5 ;
        RECT  255.504 0 255.528 0.084 ;
    END
  END c_o[64]
  PIN c_o[65]
    DIRECTION OUTPUT ;
    USE SIGNAL ;
    PORT
      LAYER M5 ;
        RECT  255.648 0 255.672 0.084 ;
    END
  END c_o[65]
  PIN c_o[66]
    DIRECTION OUTPUT ;
    USE SIGNAL ;
    PORT
      LAYER M5 ;
        RECT  255.792 0 255.816 0.084 ;
    END
  END c_o[66]
  PIN c_o[67]
    DIRECTION OUTPUT ;
    USE SIGNAL ;
    PORT
      LAYER M5 ;
        RECT  255.936 0 255.96 0.084 ;
    END
  END c_o[67]
  PIN c_o[68]
    DIRECTION OUTPUT ;
    USE SIGNAL ;
    PORT
      LAYER M5 ;
        RECT  256.08 0 256.104 0.084 ;
    END
  END c_o[68]
  PIN c_o[69]
    DIRECTION OUTPUT ;
    USE SIGNAL ;
    PORT
      LAYER M5 ;
        RECT  256.224 0 256.248 0.084 ;
    END
  END c_o[69]
  PIN c_o[6]
    DIRECTION OUTPUT ;
    USE SIGNAL ;
    PORT
      LAYER M5 ;
        RECT  247.152 0 247.176 0.084 ;
    END
  END c_o[6]
  PIN c_o[70]
    DIRECTION OUTPUT ;
    USE SIGNAL ;
    PORT
      LAYER M5 ;
        RECT  256.368 0 256.392 0.084 ;
    END
  END c_o[70]
  PIN c_o[71]
    DIRECTION OUTPUT ;
    USE SIGNAL ;
    PORT
      LAYER M5 ;
        RECT  256.512 0 256.536 0.084 ;
    END
  END c_o[71]
  PIN c_o[72]
    DIRECTION OUTPUT ;
    USE SIGNAL ;
    PORT
      LAYER M5 ;
        RECT  256.656 0 256.68 0.084 ;
    END
  END c_o[72]
  PIN c_o[73]
    DIRECTION OUTPUT ;
    USE SIGNAL ;
    PORT
      LAYER M5 ;
        RECT  256.8 0 256.824 0.084 ;
    END
  END c_o[73]
  PIN c_o[74]
    DIRECTION OUTPUT ;
    USE SIGNAL ;
    PORT
      LAYER M5 ;
        RECT  256.944 0 256.968 0.084 ;
    END
  END c_o[74]
  PIN c_o[75]
    DIRECTION OUTPUT ;
    USE SIGNAL ;
    PORT
      LAYER M5 ;
        RECT  257.088 0 257.112 0.084 ;
    END
  END c_o[75]
  PIN c_o[76]
    DIRECTION OUTPUT ;
    USE SIGNAL ;
    PORT
      LAYER M5 ;
        RECT  257.232 0 257.256 0.084 ;
    END
  END c_o[76]
  PIN c_o[77]
    DIRECTION OUTPUT ;
    USE SIGNAL ;
    PORT
      LAYER M5 ;
        RECT  257.376 0 257.4 0.084 ;
    END
  END c_o[77]
  PIN c_o[78]
    DIRECTION OUTPUT ;
    USE SIGNAL ;
    PORT
      LAYER M5 ;
        RECT  257.52 0 257.544 0.084 ;
    END
  END c_o[78]
  PIN c_o[79]
    DIRECTION OUTPUT ;
    USE SIGNAL ;
    PORT
      LAYER M5 ;
        RECT  257.664 0 257.688 0.084 ;
    END
  END c_o[79]
  PIN c_o[7]
    DIRECTION OUTPUT ;
    USE SIGNAL ;
    PORT
      LAYER M5 ;
        RECT  247.296 0 247.32 0.084 ;
    END
  END c_o[7]
  PIN c_o[80]
    DIRECTION OUTPUT ;
    USE SIGNAL ;
    PORT
      LAYER M5 ;
        RECT  257.808 0 257.832 0.084 ;
    END
  END c_o[80]
  PIN c_o[81]
    DIRECTION OUTPUT ;
    USE SIGNAL ;
    PORT
      LAYER M5 ;
        RECT  257.952 0 257.976 0.084 ;
    END
  END c_o[81]
  PIN c_o[82]
    DIRECTION OUTPUT ;
    USE SIGNAL ;
    PORT
      LAYER M5 ;
        RECT  258.096 0 258.12 0.084 ;
    END
  END c_o[82]
  PIN c_o[83]
    DIRECTION OUTPUT ;
    USE SIGNAL ;
    PORT
      LAYER M5 ;
        RECT  258.24 0 258.264 0.084 ;
    END
  END c_o[83]
  PIN c_o[84]
    DIRECTION OUTPUT ;
    USE SIGNAL ;
    PORT
      LAYER M5 ;
        RECT  258.384 0 258.408 0.084 ;
    END
  END c_o[84]
  PIN c_o[85]
    DIRECTION OUTPUT ;
    USE SIGNAL ;
    PORT
      LAYER M5 ;
        RECT  258.528 0 258.552 0.084 ;
    END
  END c_o[85]
  PIN c_o[86]
    DIRECTION OUTPUT ;
    USE SIGNAL ;
    PORT
      LAYER M5 ;
        RECT  258.672 0 258.696 0.084 ;
    END
  END c_o[86]
  PIN c_o[87]
    DIRECTION OUTPUT ;
    USE SIGNAL ;
    PORT
      LAYER M5 ;
        RECT  258.816 0 258.84 0.084 ;
    END
  END c_o[87]
  PIN c_o[88]
    DIRECTION OUTPUT ;
    USE SIGNAL ;
    PORT
      LAYER M5 ;
        RECT  258.96 0 258.984 0.084 ;
    END
  END c_o[88]
  PIN c_o[89]
    DIRECTION OUTPUT ;
    USE SIGNAL ;
    PORT
      LAYER M5 ;
        RECT  259.104 0 259.128 0.084 ;
    END
  END c_o[89]
  PIN c_o[8]
    DIRECTION OUTPUT ;
    USE SIGNAL ;
    PORT
      LAYER M5 ;
        RECT  247.44 0 247.464 0.084 ;
    END
  END c_o[8]
  PIN c_o[90]
    DIRECTION OUTPUT ;
    USE SIGNAL ;
    PORT
      LAYER M5 ;
        RECT  259.248 0 259.272 0.084 ;
    END
  END c_o[90]
  PIN c_o[91]
    DIRECTION OUTPUT ;
    USE SIGNAL ;
    PORT
      LAYER M5 ;
        RECT  259.392 0 259.416 0.084 ;
    END
  END c_o[91]
  PIN c_o[92]
    DIRECTION OUTPUT ;
    USE SIGNAL ;
    PORT
      LAYER M5 ;
        RECT  259.536 0 259.56 0.084 ;
    END
  END c_o[92]
  PIN c_o[93]
    DIRECTION OUTPUT ;
    USE SIGNAL ;
    PORT
      LAYER M5 ;
        RECT  259.68 0 259.704 0.084 ;
    END
  END c_o[93]
  PIN c_o[94]
    DIRECTION OUTPUT ;
    USE SIGNAL ;
    PORT
      LAYER M5 ;
        RECT  259.824 0 259.848 0.084 ;
    END
  END c_o[94]
  PIN c_o[95]
    DIRECTION OUTPUT ;
    USE SIGNAL ;
    PORT
      LAYER M5 ;
        RECT  259.968 0 259.992 0.084 ;
    END
  END c_o[95]
  PIN c_o[96]
    DIRECTION OUTPUT ;
    USE SIGNAL ;
    PORT
      LAYER M5 ;
        RECT  260.112 0 260.136 0.084 ;
    END
  END c_o[96]
  PIN c_o[97]
    DIRECTION OUTPUT ;
    USE SIGNAL ;
    PORT
      LAYER M5 ;
        RECT  260.256 0 260.28 0.084 ;
    END
  END c_o[97]
  PIN c_o[98]
    DIRECTION OUTPUT ;
    USE SIGNAL ;
    PORT
      LAYER M5 ;
        RECT  260.4 0 260.424 0.084 ;
    END
  END c_o[98]
  PIN c_o[99]
    DIRECTION OUTPUT ;
    USE SIGNAL ;
    PORT
      LAYER M5 ;
        RECT  260.544 0 260.568 0.084 ;
    END
  END c_o[99]
  PIN c_o[9]
    DIRECTION OUTPUT ;
    USE SIGNAL ;
    PORT
      LAYER M5 ;
        RECT  247.584 0 247.608 0.084 ;
    END
  END c_o[9]
  PIN clk
    DIRECTION INPUT ;
    USE SIGNAL ;
    PORT
      LAYER M5 ;
        RECT  277.824 0 277.848 0.084 ;
    END
  END clk
  PIN rst_n
    DIRECTION INPUT ;
    USE SIGNAL ;
    PORT
      LAYER M5 ;
        RECT  136.704 0 136.728 0.084 ;
    END
  END rst_n
  PIN VSS
    DIRECTION INOUT ;
    USE GROUND ;
    PORT
      LAYER M5 ;
        RECT  408.084 4.297 408.204 263.543 ;
        RECT  403.764 4.297 403.884 263.543 ;
        RECT  399.444 4.297 399.564 263.543 ;
        RECT  395.124 4.297 395.244 263.543 ;
        RECT  390.804 4.297 390.924 263.543 ;
        RECT  386.484 4.297 386.604 263.543 ;
        RECT  382.164 4.297 382.284 263.543 ;
        RECT  377.844 4.297 377.964 263.543 ;
        RECT  373.524 4.297 373.644 263.543 ;
        RECT  369.204 4.297 369.324 263.543 ;
        RECT  364.884 4.297 365.004 263.543 ;
        RECT  360.564 4.297 360.684 263.543 ;
        RECT  356.244 4.297 356.364 263.543 ;
        RECT  351.924 4.297 352.044 263.543 ;
        RECT  347.604 4.297 347.724 263.543 ;
        RECT  343.284 4.297 343.404 263.543 ;
        RECT  338.964 4.297 339.084 263.543 ;
        RECT  334.644 4.297 334.764 263.543 ;
        RECT  330.324 4.297 330.444 263.543 ;
        RECT  326.004 4.297 326.124 263.543 ;
        RECT  321.684 4.297 321.804 263.543 ;
        RECT  317.364 4.297 317.484 263.543 ;
        RECT  313.044 4.297 313.164 263.543 ;
        RECT  308.724 4.297 308.844 263.543 ;
        RECT  304.404 4.297 304.524 263.543 ;
        RECT  300.084 4.297 300.204 263.543 ;
        RECT  295.764 4.297 295.884 263.543 ;
        RECT  291.444 4.297 291.564 263.543 ;
        RECT  287.124 4.297 287.244 263.543 ;
        RECT  282.804 4.297 282.924 263.543 ;
        RECT  278.484 4.297 278.604 263.543 ;
        RECT  274.164 4.297 274.284 263.543 ;
        RECT  269.844 4.297 269.964 263.543 ;
        RECT  265.524 4.297 265.644 263.543 ;
        RECT  261.204 4.297 261.324 263.543 ;
        RECT  256.884 4.297 257.004 263.543 ;
        RECT  252.564 4.297 252.684 263.543 ;
        RECT  248.244 4.297 248.364 263.543 ;
        RECT  243.924 4.297 244.044 263.543 ;
        RECT  239.604 4.297 239.724 263.543 ;
        RECT  235.284 4.297 235.404 263.543 ;
        RECT  230.964 4.297 231.084 263.543 ;
        RECT  226.644 4.297 226.764 263.543 ;
        RECT  222.324 4.297 222.444 263.543 ;
        RECT  218.004 4.297 218.124 263.543 ;
        RECT  213.684 4.297 213.804 263.543 ;
        RECT  209.364 4.297 209.484 263.543 ;
        RECT  205.044 4.297 205.164 263.543 ;
        RECT  200.724 4.297 200.844 263.543 ;
        RECT  196.404 4.297 196.524 263.543 ;
        RECT  192.084 4.297 192.204 263.543 ;
        RECT  187.764 4.297 187.884 263.543 ;
        RECT  183.444 4.297 183.564 263.543 ;
        RECT  179.124 4.297 179.244 263.543 ;
        RECT  174.804 4.297 174.924 263.543 ;
        RECT  170.484 4.297 170.604 263.543 ;
        RECT  166.164 4.297 166.284 263.543 ;
        RECT  161.844 4.297 161.964 263.543 ;
        RECT  157.524 4.297 157.644 263.543 ;
        RECT  153.204 4.297 153.324 263.543 ;
        RECT  148.884 4.297 149.004 263.543 ;
        RECT  144.564 4.297 144.684 263.543 ;
        RECT  140.244 4.297 140.364 263.543 ;
        RECT  135.924 4.297 136.044 263.543 ;
        RECT  131.604 4.297 131.724 263.543 ;
        RECT  127.284 4.297 127.404 263.543 ;
        RECT  122.964 4.297 123.084 263.543 ;
        RECT  118.644 4.297 118.764 263.543 ;
        RECT  114.324 4.297 114.444 263.543 ;
        RECT  110.004 4.297 110.124 263.543 ;
        RECT  105.684 4.297 105.804 263.543 ;
        RECT  101.364 4.297 101.484 263.543 ;
        RECT  97.044 4.297 97.164 263.543 ;
        RECT  92.724 4.297 92.844 263.543 ;
        RECT  88.404 4.297 88.524 263.543 ;
        RECT  84.084 4.297 84.204 263.543 ;
        RECT  79.764 4.297 79.884 263.543 ;
        RECT  75.444 4.297 75.564 263.543 ;
        RECT  71.124 4.297 71.244 263.543 ;
        RECT  66.804 4.297 66.924 263.543 ;
        RECT  62.484 4.297 62.604 263.543 ;
        RECT  58.164 4.297 58.284 263.543 ;
        RECT  53.844 4.297 53.964 263.543 ;
        RECT  49.524 4.297 49.644 263.543 ;
        RECT  45.204 4.297 45.324 263.543 ;
        RECT  40.884 4.297 41.004 263.543 ;
        RECT  36.564 4.297 36.684 263.543 ;
        RECT  32.244 4.297 32.364 263.543 ;
        RECT  27.924 4.297 28.044 263.543 ;
        RECT  23.604 4.297 23.724 263.543 ;
        RECT  19.284 4.297 19.404 263.543 ;
        RECT  14.964 4.297 15.084 263.543 ;
        RECT  10.644 4.297 10.764 263.543 ;
        RECT  6.324 4.297 6.444 263.543 ;
    END
  END VSS
  PIN VDD
    DIRECTION INOUT ;
    USE POWER ;
    PORT
      LAYER M5 ;
        RECT  408.276 4.311 408.396 263.529 ;
        RECT  403.956 4.311 404.076 263.529 ;
        RECT  399.636 4.311 399.756 263.529 ;
        RECT  395.316 4.311 395.436 263.529 ;
        RECT  390.996 4.311 391.116 263.529 ;
        RECT  386.676 4.311 386.796 263.529 ;
        RECT  382.356 4.311 382.476 263.529 ;
        RECT  378.036 4.311 378.156 263.529 ;
        RECT  373.716 4.311 373.836 263.529 ;
        RECT  369.396 4.311 369.516 263.529 ;
        RECT  365.076 4.311 365.196 263.529 ;
        RECT  360.756 4.311 360.876 263.529 ;
        RECT  356.436 4.311 356.556 263.529 ;
        RECT  352.116 4.311 352.236 263.529 ;
        RECT  347.796 4.311 347.916 263.529 ;
        RECT  343.476 4.311 343.596 263.529 ;
        RECT  339.156 4.311 339.276 263.529 ;
        RECT  334.836 4.311 334.956 263.529 ;
        RECT  330.516 4.311 330.636 263.529 ;
        RECT  326.196 4.311 326.316 263.529 ;
        RECT  321.876 4.311 321.996 263.529 ;
        RECT  317.556 4.311 317.676 263.529 ;
        RECT  313.236 4.311 313.356 263.529 ;
        RECT  308.916 4.311 309.036 263.529 ;
        RECT  304.596 4.311 304.716 263.529 ;
        RECT  300.276 4.311 300.396 263.529 ;
        RECT  295.956 4.311 296.076 263.529 ;
        RECT  291.636 4.311 291.756 263.529 ;
        RECT  287.316 4.311 287.436 263.529 ;
        RECT  282.996 4.311 283.116 263.529 ;
        RECT  278.676 4.311 278.796 263.529 ;
        RECT  274.356 4.311 274.476 263.529 ;
        RECT  270.036 4.311 270.156 263.529 ;
        RECT  265.716 4.311 265.836 263.529 ;
        RECT  261.396 4.311 261.516 263.529 ;
        RECT  257.076 4.311 257.196 263.529 ;
        RECT  252.756 4.311 252.876 263.529 ;
        RECT  248.436 4.311 248.556 263.529 ;
        RECT  244.116 4.311 244.236 263.529 ;
        RECT  239.796 4.311 239.916 263.529 ;
        RECT  235.476 4.311 235.596 263.529 ;
        RECT  231.156 4.311 231.276 263.529 ;
        RECT  226.836 4.311 226.956 263.529 ;
        RECT  222.516 4.311 222.636 263.529 ;
        RECT  218.196 4.311 218.316 263.529 ;
        RECT  213.876 4.311 213.996 263.529 ;
        RECT  209.556 4.311 209.676 263.529 ;
        RECT  205.236 4.311 205.356 263.529 ;
        RECT  200.916 4.311 201.036 263.529 ;
        RECT  196.596 4.311 196.716 263.529 ;
        RECT  192.276 4.311 192.396 263.529 ;
        RECT  187.956 4.311 188.076 263.529 ;
        RECT  183.636 4.311 183.756 263.529 ;
        RECT  179.316 4.311 179.436 263.529 ;
        RECT  174.996 4.311 175.116 263.529 ;
        RECT  170.676 4.311 170.796 263.529 ;
        RECT  166.356 4.311 166.476 263.529 ;
        RECT  162.036 4.311 162.156 263.529 ;
        RECT  157.716 4.311 157.836 263.529 ;
        RECT  153.396 4.311 153.516 263.529 ;
        RECT  149.076 4.311 149.196 263.529 ;
        RECT  144.756 4.311 144.876 263.529 ;
        RECT  140.436 4.311 140.556 263.529 ;
        RECT  136.116 4.311 136.236 263.529 ;
        RECT  131.796 4.311 131.916 263.529 ;
        RECT  127.476 4.311 127.596 263.529 ;
        RECT  123.156 4.311 123.276 263.529 ;
        RECT  118.836 4.311 118.956 263.529 ;
        RECT  114.516 4.311 114.636 263.529 ;
        RECT  110.196 4.311 110.316 263.529 ;
        RECT  105.876 4.311 105.996 263.529 ;
        RECT  101.556 4.311 101.676 263.529 ;
        RECT  97.236 4.311 97.356 263.529 ;
        RECT  92.916 4.311 93.036 263.529 ;
        RECT  88.596 4.311 88.716 263.529 ;
        RECT  84.276 4.311 84.396 263.529 ;
        RECT  79.956 4.311 80.076 263.529 ;
        RECT  75.636 4.311 75.756 263.529 ;
        RECT  71.316 4.311 71.436 263.529 ;
        RECT  66.996 4.311 67.116 263.529 ;
        RECT  62.676 4.311 62.796 263.529 ;
        RECT  58.356 4.311 58.476 263.529 ;
        RECT  54.036 4.311 54.156 263.529 ;
        RECT  49.716 4.311 49.836 263.529 ;
        RECT  45.396 4.311 45.516 263.529 ;
        RECT  41.076 4.311 41.196 263.529 ;
        RECT  36.756 4.311 36.876 263.529 ;
        RECT  32.436 4.311 32.556 263.529 ;
        RECT  28.116 4.311 28.236 263.529 ;
        RECT  23.796 4.311 23.916 263.529 ;
        RECT  19.476 4.311 19.596 263.529 ;
        RECT  15.156 4.311 15.276 263.529 ;
        RECT  10.836 4.311 10.956 263.529 ;
        RECT  6.516 4.311 6.636 263.529 ;
    END
  END VDD
  OBS
    LAYER RVTN ;
     RECT  0 0 410.4 263.543 ;
    LAYER RVTP ;
     RECT  0 0 410.4 263.543 ;
    LAYER M1 ;
     RECT  0 0 410.4 263.543 ;
    LAYER M2 ;
     RECT  0 0 410.4 263.543 ;
    LAYER M3 ;
     RECT  0 0 410.4 263.543 ;
    LAYER M4 ;
     RECT  0 0 410.4 263.543 ;
    LAYER M5 ;
     RECT  0 0 410.4 263.543 ;
  END
END qfd_qc_su_lane_w_l3
END LIBRARY
